VERSION 5.8 ;
BUSBITCHARS "[]" ;
DIVIDERCHAR "/" ;
UNITS
    DATABASE MICRONS 1000 ;
END UNITS

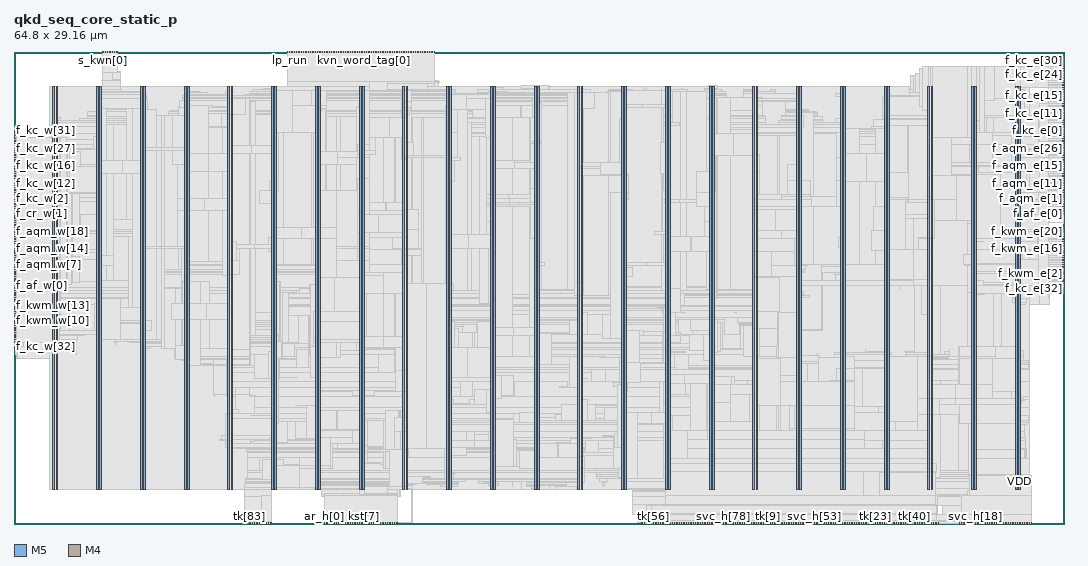
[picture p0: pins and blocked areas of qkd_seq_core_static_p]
MACRO qkd_seq_core_static_p
  FOREIGN qkd_seq_core_static_p 0 0 ;
  CLASS BLOCK ;
  SIZE 64.8 BY 29.16 ;
  PIN ar_h[0]
    DIRECTION INPUT ;
    USE SIGNAL ;
    PORT
      LAYER M5 ;
        RECT  19.152 0 19.176 0.084 ;
    END
  END ar_h[0]
  PIN ar_h[1]
    DIRECTION INPUT ;
    USE SIGNAL ;
    PORT
      LAYER M5 ;
        RECT  19.296 0 19.32 0.084 ;
    END
  END ar_h[1]
  PIN ar_h[2]
    DIRECTION INPUT ;
    USE SIGNAL ;
    PORT
      LAYER M5 ;
        RECT  19.44 0 19.464 0.084 ;
    END
  END ar_h[2]
  PIN ar_h[3]
    DIRECTION INPUT ;
    USE SIGNAL ;
    PORT
      LAYER M5 ;
        RECT  19.584 0 19.608 0.084 ;
    END
  END ar_h[3]
  PIN ar_h[4]
    DIRECTION INPUT ;
    USE SIGNAL ;
    PORT
      LAYER M5 ;
        RECT  19.728 0 19.752 0.084 ;
    END
  END ar_h[4]
  PIN ar_h[5]
    DIRECTION INPUT ;
    USE SIGNAL ;
    PORT
      LAYER M5 ;
        RECT  19.872 0 19.896 0.084 ;
    END
  END ar_h[5]
  PIN ar_h[6]
    DIRECTION INPUT ;
    USE SIGNAL ;
    PORT
      LAYER M5 ;
        RECT  20.016 0 20.04 0.084 ;
    END
  END ar_h[6]
  PIN ar_h[7]
    DIRECTION INPUT ;
    USE SIGNAL ;
    PORT
      LAYER M5 ;
        RECT  20.16 0 20.184 0.084 ;
    END
  END ar_h[7]
  PIN ck
    DIRECTION INPUT ;
    USE SIGNAL ;
    PORT
      LAYER M5 ;
        RECT  21.456 29.076 21.48 29.16 ;
    END
  END ck
  PIN f_af_e[0]
    DIRECTION INPUT ;
    USE SIGNAL ;
    PORT
      LAYER M4 ;
        RECT  64.716 19.152 64.8 19.176 ;
    END
  END f_af_e[0]
  PIN f_af_e[1]
    DIRECTION INPUT ;
    USE SIGNAL ;
    PORT
      LAYER M4 ;
        RECT  64.716 19.296 64.8 19.32 ;
    END
  END f_af_e[1]
  PIN f_af_w[0]
    DIRECTION INPUT ;
    USE SIGNAL ;
    PORT
      LAYER M4 ;
        RECT  0 14.688 0.084 14.712 ;
    END
  END f_af_w[0]
  PIN f_af_w[1]
    DIRECTION INPUT ;
    USE SIGNAL ;
    PORT
      LAYER M4 ;
        RECT  0 14.832 0.084 14.856 ;
    END
  END f_af_w[1]
  PIN f_aqm_e[0]
    DIRECTION OUTPUT ;
    USE SIGNAL ;
    PORT
      LAYER M4 ;
        RECT  64.716 19.44 64.8 19.464 ;
    END
  END f_aqm_e[0]
  PIN f_aqm_e[10]
    DIRECTION OUTPUT ;
    USE SIGNAL ;
    PORT
      LAYER M4 ;
        RECT  64.716 20.88 64.8 20.904 ;
    END
  END f_aqm_e[10]
  PIN f_aqm_e[11]
    DIRECTION OUTPUT ;
    USE SIGNAL ;
    PORT
      LAYER M4 ;
        RECT  64.716 21.024 64.8 21.048 ;
    END
  END f_aqm_e[11]
  PIN f_aqm_e[12]
    DIRECTION OUTPUT ;
    USE SIGNAL ;
    PORT
      LAYER M4 ;
        RECT  64.716 21.168 64.8 21.192 ;
    END
  END f_aqm_e[12]
  PIN f_aqm_e[13]
    DIRECTION OUTPUT ;
    USE SIGNAL ;
    PORT
      LAYER M4 ;
        RECT  64.716 21.312 64.8 21.336 ;
    END
  END f_aqm_e[13]
  PIN f_aqm_e[14]
    DIRECTION OUTPUT ;
    USE SIGNAL ;
    PORT
      LAYER M4 ;
        RECT  64.716 21.456 64.8 21.48 ;
    END
  END f_aqm_e[14]
  PIN f_aqm_e[15]
    DIRECTION OUTPUT ;
    USE SIGNAL ;
    PORT
      LAYER M4 ;
        RECT  64.716 21.6 64.8 21.624 ;
    END
  END f_aqm_e[15]
  PIN f_aqm_e[16]
    DIRECTION OUTPUT ;
    USE SIGNAL ;
    PORT
      LAYER M4 ;
        RECT  64.716 21.744 64.8 21.768 ;
    END
  END f_aqm_e[16]
  PIN f_aqm_e[17]
    DIRECTION OUTPUT ;
    USE SIGNAL ;
    PORT
      LAYER M4 ;
        RECT  64.716 21.888 64.8 21.912 ;
    END
  END f_aqm_e[17]
  PIN f_aqm_e[18]
    DIRECTION OUTPUT ;
    USE SIGNAL ;
    PORT
      LAYER M4 ;
        RECT  64.716 22.032 64.8 22.056 ;
    END
  END f_aqm_e[18]
  PIN f_aqm_e[19]
    DIRECTION OUTPUT ;
    USE SIGNAL ;
    PORT
      LAYER M4 ;
        RECT  64.716 22.176 64.8 22.2 ;
    END
  END f_aqm_e[19]
  PIN f_aqm_e[1]
    DIRECTION OUTPUT ;
    USE SIGNAL ;
    PORT
      LAYER M4 ;
        RECT  64.716 19.584 64.8 19.608 ;
    END
  END f_aqm_e[1]
  PIN f_aqm_e[20]
    DIRECTION OUTPUT ;
    USE SIGNAL ;
    PORT
      LAYER M4 ;
        RECT  64.716 22.32 64.8 22.344 ;
    END
  END f_aqm_e[20]
  PIN f_aqm_e[21]
    DIRECTION OUTPUT ;
    USE SIGNAL ;
    PORT
      LAYER M4 ;
        RECT  64.716 22.464 64.8 22.488 ;
    END
  END f_aqm_e[21]
  PIN f_aqm_e[22]
    DIRECTION OUTPUT ;
    USE SIGNAL ;
    PORT
      LAYER M4 ;
        RECT  64.716 22.608 64.8 22.632 ;
    END
  END f_aqm_e[22]
  PIN f_aqm_e[23]
    DIRECTION OUTPUT ;
    USE SIGNAL ;
    PORT
      LAYER M4 ;
        RECT  64.716 22.752 64.8 22.776 ;
    END
  END f_aqm_e[23]
  PIN f_aqm_e[24]
    DIRECTION OUTPUT ;
    USE SIGNAL ;
    PORT
      LAYER M4 ;
        RECT  64.716 22.896 64.8 22.92 ;
    END
  END f_aqm_e[24]
  PIN f_aqm_e[25]
    DIRECTION OUTPUT ;
    USE SIGNAL ;
    PORT
      LAYER M4 ;
        RECT  64.716 23.04 64.8 23.064 ;
    END
  END f_aqm_e[25]
  PIN f_aqm_e[26]
    DIRECTION OUTPUT ;
    USE SIGNAL ;
    PORT
      LAYER M4 ;
        RECT  64.716 23.184 64.8 23.208 ;
    END
  END f_aqm_e[26]
  PIN f_aqm_e[27]
    DIRECTION OUTPUT ;
    USE SIGNAL ;
    PORT
      LAYER M4 ;
        RECT  64.716 23.328 64.8 23.352 ;
    END
  END f_aqm_e[27]
  PIN f_aqm_e[2]
    DIRECTION OUTPUT ;
    USE SIGNAL ;
    PORT
      LAYER M4 ;
        RECT  64.716 19.728 64.8 19.752 ;
    END
  END f_aqm_e[2]
  PIN f_aqm_e[3]
    DIRECTION OUTPUT ;
    USE SIGNAL ;
    PORT
      LAYER M4 ;
        RECT  64.716 19.872 64.8 19.896 ;
    END
  END f_aqm_e[3]
  PIN f_aqm_e[4]
    DIRECTION OUTPUT ;
    USE SIGNAL ;
    PORT
      LAYER M4 ;
        RECT  64.716 20.016 64.8 20.04 ;
    END
  END f_aqm_e[4]
  PIN f_aqm_e[5]
    DIRECTION OUTPUT ;
    USE SIGNAL ;
    PORT
      LAYER M4 ;
        RECT  64.716 20.16 64.8 20.184 ;
    END
  END f_aqm_e[5]
  PIN f_aqm_e[6]
    DIRECTION OUTPUT ;
    USE SIGNAL ;
    PORT
      LAYER M4 ;
        RECT  64.716 20.304 64.8 20.328 ;
    END
  END f_aqm_e[6]
  PIN f_aqm_e[7]
    DIRECTION OUTPUT ;
    USE SIGNAL ;
    PORT
      LAYER M4 ;
        RECT  64.716 20.448 64.8 20.472 ;
    END
  END f_aqm_e[7]
  PIN f_aqm_e[8]
    DIRECTION OUTPUT ;
    USE SIGNAL ;
    PORT
      LAYER M4 ;
        RECT  64.716 20.592 64.8 20.616 ;
    END
  END f_aqm_e[8]
  PIN f_aqm_e[9]
    DIRECTION OUTPUT ;
    USE SIGNAL ;
    PORT
      LAYER M4 ;
        RECT  64.716 20.736 64.8 20.76 ;
    END
  END f_aqm_e[9]
  PIN f_aqm_w[0]
    DIRECTION OUTPUT ;
    USE SIGNAL ;
    PORT
      LAYER M4 ;
        RECT  0 14.976 0.084 15 ;
    END
  END f_aqm_w[0]
  PIN f_aqm_w[10]
    DIRECTION OUTPUT ;
    USE SIGNAL ;
    PORT
      LAYER M4 ;
        RECT  0 16.416 0.084 16.44 ;
    END
  END f_aqm_w[10]
  PIN f_aqm_w[11]
    DIRECTION OUTPUT ;
    USE SIGNAL ;
    PORT
      LAYER M4 ;
        RECT  0 16.56 0.084 16.584 ;
    END
  END f_aqm_w[11]
  PIN f_aqm_w[12]
    DIRECTION OUTPUT ;
    USE SIGNAL ;
    PORT
      LAYER M4 ;
        RECT  0 16.704 0.084 16.728 ;
    END
  END f_aqm_w[12]
  PIN f_aqm_w[13]
    DIRECTION OUTPUT ;
    USE SIGNAL ;
    PORT
      LAYER M4 ;
        RECT  0 16.848 0.084 16.872 ;
    END
  END f_aqm_w[13]
  PIN f_aqm_w[14]
    DIRECTION OUTPUT ;
    USE SIGNAL ;
    PORT
      LAYER M4 ;
        RECT  0 16.992 0.084 17.016 ;
    END
  END f_aqm_w[14]
  PIN f_aqm_w[15]
    DIRECTION OUTPUT ;
    USE SIGNAL ;
    PORT
      LAYER M4 ;
        RECT  0 17.136 0.084 17.16 ;
    END
  END f_aqm_w[15]
  PIN f_aqm_w[16]
    DIRECTION OUTPUT ;
    USE SIGNAL ;
    PORT
      LAYER M4 ;
        RECT  0 17.28 0.084 17.304 ;
    END
  END f_aqm_w[16]
  PIN f_aqm_w[17]
    DIRECTION OUTPUT ;
    USE SIGNAL ;
    PORT
      LAYER M4 ;
        RECT  0 17.424 0.084 17.448 ;
    END
  END f_aqm_w[17]
  PIN f_aqm_w[18]
    DIRECTION OUTPUT ;
    USE SIGNAL ;
    PORT
      LAYER M4 ;
        RECT  0 17.568 0.084 17.592 ;
    END
  END f_aqm_w[18]
  PIN f_aqm_w[19]
    DIRECTION OUTPUT ;
    USE SIGNAL ;
    PORT
      LAYER M4 ;
        RECT  0 17.712 0.084 17.736 ;
    END
  END f_aqm_w[19]
  PIN f_aqm_w[1]
    DIRECTION OUTPUT ;
    USE SIGNAL ;
    PORT
      LAYER M4 ;
        RECT  0 15.12 0.084 15.144 ;
    END
  END f_aqm_w[1]
  PIN f_aqm_w[20]
    DIRECTION OUTPUT ;
    USE SIGNAL ;
    PORT
      LAYER M4 ;
        RECT  0 17.856 0.084 17.88 ;
    END
  END f_aqm_w[20]
  PIN f_aqm_w[21]
    DIRECTION OUTPUT ;
    USE SIGNAL ;
    PORT
      LAYER M4 ;
        RECT  0 18 0.084 18.024 ;
    END
  END f_aqm_w[21]
  PIN f_aqm_w[22]
    DIRECTION OUTPUT ;
    USE SIGNAL ;
    PORT
      LAYER M4 ;
        RECT  0 18.144 0.084 18.168 ;
    END
  END f_aqm_w[22]
  PIN f_aqm_w[23]
    DIRECTION OUTPUT ;
    USE SIGNAL ;
    PORT
      LAYER M4 ;
        RECT  0 18.288 0.084 18.312 ;
    END
  END f_aqm_w[23]
  PIN f_aqm_w[24]
    DIRECTION OUTPUT ;
    USE SIGNAL ;
    PORT
      LAYER M4 ;
        RECT  0 18.432 0.084 18.456 ;
    END
  END f_aqm_w[24]
  PIN f_aqm_w[25]
    DIRECTION OUTPUT ;
    USE SIGNAL ;
    PORT
      LAYER M4 ;
        RECT  0 18.576 0.084 18.6 ;
    END
  END f_aqm_w[25]
  PIN f_aqm_w[26]
    DIRECTION OUTPUT ;
    USE SIGNAL ;
    PORT
      LAYER M4 ;
        RECT  0 18.72 0.084 18.744 ;
    END
  END f_aqm_w[26]
  PIN f_aqm_w[27]
    DIRECTION OUTPUT ;
    USE SIGNAL ;
    PORT
      LAYER M4 ;
        RECT  0 18.864 0.084 18.888 ;
    END
  END f_aqm_w[27]
  PIN f_aqm_w[2]
    DIRECTION OUTPUT ;
    USE SIGNAL ;
    PORT
      LAYER M4 ;
        RECT  0 15.264 0.084 15.288 ;
    END
  END f_aqm_w[2]
  PIN f_aqm_w[3]
    DIRECTION OUTPUT ;
    USE SIGNAL ;
    PORT
      LAYER M4 ;
        RECT  0 15.408 0.084 15.432 ;
    END
  END f_aqm_w[3]
  PIN f_aqm_w[4]
    DIRECTION OUTPUT ;
    USE SIGNAL ;
    PORT
      LAYER M4 ;
        RECT  0 15.552 0.084 15.576 ;
    END
  END f_aqm_w[4]
  PIN f_aqm_w[5]
    DIRECTION OUTPUT ;
    USE SIGNAL ;
    PORT
      LAYER M4 ;
        RECT  0 15.696 0.084 15.72 ;
    END
  END f_aqm_w[5]
  PIN f_aqm_w[6]
    DIRECTION OUTPUT ;
    USE SIGNAL ;
    PORT
      LAYER M4 ;
        RECT  0 15.84 0.084 15.864 ;
    END
  END f_aqm_w[6]
  PIN f_aqm_w[7]
    DIRECTION OUTPUT ;
    USE SIGNAL ;
    PORT
      LAYER M4 ;
        RECT  0 15.984 0.084 16.008 ;
    END
  END f_aqm_w[7]
  PIN f_aqm_w[8]
    DIRECTION OUTPUT ;
    USE SIGNAL ;
    PORT
      LAYER M4 ;
        RECT  0 16.128 0.084 16.152 ;
    END
  END f_aqm_w[8]
  PIN f_aqm_w[9]
    DIRECTION OUTPUT ;
    USE SIGNAL ;
    PORT
      LAYER M4 ;
        RECT  0 16.272 0.084 16.296 ;
    END
  END f_aqm_w[9]
  PIN f_cr_e[0]
    DIRECTION INPUT ;
    USE SIGNAL ;
    PORT
      LAYER M4 ;
        RECT  64.716 23.472 64.8 23.496 ;
    END
  END f_cr_e[0]
  PIN f_cr_e[1]
    DIRECTION INPUT ;
    USE SIGNAL ;
    PORT
      LAYER M4 ;
        RECT  64.716 23.616 64.8 23.64 ;
    END
  END f_cr_e[1]
  PIN f_cr_w[0]
    DIRECTION INPUT ;
    USE SIGNAL ;
    PORT
      LAYER M4 ;
        RECT  0 19.008 0.084 19.032 ;
    END
  END f_cr_w[0]
  PIN f_cr_w[1]
    DIRECTION INPUT ;
    USE SIGNAL ;
    PORT
      LAYER M4 ;
        RECT  0 19.152 0.084 19.176 ;
    END
  END f_cr_w[1]
  PIN f_kc_e[0]
    DIRECTION OUTPUT ;
    USE SIGNAL ;
    PORT
      LAYER M4 ;
        RECT  64.716 23.76 64.8 23.784 ;
    END
  END f_kc_e[0]
  PIN f_kc_e[10]
    DIRECTION OUTPUT ;
    USE SIGNAL ;
    PORT
      LAYER M4 ;
        RECT  64.716 25.2 64.8 25.224 ;
    END
  END f_kc_e[10]
  PIN f_kc_e[11]
    DIRECTION OUTPUT ;
    USE SIGNAL ;
    PORT
      LAYER M4 ;
        RECT  64.716 25.344 64.8 25.368 ;
    END
  END f_kc_e[11]
  PIN f_kc_e[12]
    DIRECTION OUTPUT ;
    USE SIGNAL ;
    PORT
      LAYER M4 ;
        RECT  64.716 25.488 64.8 25.512 ;
    END
  END f_kc_e[12]
  PIN f_kc_e[13]
    DIRECTION OUTPUT ;
    USE SIGNAL ;
    PORT
      LAYER M4 ;
        RECT  64.716 25.632 64.8 25.656 ;
    END
  END f_kc_e[13]
  PIN f_kc_e[14]
    DIRECTION OUTPUT ;
    USE SIGNAL ;
    PORT
      LAYER M4 ;
        RECT  64.716 25.776 64.8 25.8 ;
    END
  END f_kc_e[14]
  PIN f_kc_e[15]
    DIRECTION OUTPUT ;
    USE SIGNAL ;
    PORT
      LAYER M4 ;
        RECT  64.716 25.92 64.8 25.944 ;
    END
  END f_kc_e[15]
  PIN f_kc_e[16]
    DIRECTION OUTPUT ;
    USE SIGNAL ;
    PORT
      LAYER M4 ;
        RECT  64.716 26.064 64.8 26.088 ;
    END
  END f_kc_e[16]
  PIN f_kc_e[17]
    DIRECTION OUTPUT ;
    USE SIGNAL ;
    PORT
      LAYER M4 ;
        RECT  64.716 26.208 64.8 26.232 ;
    END
  END f_kc_e[17]
  PIN f_kc_e[18]
    DIRECTION OUTPUT ;
    USE SIGNAL ;
    PORT
      LAYER M4 ;
        RECT  64.716 26.352 64.8 26.376 ;
    END
  END f_kc_e[18]
  PIN f_kc_e[19]
    DIRECTION OUTPUT ;
    USE SIGNAL ;
    PORT
      LAYER M4 ;
        RECT  64.716 26.496 64.8 26.52 ;
    END
  END f_kc_e[19]
  PIN f_kc_e[1]
    DIRECTION OUTPUT ;
    USE SIGNAL ;
    PORT
      LAYER M4 ;
        RECT  64.716 23.904 64.8 23.928 ;
    END
  END f_kc_e[1]
  PIN f_kc_e[20]
    DIRECTION OUTPUT ;
    USE SIGNAL ;
    PORT
      LAYER M4 ;
        RECT  64.716 26.64 64.8 26.664 ;
    END
  END f_kc_e[20]
  PIN f_kc_e[21]
    DIRECTION OUTPUT ;
    USE SIGNAL ;
    PORT
      LAYER M4 ;
        RECT  64.716 26.784 64.8 26.808 ;
    END
  END f_kc_e[21]
  PIN f_kc_e[22]
    DIRECTION OUTPUT ;
    USE SIGNAL ;
    PORT
      LAYER M4 ;
        RECT  64.716 26.928 64.8 26.952 ;
    END
  END f_kc_e[22]
  PIN f_kc_e[23]
    DIRECTION OUTPUT ;
    USE SIGNAL ;
    PORT
      LAYER M4 ;
        RECT  64.716 27.072 64.8 27.096 ;
    END
  END f_kc_e[23]
  PIN f_kc_e[24]
    DIRECTION OUTPUT ;
    USE SIGNAL ;
    PORT
      LAYER M4 ;
        RECT  64.716 27.216 64.8 27.24 ;
    END
  END f_kc_e[24]
  PIN f_kc_e[25]
    DIRECTION OUTPUT ;
    USE SIGNAL ;
    PORT
      LAYER M4 ;
        RECT  64.716 27.36 64.8 27.384 ;
    END
  END f_kc_e[25]
  PIN f_kc_e[26]
    DIRECTION OUTPUT ;
    USE SIGNAL ;
    PORT
      LAYER M4 ;
        RECT  64.716 27.504 64.8 27.528 ;
    END
  END f_kc_e[26]
  PIN f_kc_e[27]
    DIRECTION OUTPUT ;
    USE SIGNAL ;
    PORT
      LAYER M4 ;
        RECT  64.716 27.648 64.8 27.672 ;
    END
  END f_kc_e[27]
  PIN f_kc_e[28]
    DIRECTION OUTPUT ;
    USE SIGNAL ;
    PORT
      LAYER M4 ;
        RECT  64.716 27.792 64.8 27.816 ;
    END
  END f_kc_e[28]
  PIN f_kc_e[29]
    DIRECTION OUTPUT ;
    USE SIGNAL ;
    PORT
      LAYER M4 ;
        RECT  64.716 27.936 64.8 27.96 ;
    END
  END f_kc_e[29]
  PIN f_kc_e[2]
    DIRECTION OUTPUT ;
    USE SIGNAL ;
    PORT
      LAYER M4 ;
        RECT  64.716 24.048 64.8 24.072 ;
    END
  END f_kc_e[2]
  PIN f_kc_e[30]
    DIRECTION OUTPUT ;
    USE SIGNAL ;
    PORT
      LAYER M4 ;
        RECT  64.716 28.08 64.8 28.104 ;
    END
  END f_kc_e[30]
  PIN f_kc_e[31]
    DIRECTION OUTPUT ;
    USE SIGNAL ;
    PORT
      LAYER M4 ;
        RECT  64.716 28.224 64.8 28.248 ;
    END
  END f_kc_e[31]
  PIN f_kc_e[32]
    DIRECTION OUTPUT ;
    USE SIGNAL ;
    PORT
      LAYER M4 ;
        RECT  64.716 14.544 64.8 14.568 ;
    END
  END f_kc_e[32]
  PIN f_kc_e[3]
    DIRECTION OUTPUT ;
    USE SIGNAL ;
    PORT
      LAYER M4 ;
        RECT  64.716 24.192 64.8 24.216 ;
    END
  END f_kc_e[3]
  PIN f_kc_e[4]
    DIRECTION OUTPUT ;
    USE SIGNAL ;
    PORT
      LAYER M4 ;
        RECT  64.716 24.336 64.8 24.36 ;
    END
  END f_kc_e[4]
  PIN f_kc_e[5]
    DIRECTION OUTPUT ;
    USE SIGNAL ;
    PORT
      LAYER M4 ;
        RECT  64.716 24.48 64.8 24.504 ;
    END
  END f_kc_e[5]
  PIN f_kc_e[6]
    DIRECTION OUTPUT ;
    USE SIGNAL ;
    PORT
      LAYER M4 ;
        RECT  64.716 24.624 64.8 24.648 ;
    END
  END f_kc_e[6]
  PIN f_kc_e[7]
    DIRECTION OUTPUT ;
    USE SIGNAL ;
    PORT
      LAYER M4 ;
        RECT  64.716 24.768 64.8 24.792 ;
    END
  END f_kc_e[7]
  PIN f_kc_e[8]
    DIRECTION OUTPUT ;
    USE SIGNAL ;
    PORT
      LAYER M4 ;
        RECT  64.716 24.912 64.8 24.936 ;
    END
  END f_kc_e[8]
  PIN f_kc_e[9]
    DIRECTION OUTPUT ;
    USE SIGNAL ;
    PORT
      LAYER M4 ;
        RECT  64.716 25.056 64.8 25.08 ;
    END
  END f_kc_e[9]
  PIN f_kc_w[0]
    DIRECTION OUTPUT ;
    USE SIGNAL ;
    PORT
      LAYER M4 ;
        RECT  0 19.296 0.084 19.32 ;
    END
  END f_kc_w[0]
  PIN f_kc_w[10]
    DIRECTION OUTPUT ;
    USE SIGNAL ;
    PORT
      LAYER M4 ;
        RECT  0 20.736 0.084 20.76 ;
    END
  END f_kc_w[10]
  PIN f_kc_w[11]
    DIRECTION OUTPUT ;
    USE SIGNAL ;
    PORT
      LAYER M4 ;
        RECT  0 20.88 0.084 20.904 ;
    END
  END f_kc_w[11]
  PIN f_kc_w[12]
    DIRECTION OUTPUT ;
    USE SIGNAL ;
    PORT
      LAYER M4 ;
        RECT  0 21.024 0.084 21.048 ;
    END
  END f_kc_w[12]
  PIN f_kc_w[13]
    DIRECTION OUTPUT ;
    USE SIGNAL ;
    PORT
      LAYER M4 ;
        RECT  0 21.168 0.084 21.192 ;
    END
  END f_kc_w[13]
  PIN f_kc_w[14]
    DIRECTION OUTPUT ;
    USE SIGNAL ;
    PORT
      LAYER M4 ;
        RECT  0 21.312 0.084 21.336 ;
    END
  END f_kc_w[14]
  PIN f_kc_w[15]
    DIRECTION OUTPUT ;
    USE SIGNAL ;
    PORT
      LAYER M4 ;
        RECT  0 21.456 0.084 21.48 ;
    END
  END f_kc_w[15]
  PIN f_kc_w[16]
    DIRECTION OUTPUT ;
    USE SIGNAL ;
    PORT
      LAYER M4 ;
        RECT  0 21.6 0.084 21.624 ;
    END
  END f_kc_w[16]
  PIN f_kc_w[17]
    DIRECTION OUTPUT ;
    USE SIGNAL ;
    PORT
      LAYER M4 ;
        RECT  0 21.744 0.084 21.768 ;
    END
  END f_kc_w[17]
  PIN f_kc_w[18]
    DIRECTION OUTPUT ;
    USE SIGNAL ;
    PORT
      LAYER M4 ;
        RECT  0 21.888 0.084 21.912 ;
    END
  END f_kc_w[18]
  PIN f_kc_w[19]
    DIRECTION OUTPUT ;
    USE SIGNAL ;
    PORT
      LAYER M4 ;
        RECT  0 22.032 0.084 22.056 ;
    END
  END f_kc_w[19]
  PIN f_kc_w[1]
    DIRECTION OUTPUT ;
    USE SIGNAL ;
    PORT
      LAYER M4 ;
        RECT  0 19.44 0.084 19.464 ;
    END
  END f_kc_w[1]
  PIN f_kc_w[20]
    DIRECTION OUTPUT ;
    USE SIGNAL ;
    PORT
      LAYER M4 ;
        RECT  0 22.176 0.084 22.2 ;
    END
  END f_kc_w[20]
  PIN f_kc_w[21]
    DIRECTION OUTPUT ;
    USE SIGNAL ;
    PORT
      LAYER M4 ;
        RECT  0 22.32 0.084 22.344 ;
    END
  END f_kc_w[21]
  PIN f_kc_w[22]
    DIRECTION OUTPUT ;
    USE SIGNAL ;
    PORT
      LAYER M4 ;
        RECT  0 22.464 0.084 22.488 ;
    END
  END f_kc_w[22]
  PIN f_kc_w[23]
    DIRECTION OUTPUT ;
    USE SIGNAL ;
    PORT
      LAYER M4 ;
        RECT  0 22.608 0.084 22.632 ;
    END
  END f_kc_w[23]
  PIN f_kc_w[24]
    DIRECTION OUTPUT ;
    USE SIGNAL ;
    PORT
      LAYER M4 ;
        RECT  0 22.752 0.084 22.776 ;
    END
  END f_kc_w[24]
  PIN f_kc_w[25]
    DIRECTION OUTPUT ;
    USE SIGNAL ;
    PORT
      LAYER M4 ;
        RECT  0 22.896 0.084 22.92 ;
    END
  END f_kc_w[25]
  PIN f_kc_w[26]
    DIRECTION OUTPUT ;
    USE SIGNAL ;
    PORT
      LAYER M4 ;
        RECT  0 23.04 0.084 23.064 ;
    END
  END f_kc_w[26]
  PIN f_kc_w[27]
    DIRECTION OUTPUT ;
    USE SIGNAL ;
    PORT
      LAYER M4 ;
        RECT  0 23.184 0.084 23.208 ;
    END
  END f_kc_w[27]
  PIN f_kc_w[28]
    DIRECTION OUTPUT ;
    USE SIGNAL ;
    PORT
      LAYER M4 ;
        RECT  0 23.328 0.084 23.352 ;
    END
  END f_kc_w[28]
  PIN f_kc_w[29]
    DIRECTION OUTPUT ;
    USE SIGNAL ;
    PORT
      LAYER M4 ;
        RECT  0 23.472 0.084 23.496 ;
    END
  END f_kc_w[29]
  PIN f_kc_w[2]
    DIRECTION OUTPUT ;
    USE SIGNAL ;
    PORT
      LAYER M4 ;
        RECT  0 19.584 0.084 19.608 ;
    END
  END f_kc_w[2]
  PIN f_kc_w[30]
    DIRECTION OUTPUT ;
    USE SIGNAL ;
    PORT
      LAYER M4 ;
        RECT  0 23.616 0.084 23.64 ;
    END
  END f_kc_w[30]
  PIN f_kc_w[31]
    DIRECTION OUTPUT ;
    USE SIGNAL ;
    PORT
      LAYER M4 ;
        RECT  0 23.76 0.084 23.784 ;
    END
  END f_kc_w[31]
  PIN f_kc_w[32]
    DIRECTION OUTPUT ;
    USE SIGNAL ;
    PORT
      LAYER M4 ;
        RECT  0 10.944 0.084 10.968 ;
    END
  END f_kc_w[32]
  PIN f_kc_w[3]
    DIRECTION OUTPUT ;
    USE SIGNAL ;
    PORT
      LAYER M4 ;
        RECT  0 19.728 0.084 19.752 ;
    END
  END f_kc_w[3]
  PIN f_kc_w[4]
    DIRECTION OUTPUT ;
    USE SIGNAL ;
    PORT
      LAYER M4 ;
        RECT  0 19.872 0.084 19.896 ;
    END
  END f_kc_w[4]
  PIN f_kc_w[5]
    DIRECTION OUTPUT ;
    USE SIGNAL ;
    PORT
      LAYER M4 ;
        RECT  0 20.016 0.084 20.04 ;
    END
  END f_kc_w[5]
  PIN f_kc_w[6]
    DIRECTION OUTPUT ;
    USE SIGNAL ;
    PORT
      LAYER M4 ;
        RECT  0 20.16 0.084 20.184 ;
    END
  END f_kc_w[6]
  PIN f_kc_w[7]
    DIRECTION OUTPUT ;
    USE SIGNAL ;
    PORT
      LAYER M4 ;
        RECT  0 20.304 0.084 20.328 ;
    END
  END f_kc_w[7]
  PIN f_kc_w[8]
    DIRECTION OUTPUT ;
    USE SIGNAL ;
    PORT
      LAYER M4 ;
        RECT  0 20.448 0.084 20.472 ;
    END
  END f_kc_w[8]
  PIN f_kc_w[9]
    DIRECTION OUTPUT ;
    USE SIGNAL ;
    PORT
      LAYER M4 ;
        RECT  0 20.592 0.084 20.616 ;
    END
  END f_kc_w[9]
  PIN f_kwm_e[0]
    DIRECTION OUTPUT ;
    USE SIGNAL ;
    PORT
      LAYER M4 ;
        RECT  64.716 14.688 64.8 14.712 ;
    END
  END f_kwm_e[0]
  PIN f_kwm_e[10]
    DIRECTION OUTPUT ;
    USE SIGNAL ;
    PORT
      LAYER M4 ;
        RECT  64.716 16.128 64.8 16.152 ;
    END
  END f_kwm_e[10]
  PIN f_kwm_e[11]
    DIRECTION OUTPUT ;
    USE SIGNAL ;
    PORT
      LAYER M4 ;
        RECT  64.716 16.272 64.8 16.296 ;
    END
  END f_kwm_e[11]
  PIN f_kwm_e[12]
    DIRECTION OUTPUT ;
    USE SIGNAL ;
    PORT
      LAYER M4 ;
        RECT  64.716 16.416 64.8 16.44 ;
    END
  END f_kwm_e[12]
  PIN f_kwm_e[13]
    DIRECTION OUTPUT ;
    USE SIGNAL ;
    PORT
      LAYER M4 ;
        RECT  64.716 16.56 64.8 16.584 ;
    END
  END f_kwm_e[13]
  PIN f_kwm_e[14]
    DIRECTION OUTPUT ;
    USE SIGNAL ;
    PORT
      LAYER M4 ;
        RECT  64.716 16.704 64.8 16.728 ;
    END
  END f_kwm_e[14]
  PIN f_kwm_e[15]
    DIRECTION OUTPUT ;
    USE SIGNAL ;
    PORT
      LAYER M4 ;
        RECT  64.716 16.848 64.8 16.872 ;
    END
  END f_kwm_e[15]
  PIN f_kwm_e[16]
    DIRECTION OUTPUT ;
    USE SIGNAL ;
    PORT
      LAYER M4 ;
        RECT  64.716 16.992 64.8 17.016 ;
    END
  END f_kwm_e[16]
  PIN f_kwm_e[17]
    DIRECTION OUTPUT ;
    USE SIGNAL ;
    PORT
      LAYER M4 ;
        RECT  64.716 17.136 64.8 17.16 ;
    END
  END f_kwm_e[17]
  PIN f_kwm_e[18]
    DIRECTION OUTPUT ;
    USE SIGNAL ;
    PORT
      LAYER M4 ;
        RECT  64.716 17.28 64.8 17.304 ;
    END
  END f_kwm_e[18]
  PIN f_kwm_e[19]
    DIRECTION OUTPUT ;
    USE SIGNAL ;
    PORT
      LAYER M4 ;
        RECT  64.716 17.424 64.8 17.448 ;
    END
  END f_kwm_e[19]
  PIN f_kwm_e[1]
    DIRECTION OUTPUT ;
    USE SIGNAL ;
    PORT
      LAYER M4 ;
        RECT  64.716 14.832 64.8 14.856 ;
    END
  END f_kwm_e[1]
  PIN f_kwm_e[20]
    DIRECTION OUTPUT ;
    USE SIGNAL ;
    PORT
      LAYER M4 ;
        RECT  64.716 17.568 64.8 17.592 ;
    END
  END f_kwm_e[20]
  PIN f_kwm_e[21]
    DIRECTION OUTPUT ;
    USE SIGNAL ;
    PORT
      LAYER M4 ;
        RECT  64.716 17.712 64.8 17.736 ;
    END
  END f_kwm_e[21]
  PIN f_kwm_e[22]
    DIRECTION OUTPUT ;
    USE SIGNAL ;
    PORT
      LAYER M4 ;
        RECT  64.716 17.856 64.8 17.88 ;
    END
  END f_kwm_e[22]
  PIN f_kwm_e[2]
    DIRECTION OUTPUT ;
    USE SIGNAL ;
    PORT
      LAYER M4 ;
        RECT  64.716 14.976 64.8 15 ;
    END
  END f_kwm_e[2]
  PIN f_kwm_e[3]
    DIRECTION OUTPUT ;
    USE SIGNAL ;
    PORT
      LAYER M4 ;
        RECT  64.716 15.12 64.8 15.144 ;
    END
  END f_kwm_e[3]
  PIN f_kwm_e[4]
    DIRECTION OUTPUT ;
    USE SIGNAL ;
    PORT
      LAYER M4 ;
        RECT  64.716 15.264 64.8 15.288 ;
    END
  END f_kwm_e[4]
  PIN f_kwm_e[5]
    DIRECTION OUTPUT ;
    USE SIGNAL ;
    PORT
      LAYER M4 ;
        RECT  64.716 15.408 64.8 15.432 ;
    END
  END f_kwm_e[5]
  PIN f_kwm_e[6]
    DIRECTION OUTPUT ;
    USE SIGNAL ;
    PORT
      LAYER M4 ;
        RECT  64.716 15.552 64.8 15.576 ;
    END
  END f_kwm_e[6]
  PIN f_kwm_e[7]
    DIRECTION OUTPUT ;
    USE SIGNAL ;
    PORT
      LAYER M4 ;
        RECT  64.716 15.696 64.8 15.72 ;
    END
  END f_kwm_e[7]
  PIN f_kwm_e[8]
    DIRECTION OUTPUT ;
    USE SIGNAL ;
    PORT
      LAYER M4 ;
        RECT  64.716 15.84 64.8 15.864 ;
    END
  END f_kwm_e[8]
  PIN f_kwm_e[9]
    DIRECTION OUTPUT ;
    USE SIGNAL ;
    PORT
      LAYER M4 ;
        RECT  64.716 15.984 64.8 16.008 ;
    END
  END f_kwm_e[9]
  PIN f_kwm_w[0]
    DIRECTION OUTPUT ;
    USE SIGNAL ;
    PORT
      LAYER M4 ;
        RECT  0 11.088 0.084 11.112 ;
    END
  END f_kwm_w[0]
  PIN f_kwm_w[10]
    DIRECTION OUTPUT ;
    USE SIGNAL ;
    PORT
      LAYER M4 ;
        RECT  0 12.528 0.084 12.552 ;
    END
  END f_kwm_w[10]
  PIN f_kwm_w[11]
    DIRECTION OUTPUT ;
    USE SIGNAL ;
    PORT
      LAYER M4 ;
        RECT  0 12.672 0.084 12.696 ;
    END
  END f_kwm_w[11]
  PIN f_kwm_w[12]
    DIRECTION OUTPUT ;
    USE SIGNAL ;
    PORT
      LAYER M4 ;
        RECT  0 12.816 0.084 12.84 ;
    END
  END f_kwm_w[12]
  PIN f_kwm_w[13]
    DIRECTION OUTPUT ;
    USE SIGNAL ;
    PORT
      LAYER M4 ;
        RECT  0 12.96 0.084 12.984 ;
    END
  END f_kwm_w[13]
  PIN f_kwm_w[14]
    DIRECTION OUTPUT ;
    USE SIGNAL ;
    PORT
      LAYER M4 ;
        RECT  0 13.104 0.084 13.128 ;
    END
  END f_kwm_w[14]
  PIN f_kwm_w[15]
    DIRECTION OUTPUT ;
    USE SIGNAL ;
    PORT
      LAYER M4 ;
        RECT  0 13.248 0.084 13.272 ;
    END
  END f_kwm_w[15]
  PIN f_kwm_w[16]
    DIRECTION OUTPUT ;
    USE SIGNAL ;
    PORT
      LAYER M4 ;
        RECT  0 13.392 0.084 13.416 ;
    END
  END f_kwm_w[16]
  PIN f_kwm_w[17]
    DIRECTION OUTPUT ;
    USE SIGNAL ;
    PORT
      LAYER M4 ;
        RECT  0 13.536 0.084 13.56 ;
    END
  END f_kwm_w[17]
  PIN f_kwm_w[18]
    DIRECTION OUTPUT ;
    USE SIGNAL ;
    PORT
      LAYER M4 ;
        RECT  0 13.68 0.084 13.704 ;
    END
  END f_kwm_w[18]
  PIN f_kwm_w[19]
    DIRECTION OUTPUT ;
    USE SIGNAL ;
    PORT
      LAYER M4 ;
        RECT  0 13.824 0.084 13.848 ;
    END
  END f_kwm_w[19]
  PIN f_kwm_w[1]
    DIRECTION OUTPUT ;
    USE SIGNAL ;
    PORT
      LAYER M4 ;
        RECT  0 11.232 0.084 11.256 ;
    END
  END f_kwm_w[1]
  PIN f_kwm_w[20]
    DIRECTION OUTPUT ;
    USE SIGNAL ;
    PORT
      LAYER M4 ;
        RECT  0 13.968 0.084 13.992 ;
    END
  END f_kwm_w[20]
  PIN f_kwm_w[21]
    DIRECTION OUTPUT ;
    USE SIGNAL ;
    PORT
      LAYER M4 ;
        RECT  0 14.112 0.084 14.136 ;
    END
  END f_kwm_w[21]
  PIN f_kwm_w[22]
    DIRECTION OUTPUT ;
    USE SIGNAL ;
    PORT
      LAYER M4 ;
        RECT  0 14.256 0.084 14.28 ;
    END
  END f_kwm_w[22]
  PIN f_kwm_w[2]
    DIRECTION OUTPUT ;
    USE SIGNAL ;
    PORT
      LAYER M4 ;
        RECT  0 11.376 0.084 11.4 ;
    END
  END f_kwm_w[2]
  PIN f_kwm_w[3]
    DIRECTION OUTPUT ;
    USE SIGNAL ;
    PORT
      LAYER M4 ;
        RECT  0 11.52 0.084 11.544 ;
    END
  END f_kwm_w[3]
  PIN f_kwm_w[4]
    DIRECTION OUTPUT ;
    USE SIGNAL ;
    PORT
      LAYER M4 ;
        RECT  0 11.664 0.084 11.688 ;
    END
  END f_kwm_w[4]
  PIN f_kwm_w[5]
    DIRECTION OUTPUT ;
    USE SIGNAL ;
    PORT
      LAYER M4 ;
        RECT  0 11.808 0.084 11.832 ;
    END
  END f_kwm_w[5]
  PIN f_kwm_w[6]
    DIRECTION OUTPUT ;
    USE SIGNAL ;
    PORT
      LAYER M4 ;
        RECT  0 11.952 0.084 11.976 ;
    END
  END f_kwm_w[6]
  PIN f_kwm_w[7]
    DIRECTION OUTPUT ;
    USE SIGNAL ;
    PORT
      LAYER M4 ;
        RECT  0 12.096 0.084 12.12 ;
    END
  END f_kwm_w[7]
  PIN f_kwm_w[8]
    DIRECTION OUTPUT ;
    USE SIGNAL ;
    PORT
      LAYER M4 ;
        RECT  0 12.24 0.084 12.264 ;
    END
  END f_kwm_w[8]
  PIN f_kwm_w[9]
    DIRECTION OUTPUT ;
    USE SIGNAL ;
    PORT
      LAYER M4 ;
        RECT  0 12.384 0.084 12.408 ;
    END
  END f_kwm_w[9]
  PIN f_mf_e[0]
    DIRECTION INPUT ;
    USE SIGNAL ;
    PORT
      LAYER M4 ;
        RECT  64.716 18 64.8 18.024 ;
    END
  END f_mf_e[0]
  PIN f_mf_e[1]
    DIRECTION INPUT ;
    USE SIGNAL ;
    PORT
      LAYER M4 ;
        RECT  64.716 18.144 64.8 18.168 ;
    END
  END f_mf_e[1]
  PIN f_mf_w[0]
    DIRECTION INPUT ;
    USE SIGNAL ;
    PORT
      LAYER M4 ;
        RECT  0 14.4 0.084 14.424 ;
    END
  END f_mf_w[0]
  PIN f_mf_w[1]
    DIRECTION INPUT ;
    USE SIGNAL ;
    PORT
      LAYER M4 ;
        RECT  0 14.544 0.084 14.568 ;
    END
  END f_mf_w[1]
  PIN hf
    DIRECTION INPUT ;
    USE SIGNAL ;
    PORT
      LAYER M5 ;
        RECT  20.304 0 20.328 0.084 ;
    END
  END hf
  PIN hs
    DIRECTION OUTPUT ;
    USE SIGNAL ;
    PORT
      LAYER M5 ;
        RECT  20.448 0 20.472 0.084 ;
    END
  END hs
  PIN kst[0]
    DIRECTION OUTPUT ;
    USE SIGNAL ;
    PORT
      LAYER M5 ;
        RECT  20.592 0 20.616 0.084 ;
    END
  END kst[0]
  PIN kst[1]
    DIRECTION OUTPUT ;
    USE SIGNAL ;
    PORT
      LAYER M5 ;
        RECT  20.736 0 20.76 0.084 ;
    END
  END kst[1]
  PIN kst[2]
    DIRECTION OUTPUT ;
    USE SIGNAL ;
    PORT
      LAYER M5 ;
        RECT  20.88 0 20.904 0.084 ;
    END
  END kst[2]
  PIN kst[3]
    DIRECTION OUTPUT ;
    USE SIGNAL ;
    PORT
      LAYER M5 ;
        RECT  21.024 0 21.048 0.084 ;
    END
  END kst[3]
  PIN kst[4]
    DIRECTION OUTPUT ;
    USE SIGNAL ;
    PORT
      LAYER M5 ;
        RECT  21.168 0 21.192 0.084 ;
    END
  END kst[4]
  PIN kst[5]
    DIRECTION OUTPUT ;
    USE SIGNAL ;
    PORT
      LAYER M5 ;
        RECT  21.312 0 21.336 0.084 ;
    END
  END kst[5]
  PIN kst[6]
    DIRECTION OUTPUT ;
    USE SIGNAL ;
    PORT
      LAYER M5 ;
        RECT  21.456 0 21.48 0.084 ;
    END
  END kst[6]
  PIN kst[7]
    DIRECTION OUTPUT ;
    USE SIGNAL ;
    PORT
      LAYER M5 ;
        RECT  21.6 0 21.624 0.084 ;
    END
  END kst[7]
  PIN kst[8]
    DIRECTION OUTPUT ;
    USE SIGNAL ;
    PORT
      LAYER M5 ;
        RECT  21.744 0 21.768 0.084 ;
    END
  END kst[8]
  PIN kst[9]
    DIRECTION OUTPUT ;
    USE SIGNAL ;
    PORT
      LAYER M5 ;
        RECT  21.888 0 21.912 0.084 ;
    END
  END kst[9]
  PIN kvn_word_tag[0]
    DIRECTION INPUT ;
    USE SIGNAL ;
    PORT
      LAYER M5 ;
        RECT  21.6 29.076 21.624 29.16 ;
    END
  END kvn_word_tag[0]
  PIN kvn_word_tag[10]
    DIRECTION INPUT ;
    USE SIGNAL ;
    PORT
      LAYER M5 ;
        RECT  23.04 29.076 23.064 29.16 ;
    END
  END kvn_word_tag[10]
  PIN kvn_word_tag[1]
    DIRECTION INPUT ;
    USE SIGNAL ;
    PORT
      LAYER M5 ;
        RECT  21.744 29.076 21.768 29.16 ;
    END
  END kvn_word_tag[1]
  PIN kvn_word_tag[2]
    DIRECTION INPUT ;
    USE SIGNAL ;
    PORT
      LAYER M5 ;
        RECT  21.888 29.076 21.912 29.16 ;
    END
  END kvn_word_tag[2]
  PIN kvn_word_tag[3]
    DIRECTION INPUT ;
    USE SIGNAL ;
    PORT
      LAYER M5 ;
        RECT  22.032 29.076 22.056 29.16 ;
    END
  END kvn_word_tag[3]
  PIN kvn_word_tag[4]
    DIRECTION INPUT ;
    USE SIGNAL ;
    PORT
      LAYER M5 ;
        RECT  22.176 29.076 22.2 29.16 ;
    END
  END kvn_word_tag[4]
  PIN kvn_word_tag[5]
    DIRECTION INPUT ;
    USE SIGNAL ;
    PORT
      LAYER M5 ;
        RECT  22.32 29.076 22.344 29.16 ;
    END
  END kvn_word_tag[5]
  PIN kvn_word_tag[6]
    DIRECTION INPUT ;
    USE SIGNAL ;
    PORT
      LAYER M5 ;
        RECT  22.464 29.076 22.488 29.16 ;
    END
  END kvn_word_tag[6]
  PIN kvn_word_tag[7]
    DIRECTION INPUT ;
    USE SIGNAL ;
    PORT
      LAYER M5 ;
        RECT  22.608 29.076 22.632 29.16 ;
    END
  END kvn_word_tag[7]
  PIN kvn_word_tag[8]
    DIRECTION INPUT ;
    USE SIGNAL ;
    PORT
      LAYER M5 ;
        RECT  22.752 29.076 22.776 29.16 ;
    END
  END kvn_word_tag[8]
  PIN kvn_word_tag[9]
    DIRECTION INPUT ;
    USE SIGNAL ;
    PORT
      LAYER M5 ;
        RECT  22.896 29.076 22.92 29.16 ;
    END
  END kvn_word_tag[9]
  PIN kvn_word_valid
    DIRECTION INPUT ;
    USE SIGNAL ;
    PORT
      LAYER M5 ;
        RECT  23.184 29.076 23.208 29.16 ;
    END
  END kvn_word_valid
  PIN lp_ctx_t[0]
    DIRECTION INPUT ;
    USE SIGNAL ;
    PORT
      LAYER M5 ;
        RECT  23.328 29.076 23.352 29.16 ;
    END
  END lp_ctx_t[0]
  PIN lp_ctx_t[10]
    DIRECTION INPUT ;
    USE SIGNAL ;
    PORT
      LAYER M5 ;
        RECT  24.768 29.076 24.792 29.16 ;
    END
  END lp_ctx_t[10]
  PIN lp_ctx_t[11]
    DIRECTION INPUT ;
    USE SIGNAL ;
    PORT
      LAYER M5 ;
        RECT  24.912 29.076 24.936 29.16 ;
    END
  END lp_ctx_t[11]
  PIN lp_ctx_t[12]
    DIRECTION INPUT ;
    USE SIGNAL ;
    PORT
      LAYER M5 ;
        RECT  25.056 29.076 25.08 29.16 ;
    END
  END lp_ctx_t[12]
  PIN lp_ctx_t[13]
    DIRECTION INPUT ;
    USE SIGNAL ;
    PORT
      LAYER M5 ;
        RECT  25.2 29.076 25.224 29.16 ;
    END
  END lp_ctx_t[13]
  PIN lp_ctx_t[1]
    DIRECTION INPUT ;
    USE SIGNAL ;
    PORT
      LAYER M5 ;
        RECT  23.472 29.076 23.496 29.16 ;
    END
  END lp_ctx_t[1]
  PIN lp_ctx_t[2]
    DIRECTION INPUT ;
    USE SIGNAL ;
    PORT
      LAYER M5 ;
        RECT  23.616 29.076 23.64 29.16 ;
    END
  END lp_ctx_t[2]
  PIN lp_ctx_t[3]
    DIRECTION INPUT ;
    USE SIGNAL ;
    PORT
      LAYER M5 ;
        RECT  23.76 29.076 23.784 29.16 ;
    END
  END lp_ctx_t[3]
  PIN lp_ctx_t[4]
    DIRECTION INPUT ;
    USE SIGNAL ;
    PORT
      LAYER M5 ;
        RECT  23.904 29.076 23.928 29.16 ;
    END
  END lp_ctx_t[4]
  PIN lp_ctx_t[5]
    DIRECTION INPUT ;
    USE SIGNAL ;
    PORT
      LAYER M5 ;
        RECT  24.048 29.076 24.072 29.16 ;
    END
  END lp_ctx_t[5]
  PIN lp_ctx_t[6]
    DIRECTION INPUT ;
    USE SIGNAL ;
    PORT
      LAYER M5 ;
        RECT  24.192 29.076 24.216 29.16 ;
    END
  END lp_ctx_t[6]
  PIN lp_ctx_t[7]
    DIRECTION INPUT ;
    USE SIGNAL ;
    PORT
      LAYER M5 ;
        RECT  24.336 29.076 24.36 29.16 ;
    END
  END lp_ctx_t[7]
  PIN lp_ctx_t[8]
    DIRECTION INPUT ;
    USE SIGNAL ;
    PORT
      LAYER M5 ;
        RECT  24.48 29.076 24.504 29.16 ;
    END
  END lp_ctx_t[8]
  PIN lp_ctx_t[9]
    DIRECTION INPUT ;
    USE SIGNAL ;
    PORT
      LAYER M5 ;
        RECT  24.624 29.076 24.648 29.16 ;
    END
  END lp_ctx_t[9]
  PIN lp_layer[0]
    DIRECTION INPUT ;
    USE SIGNAL ;
    PORT
      LAYER M5 ;
        RECT  25.344 29.076 25.368 29.16 ;
    END
  END lp_layer[0]
  PIN lp_layer[1]
    DIRECTION INPUT ;
    USE SIGNAL ;
    PORT
      LAYER M5 ;
        RECT  25.488 29.076 25.512 29.16 ;
    END
  END lp_layer[1]
  PIN lp_layer[2]
    DIRECTION INPUT ;
    USE SIGNAL ;
    PORT
      LAYER M5 ;
        RECT  25.632 29.076 25.656 29.16 ;
    END
  END lp_layer[2]
  PIN lp_layer[3]
    DIRECTION INPUT ;
    USE SIGNAL ;
    PORT
      LAYER M5 ;
        RECT  25.776 29.076 25.8 29.16 ;
    END
  END lp_layer[3]
  PIN lp_layer[4]
    DIRECTION INPUT ;
    USE SIGNAL ;
    PORT
      LAYER M5 ;
        RECT  25.92 29.076 25.944 29.16 ;
    END
  END lp_layer[4]
  PIN lp_layer[5]
    DIRECTION INPUT ;
    USE SIGNAL ;
    PORT
      LAYER M5 ;
        RECT  16.848 29.076 16.872 29.16 ;
    END
  END lp_layer[5]
  PIN lp_run
    DIRECTION INPUT ;
    USE SIGNAL ;
    PORT
      LAYER M5 ;
        RECT  16.992 29.076 17.016 29.16 ;
    END
  END lp_run
  PIN prg_q_beat[0]
    DIRECTION INPUT ;
    USE SIGNAL ;
    PORT
      LAYER M5 ;
        RECT  17.136 29.076 17.16 29.16 ;
    END
  END prg_q_beat[0]
  PIN prg_q_beat[1]
    DIRECTION INPUT ;
    USE SIGNAL ;
    PORT
      LAYER M5 ;
        RECT  17.28 29.076 17.304 29.16 ;
    END
  END prg_q_beat[1]
  PIN prg_q_beat[2]
    DIRECTION INPUT ;
    USE SIGNAL ;
    PORT
      LAYER M5 ;
        RECT  17.424 29.076 17.448 29.16 ;
    END
  END prg_q_beat[2]
  PIN prg_q_beat[3]
    DIRECTION INPUT ;
    USE SIGNAL ;
    PORT
      LAYER M5 ;
        RECT  17.568 29.076 17.592 29.16 ;
    END
  END prg_q_beat[3]
  PIN prg_q_beat[4]
    DIRECTION INPUT ;
    USE SIGNAL ;
    PORT
      LAYER M5 ;
        RECT  17.712 29.076 17.736 29.16 ;
    END
  END prg_q_beat[4]
  PIN prg_q_v
    DIRECTION INPUT ;
    USE SIGNAL ;
    PORT
      LAYER M5 ;
        RECT  17.856 29.076 17.88 29.16 ;
    END
  END prg_q_v
  PIN prg_req_pos[0]
    DIRECTION INPUT ;
    USE SIGNAL ;
    PORT
      LAYER M5 ;
        RECT  18 29.076 18.024 29.16 ;
    END
  END prg_req_pos[0]
  PIN prg_req_pos[10]
    DIRECTION INPUT ;
    USE SIGNAL ;
    PORT
      LAYER M5 ;
        RECT  19.44 29.076 19.464 29.16 ;
    END
  END prg_req_pos[10]
  PIN prg_req_pos[11]
    DIRECTION INPUT ;
    USE SIGNAL ;
    PORT
      LAYER M5 ;
        RECT  19.584 29.076 19.608 29.16 ;
    END
  END prg_req_pos[11]
  PIN prg_req_pos[12]
    DIRECTION INPUT ;
    USE SIGNAL ;
    PORT
      LAYER M5 ;
        RECT  19.728 29.076 19.752 29.16 ;
    END
  END prg_req_pos[12]
  PIN prg_req_pos[13]
    DIRECTION INPUT ;
    USE SIGNAL ;
    PORT
      LAYER M5 ;
        RECT  19.872 29.076 19.896 29.16 ;
    END
  END prg_req_pos[13]
  PIN prg_req_pos[14]
    DIRECTION INPUT ;
    USE SIGNAL ;
    PORT
      LAYER M5 ;
        RECT  20.016 29.076 20.04 29.16 ;
    END
  END prg_req_pos[14]
  PIN prg_req_pos[15]
    DIRECTION INPUT ;
    USE SIGNAL ;
    PORT
      LAYER M5 ;
        RECT  20.16 29.076 20.184 29.16 ;
    END
  END prg_req_pos[15]
  PIN prg_req_pos[16]
    DIRECTION INPUT ;
    USE SIGNAL ;
    PORT
      LAYER M5 ;
        RECT  20.304 29.076 20.328 29.16 ;
    END
  END prg_req_pos[16]
  PIN prg_req_pos[17]
    DIRECTION INPUT ;
    USE SIGNAL ;
    PORT
      LAYER M5 ;
        RECT  20.448 29.076 20.472 29.16 ;
    END
  END prg_req_pos[17]
  PIN prg_req_pos[1]
    DIRECTION INPUT ;
    USE SIGNAL ;
    PORT
      LAYER M5 ;
        RECT  18.144 29.076 18.168 29.16 ;
    END
  END prg_req_pos[1]
  PIN prg_req_pos[2]
    DIRECTION INPUT ;
    USE SIGNAL ;
    PORT
      LAYER M5 ;
        RECT  18.288 29.076 18.312 29.16 ;
    END
  END prg_req_pos[2]
  PIN prg_req_pos[3]
    DIRECTION INPUT ;
    USE SIGNAL ;
    PORT
      LAYER M5 ;
        RECT  18.432 29.076 18.456 29.16 ;
    END
  END prg_req_pos[3]
  PIN prg_req_pos[4]
    DIRECTION INPUT ;
    USE SIGNAL ;
    PORT
      LAYER M5 ;
        RECT  18.576 29.076 18.6 29.16 ;
    END
  END prg_req_pos[4]
  PIN prg_req_pos[5]
    DIRECTION INPUT ;
    USE SIGNAL ;
    PORT
      LAYER M5 ;
        RECT  18.72 29.076 18.744 29.16 ;
    END
  END prg_req_pos[5]
  PIN prg_req_pos[6]
    DIRECTION INPUT ;
    USE SIGNAL ;
    PORT
      LAYER M5 ;
        RECT  18.864 29.076 18.888 29.16 ;
    END
  END prg_req_pos[6]
  PIN prg_req_pos[7]
    DIRECTION INPUT ;
    USE SIGNAL ;
    PORT
      LAYER M5 ;
        RECT  19.008 29.076 19.032 29.16 ;
    END
  END prg_req_pos[7]
  PIN prg_req_pos[8]
    DIRECTION INPUT ;
    USE SIGNAL ;
    PORT
      LAYER M5 ;
        RECT  19.152 29.076 19.176 29.16 ;
    END
  END prg_req_pos[8]
  PIN prg_req_pos[9]
    DIRECTION INPUT ;
    USE SIGNAL ;
    PORT
      LAYER M5 ;
        RECT  19.296 29.076 19.32 29.16 ;
    END
  END prg_req_pos[9]
  PIN prg_req_v
    DIRECTION INPUT ;
    USE SIGNAL ;
    PORT
      LAYER M5 ;
        RECT  20.592 29.076 20.616 29.16 ;
    END
  END prg_req_v
  PIN rst_n
    DIRECTION INPUT ;
    USE SIGNAL ;
    PORT
      LAYER M5 ;
        RECT  22.032 0 22.056 0.084 ;
    END
  END rst_n
  PIN s_kidx[0]
    DIRECTION OUTPUT ;
    USE SIGNAL ;
    PORT
      LAYER M5 ;
        RECT  20.736 29.076 20.76 29.16 ;
    END
  END s_kidx[0]
  PIN s_kidx[1]
    DIRECTION OUTPUT ;
    USE SIGNAL ;
    PORT
      LAYER M5 ;
        RECT  20.88 29.076 20.904 29.16 ;
    END
  END s_kidx[1]
  PIN s_kidx[2]
    DIRECTION OUTPUT ;
    USE SIGNAL ;
    PORT
      LAYER M5 ;
        RECT  21.024 29.076 21.048 29.16 ;
    END
  END s_kidx[2]
  PIN s_kpop
    DIRECTION OUTPUT ;
    USE SIGNAL ;
    PORT
      LAYER M5 ;
        RECT  21.168 29.076 21.192 29.16 ;
    END
  END s_kpop
  PIN s_kwgo
    DIRECTION OUTPUT ;
    USE SIGNAL ;
    PORT
      LAYER M5 ;
        RECT  21.312 29.076 21.336 29.16 ;
    END
  END s_kwgo
  PIN s_kwn[0]
    DIRECTION OUTPUT ;
    USE SIGNAL ;
    PORT
      LAYER M5 ;
        RECT  5.472 29.076 5.496 29.16 ;
    END
  END s_kwn[0]
  PIN s_kwn[1]
    DIRECTION OUTPUT ;
    USE SIGNAL ;
    PORT
      LAYER M5 ;
        RECT  5.616 29.076 5.64 29.16 ;
    END
  END s_kwn[1]
  PIN s_qpop
    DIRECTION OUTPUT ;
    USE SIGNAL ;
    PORT
      LAYER M5 ;
        RECT  5.76 29.076 5.784 29.16 ;
    END
  END s_qpop
  PIN svc_h[0]
    DIRECTION INPUT ;
    USE SIGNAL ;
    PORT
      LAYER M5 ;
        RECT  22.176 0 22.2 0.084 ;
    END
  END svc_h[0]
  PIN svc_h[10]
    DIRECTION INPUT ;
    USE SIGNAL ;
    PORT
      LAYER M5 ;
        RECT  23.616 0 23.64 0.084 ;
    END
  END svc_h[10]
  PIN svc_h[11]
    DIRECTION INPUT ;
    USE SIGNAL ;
    PORT
      LAYER M5 ;
        RECT  58.32 0 58.344 0.084 ;
    END
  END svc_h[11]
  PIN svc_h[12]
    DIRECTION INPUT ;
    USE SIGNAL ;
    PORT
      LAYER M5 ;
        RECT  58.464 0 58.488 0.084 ;
    END
  END svc_h[12]
  PIN svc_h[13]
    DIRECTION INPUT ;
    USE SIGNAL ;
    PORT
      LAYER M5 ;
        RECT  58.608 0 58.632 0.084 ;
    END
  END svc_h[13]
  PIN svc_h[14]
    DIRECTION INPUT ;
    USE SIGNAL ;
    PORT
      LAYER M5 ;
        RECT  58.752 0 58.776 0.084 ;
    END
  END svc_h[14]
  PIN svc_h[15]
    DIRECTION INPUT ;
    USE SIGNAL ;
    PORT
      LAYER M5 ;
        RECT  58.896 0 58.92 0.084 ;
    END
  END svc_h[15]
  PIN svc_h[16]
    DIRECTION INPUT ;
    USE SIGNAL ;
    PORT
      LAYER M5 ;
        RECT  59.04 0 59.064 0.084 ;
    END
  END svc_h[16]
  PIN svc_h[17]
    DIRECTION INPUT ;
    USE SIGNAL ;
    PORT
      LAYER M5 ;
        RECT  59.184 0 59.208 0.084 ;
    END
  END svc_h[17]
  PIN svc_h[18]
    DIRECTION INPUT ;
    USE SIGNAL ;
    PORT
      LAYER M5 ;
        RECT  59.328 0 59.352 0.084 ;
    END
  END svc_h[18]
  PIN svc_h[19]
    DIRECTION INPUT ;
    USE SIGNAL ;
    PORT
      LAYER M5 ;
        RECT  59.472 0 59.496 0.084 ;
    END
  END svc_h[19]
  PIN svc_h[1]
    DIRECTION INPUT ;
    USE SIGNAL ;
    PORT
      LAYER M5 ;
        RECT  22.32 0 22.344 0.084 ;
    END
  END svc_h[1]
  PIN svc_h[20]
    DIRECTION INPUT ;
    USE SIGNAL ;
    PORT
      LAYER M5 ;
        RECT  59.616 0 59.64 0.084 ;
    END
  END svc_h[20]
  PIN svc_h[21]
    DIRECTION INPUT ;
    USE SIGNAL ;
    PORT
      LAYER M5 ;
        RECT  59.76 0 59.784 0.084 ;
    END
  END svc_h[21]
  PIN svc_h[22]
    DIRECTION INPUT ;
    USE SIGNAL ;
    PORT
      LAYER M5 ;
        RECT  59.904 0 59.928 0.084 ;
    END
  END svc_h[22]
  PIN svc_h[23]
    DIRECTION INPUT ;
    USE SIGNAL ;
    PORT
      LAYER M5 ;
        RECT  60.048 0 60.072 0.084 ;
    END
  END svc_h[23]
  PIN svc_h[24]
    DIRECTION INPUT ;
    USE SIGNAL ;
    PORT
      LAYER M5 ;
        RECT  60.192 0 60.216 0.084 ;
    END
  END svc_h[24]
  PIN svc_h[25]
    DIRECTION INPUT ;
    USE SIGNAL ;
    PORT
      LAYER M5 ;
        RECT  60.336 0 60.36 0.084 ;
    END
  END svc_h[25]
  PIN svc_h[26]
    DIRECTION INPUT ;
    USE SIGNAL ;
    PORT
      LAYER M5 ;
        RECT  60.48 0 60.504 0.084 ;
    END
  END svc_h[26]
  PIN svc_h[27]
    DIRECTION INPUT ;
    USE SIGNAL ;
    PORT
      LAYER M5 ;
        RECT  60.624 0 60.648 0.084 ;
    END
  END svc_h[27]
  PIN svc_h[28]
    DIRECTION INPUT ;
    USE SIGNAL ;
    PORT
      LAYER M5 ;
        RECT  60.768 0 60.792 0.084 ;
    END
  END svc_h[28]
  PIN svc_h[29]
    DIRECTION INPUT ;
    USE SIGNAL ;
    PORT
      LAYER M5 ;
        RECT  60.912 0 60.936 0.084 ;
    END
  END svc_h[29]
  PIN svc_h[2]
    DIRECTION INPUT ;
    USE SIGNAL ;
    PORT
      LAYER M5 ;
        RECT  22.464 0 22.488 0.084 ;
    END
  END svc_h[2]
  PIN svc_h[30]
    DIRECTION INPUT ;
    USE SIGNAL ;
    PORT
      LAYER M5 ;
        RECT  61.056 0 61.08 0.084 ;
    END
  END svc_h[30]
  PIN svc_h[31]
    DIRECTION INPUT ;
    USE SIGNAL ;
    PORT
      LAYER M5 ;
        RECT  61.2 0 61.224 0.084 ;
    END
  END svc_h[31]
  PIN svc_h[32]
    DIRECTION INPUT ;
    USE SIGNAL ;
    PORT
      LAYER M5 ;
        RECT  61.344 0 61.368 0.084 ;
    END
  END svc_h[32]
  PIN svc_h[33]
    DIRECTION INPUT ;
    USE SIGNAL ;
    PORT
      LAYER M5 ;
        RECT  61.488 0 61.512 0.084 ;
    END
  END svc_h[33]
  PIN svc_h[34]
    DIRECTION INPUT ;
    USE SIGNAL ;
    PORT
      LAYER M5 ;
        RECT  61.632 0 61.656 0.084 ;
    END
  END svc_h[34]
  PIN svc_h[35]
    DIRECTION INPUT ;
    USE SIGNAL ;
    PORT
      LAYER M5 ;
        RECT  61.776 0 61.8 0.084 ;
    END
  END svc_h[35]
  PIN svc_h[36]
    DIRECTION INPUT ;
    USE SIGNAL ;
    PORT
      LAYER M5 ;
        RECT  61.92 0 61.944 0.084 ;
    END
  END svc_h[36]
  PIN svc_h[37]
    DIRECTION INPUT ;
    USE SIGNAL ;
    PORT
      LAYER M5 ;
        RECT  62.064 0 62.088 0.084 ;
    END
  END svc_h[37]
  PIN svc_h[38]
    DIRECTION INPUT ;
    USE SIGNAL ;
    PORT
      LAYER M5 ;
        RECT  62.208 0 62.232 0.084 ;
    END
  END svc_h[38]
  PIN svc_h[39]
    DIRECTION INPUT ;
    USE SIGNAL ;
    PORT
      LAYER M5 ;
        RECT  62.352 0 62.376 0.084 ;
    END
  END svc_h[39]
  PIN svc_h[3]
    DIRECTION INPUT ;
    USE SIGNAL ;
    PORT
      LAYER M5 ;
        RECT  22.608 0 22.632 0.084 ;
    END
  END svc_h[3]
  PIN svc_h[40]
    DIRECTION INPUT ;
    USE SIGNAL ;
    PORT
      LAYER M5 ;
        RECT  62.496 0 62.52 0.084 ;
    END
  END svc_h[40]
  PIN svc_h[41]
    DIRECTION INPUT ;
    USE SIGNAL ;
    PORT
      LAYER M5 ;
        RECT  62.64 0 62.664 0.084 ;
    END
  END svc_h[41]
  PIN svc_h[42]
    DIRECTION INPUT ;
    USE SIGNAL ;
    PORT
      LAYER M5 ;
        RECT  62.784 0 62.808 0.084 ;
    END
  END svc_h[42]
  PIN svc_h[43]
    DIRECTION INPUT ;
    USE SIGNAL ;
    PORT
      LAYER M5 ;
        RECT  47.952 0 47.976 0.084 ;
    END
  END svc_h[43]
  PIN svc_h[44]
    DIRECTION INPUT ;
    USE SIGNAL ;
    PORT
      LAYER M5 ;
        RECT  48.096 0 48.12 0.084 ;
    END
  END svc_h[44]
  PIN svc_h[45]
    DIRECTION INPUT ;
    USE SIGNAL ;
    PORT
      LAYER M5 ;
        RECT  48.24 0 48.264 0.084 ;
    END
  END svc_h[45]
  PIN svc_h[46]
    DIRECTION INPUT ;
    USE SIGNAL ;
    PORT
      LAYER M5 ;
        RECT  48.384 0 48.408 0.084 ;
    END
  END svc_h[46]
  PIN svc_h[47]
    DIRECTION INPUT ;
    USE SIGNAL ;
    PORT
      LAYER M5 ;
        RECT  48.528 0 48.552 0.084 ;
    END
  END svc_h[47]
  PIN svc_h[48]
    DIRECTION INPUT ;
    USE SIGNAL ;
    PORT
      LAYER M5 ;
        RECT  48.672 0 48.696 0.084 ;
    END
  END svc_h[48]
  PIN svc_h[49]
    DIRECTION INPUT ;
    USE SIGNAL ;
    PORT
      LAYER M5 ;
        RECT  48.816 0 48.84 0.084 ;
    END
  END svc_h[49]
  PIN svc_h[4]
    DIRECTION INPUT ;
    USE SIGNAL ;
    PORT
      LAYER M5 ;
        RECT  22.752 0 22.776 0.084 ;
    END
  END svc_h[4]
  PIN svc_h[50]
    DIRECTION INPUT ;
    USE SIGNAL ;
    PORT
      LAYER M5 ;
        RECT  48.96 0 48.984 0.084 ;
    END
  END svc_h[50]
  PIN svc_h[51]
    DIRECTION INPUT ;
    USE SIGNAL ;
    PORT
      LAYER M5 ;
        RECT  49.104 0 49.128 0.084 ;
    END
  END svc_h[51]
  PIN svc_h[52]
    DIRECTION INPUT ;
    USE SIGNAL ;
    PORT
      LAYER M5 ;
        RECT  49.248 0 49.272 0.084 ;
    END
  END svc_h[52]
  PIN svc_h[53]
    DIRECTION INPUT ;
    USE SIGNAL ;
    PORT
      LAYER M5 ;
        RECT  49.392 0 49.416 0.084 ;
    END
  END svc_h[53]
  PIN svc_h[54]
    DIRECTION INPUT ;
    USE SIGNAL ;
    PORT
      LAYER M5 ;
        RECT  49.536 0 49.56 0.084 ;
    END
  END svc_h[54]
  PIN svc_h[55]
    DIRECTION INPUT ;
    USE SIGNAL ;
    PORT
      LAYER M5 ;
        RECT  49.68 0 49.704 0.084 ;
    END
  END svc_h[55]
  PIN svc_h[56]
    DIRECTION INPUT ;
    USE SIGNAL ;
    PORT
      LAYER M5 ;
        RECT  49.824 0 49.848 0.084 ;
    END
  END svc_h[56]
  PIN svc_h[57]
    DIRECTION INPUT ;
    USE SIGNAL ;
    PORT
      LAYER M5 ;
        RECT  49.968 0 49.992 0.084 ;
    END
  END svc_h[57]
  PIN svc_h[58]
    DIRECTION INPUT ;
    USE SIGNAL ;
    PORT
      LAYER M5 ;
        RECT  50.112 0 50.136 0.084 ;
    END
  END svc_h[58]
  PIN svc_h[59]
    DIRECTION INPUT ;
    USE SIGNAL ;
    PORT
      LAYER M5 ;
        RECT  50.256 0 50.28 0.084 ;
    END
  END svc_h[59]
  PIN svc_h[5]
    DIRECTION INPUT ;
    USE SIGNAL ;
    PORT
      LAYER M5 ;
        RECT  22.896 0 22.92 0.084 ;
    END
  END svc_h[5]
  PIN svc_h[60]
    DIRECTION INPUT ;
    USE SIGNAL ;
    PORT
      LAYER M5 ;
        RECT  50.4 0 50.424 0.084 ;
    END
  END svc_h[60]
  PIN svc_h[61]
    DIRECTION INPUT ;
    USE SIGNAL ;
    PORT
      LAYER M5 ;
        RECT  50.544 0 50.568 0.084 ;
    END
  END svc_h[61]
  PIN svc_h[62]
    DIRECTION INPUT ;
    USE SIGNAL ;
    PORT
      LAYER M5 ;
        RECT  50.688 0 50.712 0.084 ;
    END
  END svc_h[62]
  PIN svc_h[63]
    DIRECTION INPUT ;
    USE SIGNAL ;
    PORT
      LAYER M5 ;
        RECT  50.832 0 50.856 0.084 ;
    END
  END svc_h[63]
  PIN svc_h[64]
    DIRECTION INPUT ;
    USE SIGNAL ;
    PORT
      LAYER M5 ;
        RECT  50.976 0 51 0.084 ;
    END
  END svc_h[64]
  PIN svc_h[65]
    DIRECTION INPUT ;
    USE SIGNAL ;
    PORT
      LAYER M5 ;
        RECT  51.12 0 51.144 0.084 ;
    END
  END svc_h[65]
  PIN svc_h[66]
    DIRECTION INPUT ;
    USE SIGNAL ;
    PORT
      LAYER M5 ;
        RECT  51.264 0 51.288 0.084 ;
    END
  END svc_h[66]
  PIN svc_h[67]
    DIRECTION INPUT ;
    USE SIGNAL ;
    PORT
      LAYER M5 ;
        RECT  51.408 0 51.432 0.084 ;
    END
  END svc_h[67]
  PIN svc_h[68]
    DIRECTION INPUT ;
    USE SIGNAL ;
    PORT
      LAYER M5 ;
        RECT  51.552 0 51.576 0.084 ;
    END
  END svc_h[68]
  PIN svc_h[69]
    DIRECTION INPUT ;
    USE SIGNAL ;
    PORT
      LAYER M5 ;
        RECT  51.696 0 51.72 0.084 ;
    END
  END svc_h[69]
  PIN svc_h[6]
    DIRECTION INPUT ;
    USE SIGNAL ;
    PORT
      LAYER M5 ;
        RECT  23.04 0 23.064 0.084 ;
    END
  END svc_h[6]
  PIN svc_h[70]
    DIRECTION INPUT ;
    USE SIGNAL ;
    PORT
      LAYER M5 ;
        RECT  51.84 0 51.864 0.084 ;
    END
  END svc_h[70]
  PIN svc_h[71]
    DIRECTION INPUT ;
    USE SIGNAL ;
    PORT
      LAYER M5 ;
        RECT  51.984 0 52.008 0.084 ;
    END
  END svc_h[71]
  PIN svc_h[72]
    DIRECTION INPUT ;
    USE SIGNAL ;
    PORT
      LAYER M5 ;
        RECT  52.128 0 52.152 0.084 ;
    END
  END svc_h[72]
  PIN svc_h[73]
    DIRECTION INPUT ;
    USE SIGNAL ;
    PORT
      LAYER M5 ;
        RECT  52.272 0 52.296 0.084 ;
    END
  END svc_h[73]
  PIN svc_h[74]
    DIRECTION INPUT ;
    USE SIGNAL ;
    PORT
      LAYER M5 ;
        RECT  52.416 0 52.44 0.084 ;
    END
  END svc_h[74]
  PIN svc_h[75]
    DIRECTION INPUT ;
    USE SIGNAL ;
    PORT
      LAYER M5 ;
        RECT  43.344 0 43.368 0.084 ;
    END
  END svc_h[75]
  PIN svc_h[76]
    DIRECTION INPUT ;
    USE SIGNAL ;
    PORT
      LAYER M5 ;
        RECT  43.488 0 43.512 0.084 ;
    END
  END svc_h[76]
  PIN svc_h[77]
    DIRECTION INPUT ;
    USE SIGNAL ;
    PORT
      LAYER M5 ;
        RECT  43.632 0 43.656 0.084 ;
    END
  END svc_h[77]
  PIN svc_h[78]
    DIRECTION INPUT ;
    USE SIGNAL ;
    PORT
      LAYER M5 ;
        RECT  43.776 0 43.8 0.084 ;
    END
  END svc_h[78]
  PIN svc_h[79]
    DIRECTION INPUT ;
    USE SIGNAL ;
    PORT
      LAYER M5 ;
        RECT  43.92 0 43.944 0.084 ;
    END
  END svc_h[79]
  PIN svc_h[7]
    DIRECTION INPUT ;
    USE SIGNAL ;
    PORT
      LAYER M5 ;
        RECT  23.184 0 23.208 0.084 ;
    END
  END svc_h[7]
  PIN svc_h[80]
    DIRECTION INPUT ;
    USE SIGNAL ;
    PORT
      LAYER M5 ;
        RECT  44.064 0 44.088 0.084 ;
    END
  END svc_h[80]
  PIN svc_h[81]
    DIRECTION INPUT ;
    USE SIGNAL ;
    PORT
      LAYER M5 ;
        RECT  44.208 0 44.232 0.084 ;
    END
  END svc_h[81]
  PIN svc_h[82]
    DIRECTION INPUT ;
    USE SIGNAL ;
    PORT
      LAYER M5 ;
        RECT  44.352 0 44.376 0.084 ;
    END
  END svc_h[82]
  PIN svc_h[83]
    DIRECTION INPUT ;
    USE SIGNAL ;
    PORT
      LAYER M5 ;
        RECT  44.496 0 44.52 0.084 ;
    END
  END svc_h[83]
  PIN svc_h[84]
    DIRECTION INPUT ;
    USE SIGNAL ;
    PORT
      LAYER M5 ;
        RECT  44.64 0 44.664 0.084 ;
    END
  END svc_h[84]
  PIN svc_h[85]
    DIRECTION INPUT ;
    USE SIGNAL ;
    PORT
      LAYER M5 ;
        RECT  44.784 0 44.808 0.084 ;
    END
  END svc_h[85]
  PIN svc_h[86]
    DIRECTION INPUT ;
    USE SIGNAL ;
    PORT
      LAYER M5 ;
        RECT  44.928 0 44.952 0.084 ;
    END
  END svc_h[86]
  PIN svc_h[87]
    DIRECTION INPUT ;
    USE SIGNAL ;
    PORT
      LAYER M5 ;
        RECT  45.072 0 45.096 0.084 ;
    END
  END svc_h[87]
  PIN svc_h[8]
    DIRECTION INPUT ;
    USE SIGNAL ;
    PORT
      LAYER M5 ;
        RECT  23.328 0 23.352 0.084 ;
    END
  END svc_h[8]
  PIN svc_h[9]
    DIRECTION INPUT ;
    USE SIGNAL ;
    PORT
      LAYER M5 ;
        RECT  23.472 0 23.496 0.084 ;
    END
  END svc_h[9]
  PIN tk[0]
    DIRECTION OUTPUT ;
    USE SIGNAL ;
    PORT
      LAYER M5 ;
        RECT  45.216 0 45.24 0.084 ;
    END
  END tk[0]
  PIN tk[10]
    DIRECTION OUTPUT ;
    USE SIGNAL ;
    PORT
      LAYER M5 ;
        RECT  46.656 0 46.68 0.084 ;
    END
  END tk[10]
  PIN tk[11]
    DIRECTION OUTPUT ;
    USE SIGNAL ;
    PORT
      LAYER M5 ;
        RECT  46.8 0 46.824 0.084 ;
    END
  END tk[11]
  PIN tk[12]
    DIRECTION OUTPUT ;
    USE SIGNAL ;
    PORT
      LAYER M5 ;
        RECT  46.944 0 46.968 0.084 ;
    END
  END tk[12]
  PIN tk[13]
    DIRECTION OUTPUT ;
    USE SIGNAL ;
    PORT
      LAYER M5 ;
        RECT  47.088 0 47.112 0.084 ;
    END
  END tk[13]
  PIN tk[14]
    DIRECTION OUTPUT ;
    USE SIGNAL ;
    PORT
      LAYER M5 ;
        RECT  47.232 0 47.256 0.084 ;
    END
  END tk[14]
  PIN tk[15]
    DIRECTION OUTPUT ;
    USE SIGNAL ;
    PORT
      LAYER M5 ;
        RECT  47.376 0 47.4 0.084 ;
    END
  END tk[15]
  PIN tk[16]
    DIRECTION OUTPUT ;
    USE SIGNAL ;
    PORT
      LAYER M5 ;
        RECT  47.52 0 47.544 0.084 ;
    END
  END tk[16]
  PIN tk[17]
    DIRECTION OUTPUT ;
    USE SIGNAL ;
    PORT
      LAYER M5 ;
        RECT  47.664 0 47.688 0.084 ;
    END
  END tk[17]
  PIN tk[18]
    DIRECTION OUTPUT ;
    USE SIGNAL ;
    PORT
      LAYER M5 ;
        RECT  47.808 0 47.832 0.084 ;
    END
  END tk[18]
  PIN tk[19]
    DIRECTION OUTPUT ;
    USE SIGNAL ;
    PORT
      LAYER M5 ;
        RECT  52.56 0 52.584 0.084 ;
    END
  END tk[19]
  PIN tk[1]
    DIRECTION OUTPUT ;
    USE SIGNAL ;
    PORT
      LAYER M5 ;
        RECT  45.36 0 45.384 0.084 ;
    END
  END tk[1]
  PIN tk[20]
    DIRECTION OUTPUT ;
    USE SIGNAL ;
    PORT
      LAYER M5 ;
        RECT  52.704 0 52.728 0.084 ;
    END
  END tk[20]
  PIN tk[21]
    DIRECTION OUTPUT ;
    USE SIGNAL ;
    PORT
      LAYER M5 ;
        RECT  52.848 0 52.872 0.084 ;
    END
  END tk[21]
  PIN tk[22]
    DIRECTION OUTPUT ;
    USE SIGNAL ;
    PORT
      LAYER M5 ;
        RECT  52.992 0 53.016 0.084 ;
    END
  END tk[22]
  PIN tk[23]
    DIRECTION OUTPUT ;
    USE SIGNAL ;
    PORT
      LAYER M5 ;
        RECT  53.136 0 53.16 0.084 ;
    END
  END tk[23]
  PIN tk[24]
    DIRECTION OUTPUT ;
    USE SIGNAL ;
    PORT
      LAYER M5 ;
        RECT  53.28 0 53.304 0.084 ;
    END
  END tk[24]
  PIN tk[25]
    DIRECTION OUTPUT ;
    USE SIGNAL ;
    PORT
      LAYER M5 ;
        RECT  53.424 0 53.448 0.084 ;
    END
  END tk[25]
  PIN tk[26]
    DIRECTION OUTPUT ;
    USE SIGNAL ;
    PORT
      LAYER M5 ;
        RECT  53.568 0 53.592 0.084 ;
    END
  END tk[26]
  PIN tk[27]
    DIRECTION OUTPUT ;
    USE SIGNAL ;
    PORT
      LAYER M5 ;
        RECT  53.712 0 53.736 0.084 ;
    END
  END tk[27]
  PIN tk[28]
    DIRECTION OUTPUT ;
    USE SIGNAL ;
    PORT
      LAYER M5 ;
        RECT  53.856 0 53.88 0.084 ;
    END
  END tk[28]
  PIN tk[29]
    DIRECTION OUTPUT ;
    USE SIGNAL ;
    PORT
      LAYER M5 ;
        RECT  54 0 54.024 0.084 ;
    END
  END tk[29]
  PIN tk[2]
    DIRECTION OUTPUT ;
    USE SIGNAL ;
    PORT
      LAYER M5 ;
        RECT  45.504 0 45.528 0.084 ;
    END
  END tk[2]
  PIN tk[30]
    DIRECTION OUTPUT ;
    USE SIGNAL ;
    PORT
      LAYER M5 ;
        RECT  54.144 0 54.168 0.084 ;
    END
  END tk[30]
  PIN tk[31]
    DIRECTION OUTPUT ;
    USE SIGNAL ;
    PORT
      LAYER M5 ;
        RECT  54.288 0 54.312 0.084 ;
    END
  END tk[31]
  PIN tk[32]
    DIRECTION OUTPUT ;
    USE SIGNAL ;
    PORT
      LAYER M5 ;
        RECT  54.432 0 54.456 0.084 ;
    END
  END tk[32]
  PIN tk[33]
    DIRECTION OUTPUT ;
    USE SIGNAL ;
    PORT
      LAYER M5 ;
        RECT  54.576 0 54.6 0.084 ;
    END
  END tk[33]
  PIN tk[34]
    DIRECTION OUTPUT ;
    USE SIGNAL ;
    PORT
      LAYER M5 ;
        RECT  54.72 0 54.744 0.084 ;
    END
  END tk[34]
  PIN tk[35]
    DIRECTION OUTPUT ;
    USE SIGNAL ;
    PORT
      LAYER M5 ;
        RECT  54.864 0 54.888 0.084 ;
    END
  END tk[35]
  PIN tk[36]
    DIRECTION OUTPUT ;
    USE SIGNAL ;
    PORT
      LAYER M5 ;
        RECT  55.008 0 55.032 0.084 ;
    END
  END tk[36]
  PIN tk[37]
    DIRECTION OUTPUT ;
    USE SIGNAL ;
    PORT
      LAYER M5 ;
        RECT  55.152 0 55.176 0.084 ;
    END
  END tk[37]
  PIN tk[38]
    DIRECTION OUTPUT ;
    USE SIGNAL ;
    PORT
      LAYER M5 ;
        RECT  55.296 0 55.32 0.084 ;
    END
  END tk[38]
  PIN tk[39]
    DIRECTION OUTPUT ;
    USE SIGNAL ;
    PORT
      LAYER M5 ;
        RECT  55.44 0 55.464 0.084 ;
    END
  END tk[39]
  PIN tk[3]
    DIRECTION OUTPUT ;
    USE SIGNAL ;
    PORT
      LAYER M5 ;
        RECT  45.648 0 45.672 0.084 ;
    END
  END tk[3]
  PIN tk[40]
    DIRECTION OUTPUT ;
    USE SIGNAL ;
    PORT
      LAYER M5 ;
        RECT  55.584 0 55.608 0.084 ;
    END
  END tk[40]
  PIN tk[41]
    DIRECTION OUTPUT ;
    USE SIGNAL ;
    PORT
      LAYER M5 ;
        RECT  55.728 0 55.752 0.084 ;
    END
  END tk[41]
  PIN tk[42]
    DIRECTION OUTPUT ;
    USE SIGNAL ;
    PORT
      LAYER M5 ;
        RECT  55.872 0 55.896 0.084 ;
    END
  END tk[42]
  PIN tk[43]
    DIRECTION OUTPUT ;
    USE SIGNAL ;
    PORT
      LAYER M5 ;
        RECT  56.016 0 56.04 0.084 ;
    END
  END tk[43]
  PIN tk[44]
    DIRECTION OUTPUT ;
    USE SIGNAL ;
    PORT
      LAYER M5 ;
        RECT  56.16 0 56.184 0.084 ;
    END
  END tk[44]
  PIN tk[45]
    DIRECTION OUTPUT ;
    USE SIGNAL ;
    PORT
      LAYER M5 ;
        RECT  56.304 0 56.328 0.084 ;
    END
  END tk[45]
  PIN tk[46]
    DIRECTION OUTPUT ;
    USE SIGNAL ;
    PORT
      LAYER M5 ;
        RECT  56.448 0 56.472 0.084 ;
    END
  END tk[46]
  PIN tk[47]
    DIRECTION OUTPUT ;
    USE SIGNAL ;
    PORT
      LAYER M5 ;
        RECT  56.592 0 56.616 0.084 ;
    END
  END tk[47]
  PIN tk[48]
    DIRECTION OUTPUT ;
    USE SIGNAL ;
    PORT
      LAYER M5 ;
        RECT  56.736 0 56.76 0.084 ;
    END
  END tk[48]
  PIN tk[49]
    DIRECTION OUTPUT ;
    USE SIGNAL ;
    PORT
      LAYER M5 ;
        RECT  56.88 0 56.904 0.084 ;
    END
  END tk[49]
  PIN tk[4]
    DIRECTION OUTPUT ;
    USE SIGNAL ;
    PORT
      LAYER M5 ;
        RECT  45.792 0 45.816 0.084 ;
    END
  END tk[4]
  PIN tk[50]
    DIRECTION OUTPUT ;
    USE SIGNAL ;
    PORT
      LAYER M5 ;
        RECT  57.024 0 57.048 0.084 ;
    END
  END tk[50]
  PIN tk[51]
    DIRECTION OUTPUT ;
    USE SIGNAL ;
    PORT
      LAYER M5 ;
        RECT  38.736 0 38.76 0.084 ;
    END
  END tk[51]
  PIN tk[52]
    DIRECTION OUTPUT ;
    USE SIGNAL ;
    PORT
      LAYER M5 ;
        RECT  38.88 0 38.904 0.084 ;
    END
  END tk[52]
  PIN tk[53]
    DIRECTION OUTPUT ;
    USE SIGNAL ;
    PORT
      LAYER M5 ;
        RECT  39.024 0 39.048 0.084 ;
    END
  END tk[53]
  PIN tk[54]
    DIRECTION OUTPUT ;
    USE SIGNAL ;
    PORT
      LAYER M5 ;
        RECT  39.168 0 39.192 0.084 ;
    END
  END tk[54]
  PIN tk[55]
    DIRECTION OUTPUT ;
    USE SIGNAL ;
    PORT
      LAYER M5 ;
        RECT  39.312 0 39.336 0.084 ;
    END
  END tk[55]
  PIN tk[56]
    DIRECTION OUTPUT ;
    USE SIGNAL ;
    PORT
      LAYER M5 ;
        RECT  39.456 0 39.48 0.084 ;
    END
  END tk[56]
  PIN tk[57]
    DIRECTION OUTPUT ;
    USE SIGNAL ;
    PORT
      LAYER M5 ;
        RECT  39.6 0 39.624 0.084 ;
    END
  END tk[57]
  PIN tk[58]
    DIRECTION OUTPUT ;
    USE SIGNAL ;
    PORT
      LAYER M5 ;
        RECT  39.744 0 39.768 0.084 ;
    END
  END tk[58]
  PIN tk[59]
    DIRECTION OUTPUT ;
    USE SIGNAL ;
    PORT
      LAYER M5 ;
        RECT  39.888 0 39.912 0.084 ;
    END
  END tk[59]
  PIN tk[5]
    DIRECTION OUTPUT ;
    USE SIGNAL ;
    PORT
      LAYER M5 ;
        RECT  45.936 0 45.96 0.084 ;
    END
  END tk[5]
  PIN tk[60]
    DIRECTION OUTPUT ;
    USE SIGNAL ;
    PORT
      LAYER M5 ;
        RECT  40.032 0 40.056 0.084 ;
    END
  END tk[60]
  PIN tk[61]
    DIRECTION OUTPUT ;
    USE SIGNAL ;
    PORT
      LAYER M5 ;
        RECT  40.176 0 40.2 0.084 ;
    END
  END tk[61]
  PIN tk[62]
    DIRECTION OUTPUT ;
    USE SIGNAL ;
    PORT
      LAYER M5 ;
        RECT  40.32 0 40.344 0.084 ;
    END
  END tk[62]
  PIN tk[63]
    DIRECTION OUTPUT ;
    USE SIGNAL ;
    PORT
      LAYER M5 ;
        RECT  40.464 0 40.488 0.084 ;
    END
  END tk[63]
  PIN tk[64]
    DIRECTION OUTPUT ;
    USE SIGNAL ;
    PORT
      LAYER M5 ;
        RECT  40.608 0 40.632 0.084 ;
    END
  END tk[64]
  PIN tk[65]
    DIRECTION OUTPUT ;
    USE SIGNAL ;
    PORT
      LAYER M5 ;
        RECT  40.752 0 40.776 0.084 ;
    END
  END tk[65]
  PIN tk[66]
    DIRECTION OUTPUT ;
    USE SIGNAL ;
    PORT
      LAYER M5 ;
        RECT  40.896 0 40.92 0.084 ;
    END
  END tk[66]
  PIN tk[67]
    DIRECTION OUTPUT ;
    USE SIGNAL ;
    PORT
      LAYER M5 ;
        RECT  41.04 0 41.064 0.084 ;
    END
  END tk[67]
  PIN tk[68]
    DIRECTION OUTPUT ;
    USE SIGNAL ;
    PORT
      LAYER M5 ;
        RECT  41.184 0 41.208 0.084 ;
    END
  END tk[68]
  PIN tk[69]
    DIRECTION OUTPUT ;
    USE SIGNAL ;
    PORT
      LAYER M5 ;
        RECT  41.328 0 41.352 0.084 ;
    END
  END tk[69]
  PIN tk[6]
    DIRECTION OUTPUT ;
    USE SIGNAL ;
    PORT
      LAYER M5 ;
        RECT  46.08 0 46.104 0.084 ;
    END
  END tk[6]
  PIN tk[70]
    DIRECTION OUTPUT ;
    USE SIGNAL ;
    PORT
      LAYER M5 ;
        RECT  41.472 0 41.496 0.084 ;
    END
  END tk[70]
  PIN tk[71]
    DIRECTION OUTPUT ;
    USE SIGNAL ;
    PORT
      LAYER M5 ;
        RECT  41.616 0 41.64 0.084 ;
    END
  END tk[71]
  PIN tk[72]
    DIRECTION OUTPUT ;
    USE SIGNAL ;
    PORT
      LAYER M5 ;
        RECT  41.76 0 41.784 0.084 ;
    END
  END tk[72]
  PIN tk[73]
    DIRECTION OUTPUT ;
    USE SIGNAL ;
    PORT
      LAYER M5 ;
        RECT  41.904 0 41.928 0.084 ;
    END
  END tk[73]
  PIN tk[74]
    DIRECTION OUTPUT ;
    USE SIGNAL ;
    PORT
      LAYER M5 ;
        RECT  42.048 0 42.072 0.084 ;
    END
  END tk[74]
  PIN tk[75]
    DIRECTION OUTPUT ;
    USE SIGNAL ;
    PORT
      LAYER M5 ;
        RECT  42.192 0 42.216 0.084 ;
    END
  END tk[75]
  PIN tk[76]
    DIRECTION OUTPUT ;
    USE SIGNAL ;
    PORT
      LAYER M5 ;
        RECT  42.336 0 42.36 0.084 ;
    END
  END tk[76]
  PIN tk[77]
    DIRECTION OUTPUT ;
    USE SIGNAL ;
    PORT
      LAYER M5 ;
        RECT  42.48 0 42.504 0.084 ;
    END
  END tk[77]
  PIN tk[78]
    DIRECTION OUTPUT ;
    USE SIGNAL ;
    PORT
      LAYER M5 ;
        RECT  42.624 0 42.648 0.084 ;
    END
  END tk[78]
  PIN tk[79]
    DIRECTION OUTPUT ;
    USE SIGNAL ;
    PORT
      LAYER M5 ;
        RECT  42.768 0 42.792 0.084 ;
    END
  END tk[79]
  PIN tk[7]
    DIRECTION OUTPUT ;
    USE SIGNAL ;
    PORT
      LAYER M5 ;
        RECT  46.224 0 46.248 0.084 ;
    END
  END tk[7]
  PIN tk[80]
    DIRECTION OUTPUT ;
    USE SIGNAL ;
    PORT
      LAYER M5 ;
        RECT  42.912 0 42.936 0.084 ;
    END
  END tk[80]
  PIN tk[81]
    DIRECTION OUTPUT ;
    USE SIGNAL ;
    PORT
      LAYER M5 ;
        RECT  43.056 0 43.08 0.084 ;
    END
  END tk[81]
  PIN tk[82]
    DIRECTION OUTPUT ;
    USE SIGNAL ;
    PORT
      LAYER M5 ;
        RECT  43.2 0 43.224 0.084 ;
    END
  END tk[82]
  PIN tk[83]
    DIRECTION OUTPUT ;
    USE SIGNAL ;
    PORT
      LAYER M5 ;
        RECT  14.544 0 14.568 0.084 ;
    END
  END tk[83]
  PIN tk[84]
    DIRECTION OUTPUT ;
    USE SIGNAL ;
    PORT
      LAYER M5 ;
        RECT  14.688 0 14.712 0.084 ;
    END
  END tk[84]
  PIN tk[85]
    DIRECTION OUTPUT ;
    USE SIGNAL ;
    PORT
      LAYER M5 ;
        RECT  14.832 0 14.856 0.084 ;
    END
  END tk[85]
  PIN tk[86]
    DIRECTION OUTPUT ;
    USE SIGNAL ;
    PORT
      LAYER M5 ;
        RECT  14.976 0 15 0.084 ;
    END
  END tk[86]
  PIN tk[87]
    DIRECTION OUTPUT ;
    USE SIGNAL ;
    PORT
      LAYER M5 ;
        RECT  15.12 0 15.144 0.084 ;
    END
  END tk[87]
  PIN tk[88]
    DIRECTION OUTPUT ;
    USE SIGNAL ;
    PORT
      LAYER M5 ;
        RECT  15.264 0 15.288 0.084 ;
    END
  END tk[88]
  PIN tk[89]
    DIRECTION OUTPUT ;
    USE SIGNAL ;
    PORT
      LAYER M5 ;
        RECT  15.408 0 15.432 0.084 ;
    END
  END tk[89]
  PIN tk[8]
    DIRECTION OUTPUT ;
    USE SIGNAL ;
    PORT
      LAYER M5 ;
        RECT  46.368 0 46.392 0.084 ;
    END
  END tk[8]
  PIN tk[90]
    DIRECTION OUTPUT ;
    USE SIGNAL ;
    PORT
      LAYER M5 ;
        RECT  15.552 0 15.576 0.084 ;
    END
  END tk[90]
  PIN tk[91]
    DIRECTION OUTPUT ;
    USE SIGNAL ;
    PORT
      LAYER M5 ;
        RECT  15.696 0 15.72 0.084 ;
    END
  END tk[91]
  PIN tk[92]
    DIRECTION OUTPUT ;
    USE SIGNAL ;
    PORT
      LAYER M5 ;
        RECT  15.84 0 15.864 0.084 ;
    END
  END tk[92]
  PIN tk[9]
    DIRECTION OUTPUT ;
    USE SIGNAL ;
    PORT
      LAYER M5 ;
        RECT  46.512 0 46.536 0.084 ;
    END
  END tk[9]
  PIN x_cls[0]
    DIRECTION OUTPUT ;
    USE SIGNAL ;
    PORT
      LAYER M5 ;
        RECT  5.904 29.076 5.928 29.16 ;
    END
  END x_cls[0]
  PIN x_cls[1]
    DIRECTION OUTPUT ;
    USE SIGNAL ;
    PORT
      LAYER M5 ;
        RECT  6.048 29.076 6.072 29.16 ;
    END
  END x_cls[1]
  PIN x_cls[2]
    DIRECTION OUTPUT ;
    USE SIGNAL ;
    PORT
      LAYER M5 ;
        RECT  6.192 29.076 6.216 29.16 ;
    END
  END x_cls[2]
  PIN x_v
    DIRECTION OUTPUT ;
    USE SIGNAL ;
    PORT
      LAYER M5 ;
        RECT  6.336 29.076 6.36 29.16 ;
    END
  END x_v
  PIN VDD
    DIRECTION INOUT ;
    USE POWER ;
    PORT
      LAYER M5 ;
        RECT  61.992 2.151 62.112 27.009 ;
        RECT  59.292 2.151 59.412 27.009 ;
        RECT  56.592 2.151 56.712 27.009 ;
        RECT  53.892 2.151 54.012 27.009 ;
        RECT  51.192 2.151 51.312 27.009 ;
        RECT  48.492 2.151 48.612 27.009 ;
        RECT  45.792 2.151 45.912 27.009 ;
        RECT  43.092 2.151 43.212 27.009 ;
        RECT  40.392 2.151 40.512 27.009 ;
        RECT  37.692 2.151 37.812 27.009 ;
        RECT  34.992 2.151 35.112 27.009 ;
        RECT  32.292 2.151 32.412 27.009 ;
        RECT  29.592 2.151 29.712 27.009 ;
        RECT  26.892 2.151 27.012 27.009 ;
        RECT  24.192 2.151 24.312 27.009 ;
        RECT  21.492 2.151 21.612 27.009 ;
        RECT  18.792 2.151 18.912 27.009 ;
        RECT  16.092 2.151 16.212 27.009 ;
        RECT  13.392 2.151 13.512 27.009 ;
        RECT  10.692 2.151 10.812 27.009 ;
        RECT  7.992 2.151 8.112 27.009 ;
        RECT  5.292 2.151 5.412 27.009 ;
        RECT  2.592 2.151 2.712 27.009 ;
    END
  END VDD
  PIN VSS
    DIRECTION INOUT ;
    USE GROUND ;
    PORT
      LAYER M5 ;
        RECT  61.8 2.137 61.92 27.023 ;
        RECT  59.1 2.137 59.22 27.023 ;
        RECT  56.4 2.137 56.52 27.023 ;
        RECT  53.7 2.137 53.82 27.023 ;
        RECT  51 2.137 51.12 27.023 ;
        RECT  48.3 2.137 48.42 27.023 ;
        RECT  45.6 2.137 45.72 27.023 ;
        RECT  42.9 2.137 43.02 27.023 ;
        RECT  40.2 2.137 40.32 27.023 ;
        RECT  37.5 2.137 37.62 27.023 ;
        RECT  34.8 2.137 34.92 27.023 ;
        RECT  32.1 2.137 32.22 27.023 ;
        RECT  29.4 2.137 29.52 27.023 ;
        RECT  26.7 2.137 26.82 27.023 ;
        RECT  24 2.137 24.12 27.023 ;
        RECT  21.3 2.137 21.42 27.023 ;
        RECT  18.6 2.137 18.72 27.023 ;
        RECT  15.9 2.137 16.02 27.023 ;
        RECT  13.2 2.137 13.32 27.023 ;
        RECT  10.5 2.137 10.62 27.023 ;
        RECT  7.8 2.137 7.92 27.023 ;
        RECT  5.1 2.137 5.22 27.023 ;
        RECT  2.4 2.137 2.52 27.023 ;
    END
  END VSS
  # OT_OBS_CLOSED layer=M5 d_um=1.536 added=160
  OBS
    LAYER RVTN ;
     RECT  2.16 2.16 62.64 2.295 ;
     RECT  2.16 2.565 62.64 2.835 ;
     RECT  2.16 3.105 62.64 3.375 ;
     RECT  2.16 3.645 62.64 3.915 ;
     RECT  2.16 4.185 62.64 4.455 ;
     RECT  2.16 4.725 62.64 4.995 ;
     RECT  2.16 5.265 62.64 5.535 ;
     RECT  2.16 5.805 62.64 6.075 ;
     RECT  2.16 6.345 62.64 6.615 ;
     RECT  2.16 6.885 62.64 7.155 ;
     RECT  2.16 7.425 62.64 7.695 ;
     RECT  2.16 7.965 62.64 8.235 ;
     RECT  2.16 8.505 62.64 8.775 ;
     RECT  2.16 9.045 62.64 9.315 ;
     RECT  2.16 9.585 62.64 9.855 ;
     RECT  2.16 10.125 62.64 10.395 ;
     RECT  2.16 10.665 62.64 10.935 ;
     RECT  2.16 11.205 62.64 11.475 ;
     RECT  2.16 11.745 62.64 12.015 ;
     RECT  2.16 12.285 62.64 12.555 ;
     RECT  2.16 12.825 62.64 13.095 ;
     RECT  2.16 13.365 62.64 13.635 ;
     RECT  2.16 13.905 62.64 14.175 ;
     RECT  2.16 14.445 62.64 14.715 ;
     RECT  2.16 14.985 62.64 15.255 ;
     RECT  2.16 15.525 62.64 15.795 ;
     RECT  2.16 16.065 62.64 16.335 ;
     RECT  2.16 16.605 62.64 16.875 ;
     RECT  2.16 17.145 62.64 17.415 ;
     RECT  2.16 17.685 62.64 17.955 ;
     RECT  2.16 18.225 62.64 18.495 ;
     RECT  2.16 18.765 62.64 19.035 ;
     RECT  2.16 19.305 62.64 19.575 ;
     RECT  2.16 19.845 62.64 20.115 ;
     RECT  2.16 20.385 62.64 20.655 ;
     RECT  2.16 20.925 62.64 21.195 ;
     RECT  2.16 21.465 62.64 21.735 ;
     RECT  2.16 22.005 62.64 22.275 ;
     RECT  2.16 22.545 62.64 22.815 ;
     RECT  2.16 23.085 62.64 23.355 ;
     RECT  2.16 23.625 62.64 23.895 ;
     RECT  2.16 24.165 62.64 24.435 ;
     RECT  2.16 24.705 62.64 24.975 ;
     RECT  2.16 25.245 62.64 25.515 ;
     RECT  2.16 25.785 62.64 26.055 ;
     RECT  2.16 26.325 62.64 26.595 ;
     RECT  2.16 26.865 62.64 27 ;
    LAYER RVTP ;
     RECT  2.16 2.295 62.64 2.565 ;
     RECT  2.16 2.835 62.64 3.105 ;
     RECT  2.16 3.375 62.64 3.645 ;
     RECT  2.16 3.915 62.64 4.185 ;
     RECT  2.16 4.455 62.64 4.725 ;
     RECT  2.16 4.995 62.64 5.265 ;
     RECT  2.16 5.535 62.64 5.805 ;
     RECT  2.16 6.075 62.64 6.345 ;
     RECT  2.16 6.615 62.64 6.885 ;
     RECT  2.16 7.155 62.64 7.425 ;
     RECT  2.16 7.695 62.64 7.965 ;
     RECT  2.16 8.235 62.64 8.505 ;
     RECT  2.16 8.775 62.64 9.045 ;
     RECT  2.16 9.315 62.64 9.585 ;
     RECT  2.16 9.855 62.64 10.125 ;
     RECT  2.16 10.395 62.64 10.665 ;
     RECT  2.16 10.935 62.64 11.205 ;
     RECT  2.16 11.475 62.64 11.745 ;
     RECT  2.16 12.015 62.64 12.285 ;
     RECT  2.16 12.555 62.64 12.825 ;
     RECT  2.16 13.095 62.64 13.365 ;
     RECT  2.16 13.635 62.64 13.905 ;
     RECT  2.16 14.175 62.64 14.445 ;
     RECT  2.16 14.715 62.64 14.985 ;
     RECT  2.16 15.255 62.64 15.525 ;
     RECT  2.16 15.795 62.64 16.065 ;
     RECT  2.16 16.335 62.64 16.605 ;
     RECT  2.16 16.875 62.64 17.145 ;
     RECT  2.16 17.415 62.64 17.685 ;
     RECT  2.16 17.955 62.64 18.225 ;
     RECT  2.16 18.495 62.64 18.765 ;
     RECT  2.16 19.035 62.64 19.305 ;
     RECT  2.16 19.575 62.64 19.845 ;
     RECT  2.16 20.115 62.64 20.385 ;
     RECT  2.16 20.655 62.64 20.925 ;
     RECT  2.16 21.195 62.64 21.465 ;
     RECT  2.16 21.735 62.64 22.005 ;
     RECT  2.16 22.275 62.64 22.545 ;
     RECT  2.16 22.815 62.64 23.085 ;
     RECT  2.16 23.355 62.64 23.625 ;
     RECT  2.16 23.895 62.64 24.165 ;
     RECT  2.16 24.435 62.64 24.705 ;
     RECT  2.16 24.975 62.64 25.245 ;
     RECT  2.16 25.515 62.64 25.785 ;
     RECT  2.16 26.055 62.64 26.325 ;
     RECT  2.16 26.595 62.64 26.865 ;
    LAYER M1 ;
     RECT  2.16 2.151 62.64 27.009 ;
    LAYER M2 ;
     RECT  0.103 10.476 0.139 10.494 ;
     RECT  0.103 11.376 0.139 11.394 ;
     RECT  0.103 12.366 0.139 12.384 ;
     RECT  0.103 15.876 0.139 15.894 ;
     RECT  0.139 10.476 0.175 12.384 ;
     RECT  0.103 20.196 0.283 20.214 ;
     RECT  0.283 20.196 0.419 20.34 ;
     RECT  0.139 15.606 0.499 15.894 ;
     RECT  0.103 14.112 0.535 14.13 ;
     RECT  0.499 14.994 0.535 16.164 ;
     RECT  0.175 10.206 2.16 12.384 ;
     RECT  0.535 13.644 2.16 14.13 ;
     RECT  0.535 14.994 2.16 16.434 ;
     RECT  0.419 20.196 2.16 20.214 ;
     RECT  2.16 2.151 31.315 27.009 ;
     RECT  31.315 2.151 33.035 27.054 ;
     RECT  33.035 2.151 37.651 27.009 ;
     RECT  37.651 2.106 38.839 27.009 ;
     RECT  38.839 2.034 39.019 27.009 ;
     RECT  39.523 1.152 39.659 1.17 ;
     RECT  39.019 1.998 39.947 27.009 ;
     RECT  39.947 2.034 40.199 27.009 ;
     RECT  41.071 1.152 41.171 1.17 ;
     RECT  40.199 2.151 42.871 27.009 ;
     RECT  42.871 2.151 43.403 27.054 ;
     RECT  47.047 1.152 48.119 1.17 ;
     RECT  43.403 2.151 55.579 27.009 ;
     RECT  55.579 2.151 56.623 27.054 ;
     RECT  56.623 2.106 57.191 27.054 ;
     RECT  57.811 1.152 58.091 1.17 ;
     RECT  57.191 2.151 58.955 27.054 ;
     RECT  58.955 2.151 60.475 27.009 ;
     RECT  60.475 2.151 60.935 27.054 ;
     RECT  60.935 2.151 62.64 27.009 ;
     RECT  62.64 3.042 62.699 3.06 ;
     RECT  62.64 6.696 62.699 6.714 ;
     RECT  62.64 9.558 62.699 9.576 ;
     RECT  62.64 13.536 63.311 14.742 ;
     RECT  62.64 15.57 63.311 26.514 ;
     RECT  63.311 16.506 63.851 26.514 ;
     RECT  63.311 15.57 63.887 15.588 ;
     RECT  63.851 16.776 63.887 17.442 ;
     RECT  63.851 18.576 63.887 26.424 ;
     RECT  63.311 13.536 63.923 14.544 ;
     RECT  63.887 18.576 63.923 24.93 ;
     RECT  63.923 14.22 63.959 14.544 ;
     RECT  63.923 20.124 63.959 22.104 ;
     RECT  63.959 14.22 63.995 14.238 ;
     RECT  63.959 20.628 63.995 22.104 ;
     RECT  63.923 23.166 63.995 24.93 ;
     RECT  63.995 23.904 64.031 24.93 ;
     RECT  64.031 23.904 64.067 24.264 ;
     RECT  63.887 26.136 64.067 26.424 ;
     RECT  63.995 21.006 64.643 22.104 ;
     RECT  64.643 21.006 64.679 21.222 ;
     RECT  64.643 22.086 64.679 22.104 ;
     RECT  64.067 23.904 64.679 23.922 ;
     RECT  63.887 17.424 64.715 17.442 ;
     RECT  64.067 26.406 64.715 26.424 ;
     RECT  63.923 18.576 64.787 18.594 ;
     RECT  64.679 21.006 64.787 21.024 ;
    LAYER M3 ;
     RECT  14.508 0.091 15.786 0.139 ;
     RECT  20.772 0.091 21.006 0.139 ;
     RECT  21.744 0.091 21.762 0.139 ;
     RECT  45.252 0.091 45.594 0.139 ;
     RECT  53.172 0.091 53.19 0.139 ;
     RECT  57.888 0.091 57.906 0.139 ;
     RECT  38.52 0.091 38.538 0.187 ;
     RECT  57.816 0.139 57.906 0.187 ;
     RECT  47.052 0.091 47.574 0.235 ;
     RECT  53.172 0.139 53.262 0.475 ;
     RECT  38.52 0.187 38.826 0.523 ;
     RECT  39.636 0.091 41.274 0.523 ;
     RECT  47.052 0.235 48.114 0.523 ;
     RECT  52.776 0.475 53.262 0.523 ;
     RECT  54.072 0.091 55.926 0.523 ;
     RECT  57.276 0.187 57.906 0.523 ;
     RECT  58.644 0.091 58.662 0.523 ;
     RECT  20.772 0.139 21.762 0.571 ;
     RECT  38.52 0.523 41.274 0.571 ;
     RECT  43.632 0.091 43.65 0.571 ;
     RECT  54.072 0.523 56.034 0.571 ;
     RECT  19.296 0.091 19.314 1.099 ;
     RECT  54.072 0.571 56.322 1.147 ;
     RECT  57.276 0.523 58.662 1.147 ;
     RECT  46.836 0.523 48.114 1.175 ;
     RECT  38.196 0.571 41.274 1.195 ;
     RECT  42.048 0.091 42.066 1.195 ;
     RECT  14.22 0.139 15.786 1.723 ;
     RECT  19.296 1.099 19.386 1.723 ;
     RECT  20.772 0.571 22.086 1.723 ;
     RECT  23.364 0.571 23.382 1.723 ;
     RECT  38.196 1.195 42.066 1.723 ;
     RECT  43.236 0.571 43.65 1.723 ;
     RECT  44.496 0.091 44.514 1.723 ;
     RECT  45.252 0.139 45.774 1.723 ;
     RECT  46.836 1.175 47.97 1.723 ;
     RECT  52.596 0.523 53.262 1.723 ;
     RECT  54.072 1.147 58.662 1.723 ;
     RECT  61.452 0.523 61.47 1.723 ;
     RECT  50.148 1.723 58.95 1.771 ;
     RECT  59.76 1.723 60.066 1.771 ;
     RECT  61.38 1.723 61.542 1.771 ;
     RECT  38.196 1.723 47.97 2.011 ;
     RECT  61.272 1.771 61.542 2.011 ;
     RECT  62.28 0.523 62.298 2.011 ;
     RECT  38.196 2.011 48.258 2.059 ;
     RECT  49.392 1.723 49.41 2.059 ;
     RECT  38.196 2.059 49.41 2.101 ;
     RECT  14.22 1.723 15.894 2.143 ;
     RECT  18.972 1.723 23.814 2.143 ;
     RECT  24.552 0.091 24.57 2.143 ;
     RECT  37.656 2.101 49.41 2.143 ;
     RECT  18.615 2.143 24.57 2.191 ;
     RECT  32.115 2.143 32.205 2.191 ;
     RECT  34.815 2.143 34.905 2.191 ;
     RECT  37.515 2.143 49.41 2.191 ;
     RECT  50.148 1.771 60.066 2.191 ;
     RECT  61.272 2.011 62.298 2.191 ;
     RECT  14.22 2.143 16.005 2.227 ;
     RECT  17.568 2.191 17.586 2.251 ;
     RECT  14.22 2.227 16.038 2.263 ;
     RECT  33.48 2.191 33.498 2.293 ;
     RECT  34.74 2.191 34.905 2.293 ;
     RECT  26.715 2.143 26.805 2.299 ;
     RECT  26.715 2.299 27.342 2.335 ;
     RECT  31.932 2.191 32.205 2.335 ;
     RECT  33.48 2.293 34.905 2.335 ;
     RECT  18.468 2.191 24.57 2.371 ;
     RECT  29.415 2.143 29.505 2.371 ;
     RECT  31.608 2.335 32.205 2.371 ;
     RECT  33.408 2.335 34.905 2.371 ;
     RECT  36.324 2.335 36.342 2.371 ;
     RECT  2.415 2.143 2.505 2.413 ;
     RECT  5.115 2.143 5.205 2.413 ;
     RECT  7.815 2.143 7.905 2.413 ;
     RECT  10.515 2.143 10.605 2.413 ;
     RECT  13.215 2.143 13.305 2.413 ;
     RECT  31.608 2.371 34.905 2.413 ;
     RECT  17.352 2.251 17.586 2.461 ;
     RECT  18.36 2.371 24.57 2.461 ;
     RECT  25.488 2.371 25.506 2.461 ;
     RECT  26.316 2.335 27.342 2.461 ;
     RECT  14.22 2.263 16.614 2.489 ;
     RECT  17.352 2.461 24.75 2.491 ;
     RECT  25.488 2.461 27.342 2.491 ;
     RECT  17.352 2.491 27.342 2.497 ;
     RECT  29.268 2.371 29.898 2.497 ;
     RECT  31.608 2.413 35.097 2.539 ;
     RECT  14.256 2.489 16.614 2.569 ;
     RECT  17.352 2.497 27.414 2.569 ;
     RECT  36.324 2.371 36.45 2.569 ;
     RECT  28.656 2.497 29.898 2.605 ;
     RECT  30.744 2.299 30.762 2.605 ;
     RECT  36.324 2.569 36.486 2.605 ;
     RECT  14.256 2.569 27.414 2.641 ;
     RECT  28.656 2.605 30.762 2.641 ;
     RECT  31.608 2.539 35.19 2.641 ;
     RECT  36.324 2.605 36.522 2.641 ;
     RECT  37.515 2.191 62.298 2.641 ;
     RECT  14.256 2.641 27.882 2.731 ;
     RECT  28.656 2.641 35.19 2.731 ;
     RECT  14.256 2.731 35.19 2.795 ;
     RECT  36.108 2.641 36.63 2.803 ;
     RECT  37.515 2.641 62.514 2.803 ;
     RECT  35.928 2.803 62.514 2.923 ;
     RECT  35.928 2.923 62.694 3.065 ;
     RECT  14.4 2.795 35.19 3.181 ;
     RECT  35.928 3.065 62.514 3.181 ;
     RECT  14.4 3.181 62.514 3.299 ;
     RECT  14.4 3.299 14.418 4.117 ;
     RECT  15.156 3.299 35.19 4.117 ;
     RECT  35.928 3.299 62.514 4.117 ;
     RECT  14.4 4.117 62.514 4.415 ;
     RECT  14.4 4.415 35.298 4.495 ;
     RECT  14.364 4.495 35.298 4.621 ;
     RECT  13.215 2.413 13.497 4.657 ;
     RECT  14.328 4.621 35.298 4.657 ;
     RECT  36.072 4.415 62.514 4.685 ;
     RECT  13.215 4.657 35.298 4.729 ;
     RECT  13.032 4.729 35.298 4.973 ;
     RECT  27.972 4.973 35.298 5.161 ;
     RECT  36.072 4.685 62.406 5.161 ;
     RECT  13.032 4.973 27.126 5.179 ;
     RECT  12.672 5.179 27.126 5.189 ;
     RECT  12.672 5.189 25.686 5.225 ;
     RECT  27.972 5.161 62.406 5.369 ;
     RECT  12.816 5.225 25.686 5.459 ;
     RECT  26.424 5.189 27.126 5.707 ;
     RECT  27.972 5.369 62.37 5.707 ;
     RECT  26.424 5.707 62.37 6.151 ;
     RECT  26.424 6.151 62.514 6.241 ;
     RECT  26.424 6.241 62.586 6.377 ;
     RECT  13.215 5.459 25.686 6.511 ;
     RECT  26.424 6.377 36.45 6.511 ;
     RECT  37.296 6.377 62.586 6.691 ;
     RECT  13.215 6.511 36.45 6.809 ;
     RECT  13.215 6.809 14.058 6.845 ;
     RECT  13.215 6.845 13.842 7.051 ;
     RECT  13.176 7.051 13.842 7.079 ;
     RECT  14.832 6.809 36.45 7.195 ;
     RECT  37.296 6.691 62.694 7.195 ;
     RECT  14.832 7.195 62.694 7.889 ;
     RECT  13.176 7.079 13.698 7.897 ;
     RECT  14.832 7.889 27.558 7.897 ;
     RECT  13.14 7.897 13.698 7.963 ;
     RECT  12.348 7.897 12.366 7.997 ;
     RECT  13.104 7.963 13.698 8.437 ;
     RECT  14.508 7.897 27.558 8.437 ;
     RECT  28.296 7.889 62.694 8.771 ;
     RECT  13.104 8.437 27.558 8.815 ;
     RECT  28.296 8.771 35.622 8.815 ;
     RECT  13.104 8.815 35.622 9.347 ;
     RECT  36.504 8.771 62.694 9.509 ;
     RECT  23.508 9.347 35.622 9.517 ;
     RECT  36.504 9.509 40.878 9.517 ;
     RECT  41.616 9.509 62.694 9.581 ;
     RECT  41.616 9.581 62.586 9.617 ;
     RECT  13.104 9.347 22.518 9.689 ;
     RECT  23.508 9.517 40.878 9.689 ;
     RECT  41.616 9.617 53.997 9.689 ;
     RECT  10.515 2.413 10.797 9.751 ;
     RECT  41.616 9.689 49.77 9.779 ;
     RECT  54.72 9.617 62.586 9.851 ;
     RECT  10.515 9.751 11.502 9.931 ;
     RECT  12.312 8.041 12.33 9.931 ;
     RECT  60.156 9.851 62.586 9.959 ;
     RECT  47.16 9.779 49.77 10.049 ;
     RECT  50.616 9.689 53.997 10.085 ;
     RECT  60.228 9.959 62.586 10.121 ;
     RECT  10.515 9.931 12.33 10.129 ;
     RECT  10.116 10.129 12.33 10.165 ;
     RECT  13.104 9.689 17.442 10.165 ;
     RECT  10.116 10.165 17.442 10.201 ;
     RECT  54.72 9.851 59.397 10.253 ;
     RECT  9.9 10.201 17.442 10.319 ;
     RECT  54.72 10.253 57.87 10.319 ;
     RECT  58.644 10.253 59.397 10.319 ;
     RECT  54.972 10.319 57.726 10.349 ;
     RECT  60.228 10.121 62.298 10.355 ;
     RECT  47.16 10.049 49.698 10.391 ;
     RECT  0.18 10.201 0.198 10.399 ;
     RECT  47.16 10.391 49.59 10.427 ;
     RECT  2.415 2.413 2.697 10.435 ;
     RECT  23.508 9.689 40.734 10.435 ;
     RECT  41.616 9.779 46.314 10.435 ;
     RECT  50.652 10.085 53.997 10.435 ;
     RECT  49.536 10.427 49.59 10.463 ;
     RECT  55.008 10.349 57.726 10.463 ;
     RECT  0.18 10.399 0.234 10.471 ;
     RECT  18.18 9.689 22.518 10.471 ;
     RECT  23.508 10.435 46.314 10.471 ;
     RECT  49.572 10.463 49.59 10.499 ;
     RECT  2.376 10.435 2.697 10.561 ;
     RECT  47.16 10.427 48.597 10.589 ;
     RECT  50.652 10.435 54.126 10.589 ;
     RECT  55.008 10.463 56.697 10.589 ;
     RECT  47.16 10.589 47.286 10.625 ;
     RECT  52.524 10.589 53.997 10.625 ;
     RECT  55.008 10.589 55.494 10.625 ;
     RECT  57.42 10.463 57.726 10.625 ;
     RECT  2.304 10.561 2.697 10.669 ;
     RECT  55.008 10.625 55.026 10.697 ;
     RECT  58.716 10.319 59.397 10.697 ;
     RECT  60.876 10.355 62.298 10.697 ;
     RECT  2.304 10.669 3.042 10.705 ;
     RECT  3.816 10.435 3.834 10.705 ;
     RECT  17.316 10.319 17.442 10.741 ;
     RECT  18.18 10.471 46.314 10.741 ;
     RECT  52.524 10.625 52.542 10.769 ;
     RECT  57.708 10.625 57.726 10.769 ;
     RECT  47.16 10.625 47.178 10.829 ;
     RECT  7.815 2.413 8.097 10.831 ;
     RECT  2.304 10.705 3.834 10.859 ;
     RECT  60.876 10.697 62.097 10.859 ;
     RECT  17.316 10.741 46.314 10.891 ;
     RECT  0.108 10.471 0.234 10.939 ;
     RECT  9.144 10.831 9.162 10.939 ;
     RECT  7.815 10.831 8.37 10.975 ;
     RECT  9.108 10.939 9.162 10.975 ;
     RECT  9.9 10.319 16.506 10.975 ;
     RECT  60.876 10.859 60.894 11.003 ;
     RECT  2.34 10.859 3.834 11.129 ;
     RECT  17.316 10.891 46.53 11.129 ;
     RECT  7.815 10.975 16.506 11.137 ;
     RECT  17.316 11.129 41.13 11.137 ;
     RECT  7.815 11.137 41.13 11.201 ;
     RECT  6.3 11.011 6.318 11.209 ;
     RECT  7.815 11.201 27.666 11.209 ;
     RECT  6.228 11.209 6.318 11.281 ;
     RECT  7.128 11.209 27.666 11.281 ;
     RECT  2.415 11.129 3.834 11.371 ;
     RECT  6.228 11.281 27.666 11.371 ;
     RECT  48.024 10.589 48.597 11.399 ;
     RECT  5.115 2.413 5.397 11.515 ;
     RECT  6.156 11.371 27.666 11.515 ;
     RECT  41.868 11.129 46.062 11.543 ;
     RECT  2.415 11.371 3.906 11.641 ;
     RECT  0.108 10.939 0.558 11.693 ;
     RECT  2.415 11.641 4.374 11.713 ;
     RECT  5.115 11.515 27.666 11.713 ;
     RECT  28.512 11.201 41.13 11.849 ;
     RECT  41.868 11.543 43.866 11.947 ;
     RECT  44.748 11.543 46.062 12.043 ;
     RECT  44.748 12.043 46.098 12.091 ;
     RECT  46.872 12.019 46.89 12.091 ;
     RECT  0.108 11.693 0.198 12.125 ;
     RECT  2.415 11.713 27.666 12.217 ;
     RECT  2.415 12.217 27.738 12.289 ;
     RECT  2.304 12.289 27.738 12.325 ;
     RECT  28.512 11.849 40.986 12.325 ;
     RECT  44.748 12.091 46.89 12.325 ;
     RECT  44.712 12.325 46.89 12.361 ;
     RECT  2.304 12.325 40.986 12.413 ;
     RECT  44.712 12.361 46.962 12.451 ;
     RECT  2.34 12.413 40.986 12.551 ;
     RECT  0.108 12.125 0.162 12.557 ;
     RECT  21.315 12.551 40.986 12.595 ;
     RECT  41.76 11.947 43.866 12.595 ;
     RECT  21.315 12.595 43.866 12.721 ;
     RECT  44.64 12.451 47.322 12.721 ;
     RECT  56.415 10.589 56.697 12.901 ;
     RECT  21.315 12.721 47.322 13.171 ;
     RECT  48.315 11.399 48.597 13.171 ;
     RECT  0.144 12.557 0.162 13.373 ;
     RECT  2.34 12.551 20.574 13.441 ;
     RECT  21.315 13.171 48.597 13.441 ;
     RECT  2.34 13.441 48.597 13.469 ;
     RECT  2.34 13.469 40.662 13.531 ;
     RECT  61.815 10.859 62.097 13.531 ;
     RECT  61.815 13.531 62.442 13.639 ;
     RECT  0.54 13.639 0.558 13.709 ;
     RECT  2.304 13.531 40.662 13.945 ;
     RECT  61.596 13.639 62.514 13.945 ;
     RECT  2.268 13.945 40.662 13.981 ;
     RECT  41.4 13.469 48.597 13.981 ;
     RECT  63.9 13.531 63.918 13.981 ;
     RECT  41.4 13.981 49.122 14.099 ;
     RECT  59.115 10.697 59.397 14.143 ;
     RECT  41.4 14.099 48.726 14.171 ;
     RECT  1.98 13.981 40.662 14.203 ;
     RECT  41.4 14.171 47.286 14.203 ;
     RECT  59.115 14.143 59.886 14.215 ;
     RECT  61.596 13.945 62.694 14.215 ;
     RECT  63.864 13.981 63.918 14.215 ;
     RECT  59.115 14.215 60.606 14.251 ;
     RECT  61.452 14.215 62.694 14.251 ;
     RECT  48.276 14.171 48.726 14.369 ;
     RECT  0.108 14.107 0.126 14.429 ;
     RECT  1.98 14.203 47.286 14.441 ;
     RECT  1.98 14.441 47.034 14.621 ;
     RECT  58.896 14.251 62.694 14.719 ;
     RECT  63.864 14.215 63.99 14.719 ;
     RECT  58.896 14.719 63.99 14.791 ;
     RECT  58.104 14.791 63.99 14.917 ;
     RECT  51.015 10.589 51.297 15.025 ;
     RECT  55.98 12.901 56.697 15.025 ;
     RECT  54.72 14.485 54.738 15.061 ;
     RECT  55.548 15.025 56.697 15.061 ;
     RECT  55.548 15.061 56.79 15.101 ;
     RECT  0.504 14.989 0.522 15.259 ;
     RECT  55.692 15.101 56.79 15.359 ;
     RECT  1.98 14.621 46.998 15.403 ;
     RECT  50.724 15.025 51.297 15.421 ;
     RECT  57.78 14.917 63.99 15.437 ;
     RECT  48.276 14.369 48.597 15.493 ;
     RECT  1.98 15.403 47.358 15.529 ;
     RECT  49.86 11.947 49.878 15.529 ;
     RECT  50.652 15.421 51.297 15.529 ;
     RECT  1.98 15.529 47.466 15.565 ;
     RECT  48.276 15.493 48.798 15.565 ;
     RECT  57.78 15.437 63.882 15.581 ;
     RECT  0.504 15.259 0.558 15.601 ;
     RECT  55.98 15.359 56.79 15.601 ;
     RECT  57.78 15.581 62.262 15.601 ;
     RECT  1.98 15.565 48.798 15.691 ;
     RECT  54.72 15.061 54.81 15.719 ;
     RECT  49.86 15.529 51.297 15.863 ;
     RECT  63.288 15.581 63.882 15.869 ;
     RECT  0.144 15.601 0.558 15.871 ;
     RECT  1.98 15.691 48.87 15.961 ;
     RECT  1.98 15.961 48.942 15.997 ;
     RECT  53.715 10.625 53.997 16.267 ;
     RECT  54.72 15.719 54.738 16.267 ;
     RECT  53.715 16.267 54.738 16.301 ;
     RECT  53.715 16.301 54.198 16.397 ;
     RECT  63.288 15.869 63.846 16.411 ;
     RECT  0.108 15.871 0.558 16.445 ;
     RECT  53.715 16.397 54.09 16.541 ;
     RECT  49.86 15.863 49.914 16.645 ;
     RECT  50.688 15.863 51.297 16.645 ;
     RECT  1.98 15.997 49.122 16.733 ;
     RECT  63.252 16.411 63.846 16.771 ;
     RECT  0.144 16.445 0.558 16.877 ;
     RECT  49.86 16.645 51.297 16.879 ;
     RECT  49.86 16.879 51.462 16.891 ;
     RECT  2.304 16.733 49.122 16.915 ;
     RECT  49.86 16.891 52.038 16.915 ;
     RECT  55.98 15.601 62.262 16.951 ;
     RECT  63.252 16.771 63.882 16.951 ;
     RECT  0.144 16.877 0.522 17.021 ;
     RECT  0.504 17.021 0.522 17.309 ;
     RECT  64.692 16.699 64.71 17.447 ;
     RECT  55.98 16.951 63.882 17.597 ;
     RECT  55.98 17.597 63.846 17.659 ;
     RECT  53.715 16.541 53.997 17.851 ;
     RECT  2.304 16.915 52.038 17.947 ;
     RECT  53.46 17.851 53.997 17.959 ;
     RECT  2.304 17.947 52.182 18.031 ;
     RECT  53.028 17.959 53.997 18.031 ;
     RECT  55.476 17.659 63.846 18.157 ;
     RECT  2.304 18.031 54.198 18.187 ;
     RECT  55.188 18.157 63.846 18.187 ;
     RECT  2.304 18.187 63.846 19.111 ;
     RECT  2.304 19.111 63.918 19.913 ;
     RECT  63.864 19.913 63.918 20.119 ;
     RECT  0.144 20.011 0.162 20.191 ;
     RECT  0.108 20.191 0.162 20.299 ;
     RECT  63.864 20.119 63.954 20.299 ;
     RECT  64.764 18.571 64.782 20.299 ;
     RECT  0.108 20.299 0.486 20.477 ;
     RECT  2.304 19.913 62.73 20.477 ;
     RECT  63.864 20.299 64.782 20.875 ;
     RECT  0.108 20.477 0.198 20.909 ;
     RECT  63.828 20.875 64.782 21.029 ;
     RECT  0.144 20.909 0.198 21.053 ;
     RECT  63.828 21.029 64.71 21.053 ;
     RECT  63.828 21.053 64.674 21.191 ;
     RECT  63.864 21.191 64.674 21.227 ;
     RECT  0.144 21.053 0.162 21.629 ;
     RECT  63.864 21.227 64.638 21.629 ;
     RECT  63.936 21.629 64.638 22.081 ;
     RECT  2.304 20.477 62.514 22.205 ;
     RECT  63.936 22.081 64.674 22.349 ;
     RECT  63.936 22.349 64.638 22.621 ;
     RECT  63.9 22.621 64.638 22.747 ;
     RECT  0.324 22.603 0.342 22.781 ;
     RECT  63.828 22.747 64.638 22.855 ;
     RECT  2.34 22.205 62.514 23.089 ;
     RECT  63.288 22.855 64.638 23.089 ;
     RECT  2.34 23.089 64.638 23.161 ;
     RECT  2.304 23.161 64.638 23.423 ;
     RECT  2.304 23.423 15.066 23.729 ;
     RECT  0.108 23.755 0.126 23.885 ;
     RECT  15.804 23.423 64.638 23.899 ;
     RECT  2.304 23.729 14.994 24.089 ;
     RECT  15.804 23.899 64.674 24.089 ;
     RECT  15.804 24.089 51.354 24.161 ;
     RECT  52.128 24.089 64.674 24.221 ;
     RECT  52.128 24.221 62.406 24.359 ;
     RECT  52.128 24.359 52.146 24.431 ;
     RECT  15.804 24.161 51.297 24.475 ;
     RECT  2.304 24.089 14.958 24.503 ;
     RECT  52.92 24.359 62.406 24.503 ;
     RECT  15.768 24.475 51.297 24.629 ;
     RECT  47.16 24.629 51.297 24.773 ;
     RECT  15.768 24.629 46.386 24.781 ;
     RECT  2.304 24.503 12.006 24.809 ;
     RECT  2.415 24.809 12.006 24.899 ;
     RECT  47.16 24.773 49.914 24.899 ;
     RECT  47.34 24.899 49.914 24.935 ;
     RECT  53.028 24.503 62.406 24.971 ;
     RECT  4.032 24.899 12.006 25.043 ;
     RECT  15.732 24.781 46.386 25.043 ;
     RECT  50.688 24.773 51.297 25.043 ;
     RECT  53.604 24.971 62.406 25.051 ;
     RECT  2.415 24.899 2.862 25.079 ;
     RECT  15.732 25.043 31.266 25.079 ;
     RECT  4.536 25.043 12.006 25.169 ;
     RECT  32.004 25.043 46.386 25.169 ;
     RECT  47.34 24.935 49.878 25.169 ;
     RECT  32.004 25.169 46.314 25.205 ;
     RECT  53.604 25.051 62.514 25.229 ;
     RECT  47.34 25.169 49.59 25.241 ;
     RECT  9.54 25.169 12.006 25.321 ;
     RECT  12.78 24.503 14.958 25.321 ;
     RECT  15.732 25.079 28.278 25.321 ;
     RECT  47.592 25.241 49.59 25.373 ;
     RECT  4.536 25.169 8.766 25.439 ;
     RECT  47.592 25.373 49.554 25.439 ;
     RECT  9.54 25.321 28.278 25.475 ;
     RECT  9.684 25.475 28.278 25.547 ;
     RECT  47.592 25.439 49.05 25.547 ;
     RECT  5.115 25.439 8.766 25.565 ;
     RECT  47.592 25.547 49.014 25.583 ;
     RECT  29.415 25.079 31.266 25.825 ;
     RECT  32.004 25.205 46.206 25.825 ;
     RECT  63.288 24.221 64.674 25.949 ;
     RECT  29.415 25.825 46.206 26.059 ;
     RECT  29.415 26.059 46.71 26.095 ;
     RECT  47.592 25.583 48.597 26.095 ;
     RECT  10.188 25.547 28.278 26.123 ;
     RECT  10.404 26.123 28.278 26.131 ;
     RECT  29.088 26.095 48.597 26.131 ;
     RECT  10.404 26.131 48.597 26.249 ;
     RECT  5.115 25.565 8.262 26.285 ;
     RECT  44.928 26.249 48.597 26.285 ;
     RECT  10.404 26.249 44.118 26.333 ;
     RECT  63.828 25.949 64.674 26.347 ;
     RECT  53.604 25.229 62.334 26.357 ;
     RECT  51.015 25.043 51.297 26.401 ;
     RECT  10.404 26.333 43.974 26.429 ;
     RECT  53.715 26.357 62.334 26.429 ;
     RECT  63.828 26.347 64.71 26.429 ;
     RECT  5.115 26.285 8.19 26.519 ;
     RECT  10.515 26.429 13.497 26.519 ;
     RECT  14.22 26.429 43.974 26.519 ;
     RECT  53.715 26.429 54.09 26.519 ;
     RECT  63.828 26.429 64.674 26.519 ;
     RECT  63.864 26.519 64.674 26.525 ;
     RECT  42.3 26.519 43.974 26.555 ;
     RECT  14.508 26.519 35.73 26.591 ;
     RECT  45.036 26.285 48.597 26.591 ;
     RECT  50.724 26.401 51.297 26.591 ;
     RECT  5.115 26.519 8.118 26.627 ;
     RECT  10.515 26.519 11.934 26.627 ;
     RECT  28.62 26.591 35.73 26.627 ;
     RECT  39.312 26.519 41.562 26.627 ;
     RECT  55.26 26.429 62.334 26.627 ;
     RECT  10.515 26.627 11.466 26.663 ;
     RECT  14.508 26.591 27.27 26.663 ;
     RECT  36.576 26.519 38.502 26.663 ;
     RECT  39.384 26.627 39.402 26.663 ;
     RECT  42.3 26.555 43.902 26.663 ;
     RECT  45.036 26.591 46.998 26.663 ;
     RECT  63.936 26.525 64.674 26.669 ;
     RECT  5.115 26.627 8.097 26.671 ;
     RECT  5.112 26.671 8.097 26.699 ;
     RECT  13.068 26.519 13.497 26.699 ;
     RECT  40.176 26.627 41.562 26.699 ;
     RECT  2.415 25.079 2.697 26.747 ;
     RECT  7.815 26.699 8.097 26.747 ;
     RECT  10.515 26.663 10.797 26.747 ;
     RECT  13.215 26.699 13.497 26.747 ;
     RECT  45.036 26.663 45.897 26.747 ;
     RECT  48.315 26.591 48.597 26.747 ;
     RECT  51.015 26.591 51.297 26.747 ;
     RECT  53.715 26.519 53.997 26.747 ;
     RECT  36.684 26.663 38.502 26.765 ;
     RECT  5.112 26.699 6.606 26.789 ;
     RECT  14.724 26.663 27.27 26.789 ;
     RECT  28.62 26.627 35.586 26.789 ;
     RECT  36.684 26.765 38.178 26.789 ;
     RECT  40.212 26.699 41.562 26.789 ;
     RECT  42.624 26.663 43.65 26.789 ;
     RECT  45.036 26.747 45.705 26.789 ;
     RECT  46.692 26.663 46.998 26.789 ;
     RECT  55.26 26.627 57.186 26.789 ;
     RECT  57.96 26.627 62.334 26.789 ;
     RECT  63.972 26.669 64.674 26.813 ;
     RECT  5.112 26.789 6.57 26.825 ;
     RECT  14.724 26.789 26.805 26.825 ;
     RECT  31.32 26.789 33.606 26.825 ;
     RECT  40.215 26.789 41.238 26.825 ;
     RECT  15.372 26.825 26.805 26.861 ;
     RECT  34.815 26.789 35.154 26.861 ;
     RECT  37.515 26.789 37.638 26.861 ;
     RECT  41.22 26.825 41.238 26.861 ;
     RECT  42.624 26.789 43.398 26.861 ;
     RECT  55.26 26.789 56.505 26.861 ;
     RECT  58.104 26.789 59.274 26.861 ;
     RECT  60.48 26.789 62.01 26.861 ;
     RECT  31.32 26.825 32.205 26.897 ;
     RECT  60.48 26.861 61.002 26.897 ;
     RECT  58.248 26.861 59.274 26.933 ;
     RECT  15.915 26.861 26.805 26.957 ;
     RECT  61.815 26.861 62.01 26.957 ;
     RECT  29.415 26.789 30.222 26.969 ;
     RECT  2.415 26.747 2.505 27.017 ;
     RECT  5.115 26.825 6.57 27.017 ;
     RECT  7.815 26.747 7.905 27.017 ;
     RECT  10.515 26.747 10.605 27.017 ;
     RECT  13.215 26.747 13.305 27.017 ;
     RECT  15.915 26.957 16.005 27.017 ;
     RECT  16.992 26.957 26.805 27.017 ;
     RECT  29.415 26.969 29.505 27.017 ;
     RECT  32.115 26.897 32.205 27.017 ;
     RECT  34.815 26.861 34.905 27.017 ;
     RECT  37.515 26.861 37.605 27.017 ;
     RECT  40.215 26.825 40.305 27.017 ;
     RECT  45.615 26.789 45.705 27.017 ;
     RECT  48.315 26.747 48.405 27.017 ;
     RECT  51.015 26.747 51.105 27.017 ;
     RECT  53.715 26.747 53.805 27.017 ;
     RECT  55.368 26.861 56.505 27.017 ;
     RECT  58.248 26.933 59.205 27.017 ;
     RECT  61.815 26.957 61.905 27.017 ;
     RECT  31.32 26.897 31.338 27.059 ;
     RECT  33.012 26.825 33.03 27.059 ;
     RECT  42.876 26.861 43.398 27.059 ;
     RECT  58.248 27.017 58.95 27.059 ;
     RECT  60.48 26.897 60.93 27.059 ;
     RECT  55.368 27.017 56.358 27.101 ;
     RECT  58.248 27.059 58.266 27.245 ;
     RECT  16.992 27.017 26.226 27.293 ;
     RECT  16.992 27.293 18.486 27.341 ;
     RECT  19.26 27.293 23.706 27.341 ;
     RECT  24.444 27.293 26.226 27.341 ;
     RECT  5.436 27.017 6.57 27.389 ;
     RECT  63.972 26.813 63.99 27.389 ;
     RECT  5.508 27.389 6.57 27.437 ;
     RECT  55.368 27.101 56.106 27.677 ;
     RECT  55.62 27.677 56.106 27.821 ;
     RECT  5.904 27.437 6.57 27.917 ;
     RECT  19.26 27.341 19.278 27.965 ;
     RECT  18.468 27.341 18.486 28.013 ;
     RECT  55.908 27.821 56.106 28.109 ;
     RECT  56.088 28.109 56.106 28.253 ;
     RECT  22.608 27.341 22.626 28.493 ;
     RECT  5.904 27.917 6.138 28.541 ;
     RECT  20.556 27.341 21.726 28.541 ;
     RECT  20.664 28.541 21.726 28.589 ;
     RECT  21.096 28.589 21.726 28.925 ;
     RECT  21.096 28.925 21.222 29.021 ;
     RECT  21.096 29.021 21.114 29.069 ;
     RECT  24.444 27.341 24.462 29.069 ;
    LAYER M4 ;
     RECT  0.084 10.944 0.097 10.968 ;
     RECT  0.06 10.968 0.097 11.088 ;
     RECT  0.084 11.088 0.097 11.112 ;
     RECT  0.06 11.112 0.097 11.232 ;
     RECT  0.084 11.232 0.097 11.256 ;
     RECT  0.06 11.256 0.097 11.376 ;
     RECT  0.084 11.376 0.097 11.4 ;
     RECT  0.06 11.4 0.097 11.52 ;
     RECT  0.084 11.52 0.097 11.544 ;
     RECT  0.06 11.544 0.097 11.664 ;
     RECT  0.084 11.664 0.097 11.688 ;
     RECT  0.06 11.688 0.097 11.808 ;
     RECT  0.084 11.808 0.097 11.832 ;
     RECT  0.06 11.832 0.097 11.952 ;
     RECT  0.084 11.952 0.097 11.976 ;
     RECT  0.06 11.976 0.097 12.096 ;
     RECT  0.084 12.096 0.097 12.12 ;
     RECT  0.06 12.12 0.097 12.24 ;
     RECT  0.084 12.24 0.097 12.264 ;
     RECT  0.06 12.264 0.097 12.384 ;
     RECT  0.084 12.384 0.097 12.408 ;
     RECT  0.06 12.408 0.097 12.528 ;
     RECT  0.084 12.528 0.097 12.552 ;
     RECT  0.06 12.552 0.097 12.672 ;
     RECT  0.084 12.672 0.097 12.696 ;
     RECT  0.06 12.696 0.097 12.816 ;
     RECT  0.084 12.816 0.097 12.84 ;
     RECT  0.06 12.84 0.097 12.96 ;
     RECT  0.084 12.96 0.097 12.984 ;
     RECT  0.06 12.984 0.097 13.104 ;
     RECT  0.084 13.104 0.097 13.128 ;
     RECT  0.06 13.128 0.097 13.248 ;
     RECT  0.084 13.248 0.097 13.272 ;
     RECT  0.06 13.272 0.097 13.392 ;
     RECT  0.084 13.392 0.097 13.416 ;
     RECT  0.06 13.416 0.097 13.536 ;
     RECT  0.084 13.536 0.097 13.56 ;
     RECT  0.06 13.56 0.097 13.68 ;
     RECT  0.084 13.68 0.097 13.704 ;
     RECT  0.06 13.704 0.097 13.824 ;
     RECT  0.084 13.824 0.097 13.848 ;
     RECT  0.06 13.848 0.097 13.968 ;
     RECT  0.084 13.968 0.097 13.992 ;
     RECT  0.06 13.992 0.097 14.112 ;
     RECT  0.084 14.112 0.097 14.136 ;
     RECT  0.06 14.136 0.097 14.256 ;
     RECT  0.084 14.256 0.097 14.28 ;
     RECT  0.06 14.28 0.097 14.4 ;
     RECT  0.084 14.4 0.097 14.424 ;
     RECT  0.06 14.424 0.097 14.544 ;
     RECT  0.084 14.544 0.097 14.568 ;
     RECT  0.06 14.568 0.097 14.688 ;
     RECT  0.084 14.688 0.097 14.712 ;
     RECT  0.06 14.712 0.097 14.832 ;
     RECT  0.084 14.832 0.097 14.856 ;
     RECT  0.06 14.856 0.097 14.976 ;
     RECT  0.084 14.976 0.097 15 ;
     RECT  0.06 15 0.097 15.12 ;
     RECT  0.084 15.12 0.097 15.144 ;
     RECT  0.06 15.144 0.097 15.264 ;
     RECT  0.084 15.264 0.097 15.288 ;
     RECT  0.06 15.288 0.097 15.408 ;
     RECT  0.084 15.408 0.097 15.432 ;
     RECT  0.06 15.432 0.097 15.552 ;
     RECT  0.084 15.552 0.097 15.576 ;
     RECT  0.06 15.576 0.097 15.696 ;
     RECT  0.084 15.696 0.097 15.72 ;
     RECT  0.06 15.72 0.097 15.84 ;
     RECT  0.084 15.84 0.097 15.864 ;
     RECT  0.06 15.864 0.097 15.984 ;
     RECT  0.084 15.984 0.097 16.008 ;
     RECT  0.06 16.008 0.097 16.128 ;
     RECT  0.084 16.128 0.097 16.152 ;
     RECT  0.06 16.152 0.097 16.272 ;
     RECT  0.084 16.272 0.097 16.296 ;
     RECT  0.06 16.296 0.097 16.416 ;
     RECT  0.084 16.416 0.097 16.44 ;
     RECT  0.06 16.44 0.097 16.56 ;
     RECT  0.084 16.56 0.097 16.584 ;
     RECT  0.06 16.584 0.097 16.704 ;
     RECT  0.084 16.704 0.097 16.728 ;
     RECT  0.06 16.728 0.097 16.848 ;
     RECT  0.084 16.848 0.097 16.872 ;
     RECT  0.06 16.872 0.097 16.992 ;
     RECT  0.084 16.992 0.097 17.016 ;
     RECT  0.06 17.016 0.097 17.136 ;
     RECT  0.084 17.136 0.097 17.16 ;
     RECT  0.06 17.16 0.097 17.28 ;
     RECT  0.084 17.28 0.097 17.304 ;
     RECT  0.06 17.304 0.097 17.424 ;
     RECT  0.084 17.424 0.097 17.448 ;
     RECT  0.06 17.448 0.097 17.568 ;
     RECT  0.084 17.568 0.097 17.592 ;
     RECT  0.06 17.592 0.097 17.712 ;
     RECT  0.084 17.712 0.097 17.736 ;
     RECT  0.06 17.736 0.097 17.856 ;
     RECT  0.084 17.856 0.097 17.88 ;
     RECT  0.06 17.88 0.097 18 ;
     RECT  0.084 18 0.097 18.024 ;
     RECT  0.06 18.024 0.097 18.144 ;
     RECT  0.084 18.144 0.097 18.168 ;
     RECT  0.06 18.168 0.097 18.288 ;
     RECT  0.084 18.288 0.097 18.312 ;
     RECT  0.06 18.312 0.097 18.432 ;
     RECT  0.084 18.432 0.097 18.456 ;
     RECT  0.06 18.456 0.097 18.576 ;
     RECT  0.084 18.576 0.097 18.6 ;
     RECT  0.06 18.6 0.097 18.72 ;
     RECT  0.084 18.72 0.097 18.744 ;
     RECT  0.06 18.744 0.097 18.864 ;
     RECT  0.084 18.864 0.097 18.888 ;
     RECT  0.06 18.888 0.097 19.008 ;
     RECT  0.084 19.008 0.097 19.032 ;
     RECT  0.06 19.032 0.097 19.152 ;
     RECT  0.084 19.152 0.097 19.176 ;
     RECT  0.06 19.176 0.097 19.296 ;
     RECT  0.084 19.296 0.097 19.32 ;
     RECT  0.06 19.32 0.097 19.44 ;
     RECT  0.084 19.44 0.097 19.464 ;
     RECT  0.06 19.464 0.097 19.584 ;
     RECT  0.084 19.584 0.097 19.608 ;
     RECT  0.06 19.608 0.097 19.728 ;
     RECT  0.084 19.728 0.097 19.752 ;
     RECT  0.06 19.752 0.097 19.872 ;
     RECT  0.084 19.872 0.097 19.896 ;
     RECT  0.06 19.896 0.097 20.016 ;
     RECT  0.084 20.016 0.097 20.04 ;
     RECT  0.06 20.04 0.097 20.16 ;
     RECT  0.084 20.16 0.097 20.184 ;
     RECT  0.06 20.184 0.097 20.304 ;
     RECT  0.084 20.304 0.097 20.328 ;
     RECT  0.06 20.328 0.097 20.448 ;
     RECT  0.084 20.448 0.097 20.472 ;
     RECT  0.06 20.472 0.097 20.592 ;
     RECT  0.084 20.592 0.097 20.616 ;
     RECT  0.06 20.616 0.097 20.736 ;
     RECT  0.084 20.736 0.097 20.76 ;
     RECT  0.06 20.76 0.097 20.88 ;
     RECT  0.084 20.88 0.097 20.904 ;
     RECT  0.06 20.904 0.097 21.024 ;
     RECT  0.084 21.024 0.097 21.048 ;
     RECT  0.06 21.048 0.097 21.168 ;
     RECT  0.084 21.168 0.097 21.192 ;
     RECT  0.06 21.192 0.097 21.312 ;
     RECT  0.084 21.312 0.097 21.336 ;
     RECT  0.06 21.336 0.097 21.456 ;
     RECT  0.084 21.456 0.097 21.48 ;
     RECT  0.06 21.48 0.097 21.6 ;
     RECT  0.084 21.6 0.097 21.624 ;
     RECT  0.06 21.624 0.097 21.744 ;
     RECT  0.084 21.744 0.097 21.768 ;
     RECT  0.06 21.768 0.097 21.888 ;
     RECT  0.084 21.888 0.097 21.912 ;
     RECT  0.06 21.912 0.097 22.032 ;
     RECT  0.084 22.032 0.097 22.056 ;
     RECT  0.06 22.056 0.097 22.176 ;
     RECT  0.084 22.176 0.097 22.2 ;
     RECT  0.06 22.2 0.097 22.32 ;
     RECT  0.084 22.32 0.097 22.344 ;
     RECT  0.06 22.344 0.097 22.464 ;
     RECT  0.084 22.464 0.097 22.488 ;
     RECT  0.06 22.488 0.097 22.608 ;
     RECT  0.084 22.608 0.097 22.632 ;
     RECT  0.06 22.632 0.097 22.752 ;
     RECT  0.084 22.752 0.097 22.776 ;
     RECT  0.06 22.776 0.097 22.896 ;
     RECT  0.084 22.896 0.097 22.92 ;
     RECT  0.06 22.92 0.097 23.04 ;
     RECT  0.084 23.04 0.097 23.064 ;
     RECT  0.06 23.064 0.097 23.184 ;
     RECT  0.084 23.184 0.097 23.208 ;
     RECT  0.06 23.208 0.097 23.328 ;
     RECT  0.084 23.328 0.097 23.352 ;
     RECT  0.06 23.352 0.097 23.472 ;
     RECT  0.084 23.472 0.097 23.496 ;
     RECT  0.06 23.496 0.097 23.616 ;
     RECT  0.084 23.616 0.097 23.64 ;
     RECT  0.06 23.64 0.097 23.76 ;
     RECT  0.084 23.76 0.097 23.784 ;
     RECT  0.097 10.944 0.137 23.88 ;
     RECT  0.137 11.088 0.173 23.88 ;
     RECT  0.173 11.232 2.408 23.88 ;
     RECT  2.408 2.148 2.512 27.012 ;
     RECT  2.512 2.418 2.704 26.742 ;
     RECT  2.704 11.232 2.837 23.88 ;
     RECT  2.837 11.952 2.873 23.88 ;
     RECT  2.873 14.784 3.233 23.88 ;
     RECT  3.233 14.784 3.305 23.016 ;
     RECT  2.873 11.952 3.413 13.608 ;
     RECT  3.305 21.456 3.413 23.016 ;
     RECT  3.305 14.784 3.521 20.376 ;
     RECT  3.521 14.928 3.629 20.376 ;
     RECT  3.629 18 4.025 20.376 ;
     RECT  3.629 14.928 4.061 16.536 ;
     RECT  4.025 18 4.133 19.08 ;
     RECT  3.413 22.032 4.133 23.016 ;
     RECT  4.813 23.136 4.921 23.16 ;
     RECT  3.413 11.952 4.993 13.56 ;
     RECT  4.025 20.16 5.065 20.376 ;
     RECT  4.993 11.952 5.108 13.608 ;
     RECT  4.061 14.976 5.108 16.296 ;
     RECT  4.133 18.144 5.108 19.08 ;
     RECT  5.065 20.16 5.108 20.424 ;
     RECT  4.133 22.032 5.108 22.056 ;
     RECT  4.921 23.136 5.108 23.928 ;
     RECT  4.525 25.2 5.108 25.224 ;
     RECT  5.108 2.148 5.212 27.012 ;
     RECT  5.212 2.418 5.404 27.012 ;
     RECT  5.42 27.36 5.497 27.384 ;
     RECT  5.404 15.024 5.681 25.656 ;
     RECT  5.497 27.36 6.083 27.432 ;
     RECT  5.681 15.024 6.113 24.648 ;
     RECT  5.852 28.512 6.227 28.536 ;
     RECT  5.404 11.376 6.581 13.944 ;
     RECT  6.325 27.888 6.581 27.912 ;
     RECT  6.113 18.816 6.973 24.648 ;
     RECT  5.681 25.632 6.973 25.656 ;
     RECT  6.581 13.344 7.045 13.944 ;
     RECT  6.113 15.024 7.045 17.736 ;
     RECT  7.045 13.344 7.333 17.736 ;
     RECT  6.973 18.816 7.333 25.656 ;
     RECT  6.581 11.376 7.808 12.36 ;
     RECT  7.333 13.344 7.808 25.656 ;
     RECT  7.808 2.148 7.912 27.012 ;
     RECT  7.912 2.418 8.104 26.742 ;
     RECT  8.104 11.376 8.777 25.56 ;
     RECT  8.777 11.376 9.133 25.224 ;
     RECT  9.133 10.848 9.281 25.224 ;
     RECT  9.281 10.848 9.973 14.52 ;
     RECT  9.281 15.696 10.165 25.224 ;
     RECT  9.973 10.176 10.357 14.52 ;
     RECT  10.165 15.696 10.357 25.704 ;
     RECT  10.357 10.08 10.508 25.704 ;
     RECT  10.508 2.148 10.612 27.012 ;
     RECT  10.612 2.418 10.804 26.742 ;
     RECT  10.804 9.792 11.513 14.952 ;
     RECT  10.804 16.224 12.017 25.848 ;
     RECT  11.513 10.848 12.053 14.952 ;
     RECT  12.017 25.728 12.233 25.848 ;
     RECT  12.017 16.224 12.841 24.456 ;
     RECT  12.661 5.184 13.208 5.208 ;
     RECT  13.045 6.768 13.208 6.792 ;
     RECT  12.337 7.968 13.208 7.992 ;
     RECT  11.513 9.792 13.208 9.816 ;
     RECT  12.053 10.848 13.208 14.232 ;
     RECT  12.841 15.312 13.208 24.456 ;
     RECT  12.233 25.728 13.208 25.752 ;
     RECT  13.208 2.148 13.312 27.012 ;
     RECT  13.312 2.418 13.504 26.742 ;
     RECT  14.209 0.144 14.497 0.168 ;
     RECT  13.504 9.792 14.533 9.816 ;
     RECT  13.504 10.8 14.533 26.232 ;
     RECT  14.533 9.792 14.537 26.232 ;
     RECT  13.504 7.968 14.569 7.992 ;
     RECT  14.569 7.92 14.57 7.992 ;
     RECT  13.504 4.992 14.573 5.208 ;
     RECT  14.537 9.792 14.573 26.088 ;
     RECT  14.573 5.088 14.825 5.208 ;
     RECT  14.573 9.792 14.857 10.488 ;
     RECT  14.57 7.92 14.897 7.944 ;
     RECT  14.573 11.664 14.897 26.088 ;
     RECT  14.897 13.056 14.933 26.088 ;
     RECT  15.325 2.736 15.361 3.624 ;
     RECT  14.497 0.096 15.617 0.168 ;
     RECT  15.245 1.728 15.644 1.752 ;
     RECT  14.857 8.976 15.685 10.488 ;
     RECT  15.644 1.104 15.731 1.752 ;
     RECT  14.825 5.184 15.757 5.208 ;
     RECT  15.617 0.096 15.797 0.12 ;
     RECT  15.731 1.728 15.905 1.752 ;
     RECT  15.361 2.736 15.908 3.96 ;
     RECT  15.757 5.184 15.908 5.256 ;
     RECT  14.605 6.672 15.908 6.696 ;
     RECT  15.685 8.976 15.908 10.632 ;
     RECT  14.897 11.664 15.908 11.976 ;
     RECT  14.933 13.056 15.908 25.272 ;
     RECT  15.908 2.148 16.012 27.012 ;
     RECT  16.012 2.418 16.204 26.952 ;
     RECT  16.204 8.976 16.355 14.952 ;
     RECT  16.355 8.976 16.409 9.048 ;
     RECT  16.355 10.224 16.445 14.952 ;
     RECT  16.445 10.224 16.547 14.28 ;
     RECT  16.204 3.552 16.625 3.96 ;
     RECT  16.204 16.032 16.625 25.704 ;
     RECT  16.204 5.04 16.877 6.312 ;
     RECT  16.547 11.184 16.913 14.28 ;
     RECT  16.204 26.928 16.981 26.952 ;
     RECT  16.981 26.928 17.372 27.336 ;
     RECT  16.877 5.232 17.381 6.312 ;
     RECT  16.913 14.208 17.449 14.28 ;
     RECT  16.409 9.024 17.489 9.048 ;
     RECT  16.913 11.184 17.557 12.84 ;
     RECT  16.625 3.552 17.593 3.672 ;
     RECT  17.449 14.208 17.593 14.424 ;
     RECT  17.341 2.256 17.605 2.28 ;
     RECT  17.593 3.552 17.605 4.008 ;
     RECT  17.605 2.256 17.629 4.008 ;
     RECT  17.381 5.28 18.025 6.312 ;
     RECT  17.377 7.296 18.025 7.32 ;
     RECT  17.557 11.136 18.205 12.84 ;
     RECT  18.205 10.848 18.236 12.84 ;
     RECT  17.593 14.208 18.241 14.52 ;
     RECT  18.236 10.416 18.277 12.84 ;
     RECT  18.277 10.416 18.313 13.176 ;
     RECT  18.241 14.208 18.313 14.808 ;
     RECT  16.625 16.032 18.373 25.08 ;
     RECT  17.372 26.784 18.373 27.336 ;
     RECT  18.373 16.032 18.457 27.336 ;
     RECT  18.457 16.032 18.469 28.008 ;
     RECT  18.373 28.992 18.469 29.016 ;
     RECT  17.629 2.256 18.608 4.104 ;
     RECT  18.025 5.28 18.608 7.32 ;
     RECT  18.277 9.072 18.608 9.096 ;
     RECT  18.313 10.416 18.608 14.808 ;
     RECT  18.469 16.032 18.608 29.016 ;
     RECT  18.608 2.148 18.611 29.016 ;
     RECT  18.611 2.148 18.712 28.968 ;
     RECT  18.712 2.148 18.904 26.808 ;
     RECT  18.712 27.936 19.139 28.968 ;
     RECT  18.904 17.664 19.253 26.808 ;
     RECT  19.139 27.936 19.283 28.872 ;
     RECT  19.253 17.664 19.289 25.656 ;
     RECT  19.283 27.936 19.331 28.008 ;
     RECT  18.961 1.728 19.357 1.848 ;
     RECT  19.285 0.096 19.475 0.12 ;
     RECT  19.331 27.936 19.475 27.96 ;
     RECT  19.357 1.104 19.619 1.848 ;
     RECT  18.904 3.408 19.685 6.984 ;
     RECT  19.253 26.784 19.717 26.808 ;
     RECT  19.685 3.408 19.721 3.432 ;
     RECT  18.904 10.272 19.933 16.68 ;
     RECT  19.289 17.664 19.933 25.128 ;
     RECT  19.685 4.656 19.955 6.984 ;
     RECT  19.933 10.272 20.153 25.128 ;
     RECT  19.619 1.728 20.339 1.848 ;
     RECT  20.54 28.512 20.626 28.536 ;
     RECT  20.626 28.512 20.627 28.584 ;
     RECT  18.904 8.208 20.905 8.232 ;
     RECT  20.627 28.56 20.915 28.584 ;
     RECT  21.013 28.8 21.125 29.064 ;
     RECT  20.153 10.704 21.157 25.128 ;
     RECT  20.339 1.728 21.265 1.8 ;
     RECT  20.717 0.096 21.301 0.12 ;
     RECT  21.265 1.104 21.301 1.8 ;
     RECT  21.301 0.096 21.308 1.8 ;
     RECT  19.955 4.656 21.308 6.84 ;
     RECT  20.905 7.92 21.308 8.232 ;
     RECT  21.157 10.704 21.308 25.752 ;
     RECT  19.717 26.784 21.308 27.336 ;
     RECT  21.308 0.096 21.604 27.336 ;
     RECT  21.604 25.728 21.665 25.752 ;
     RECT  21.604 10.704 21.737 24.744 ;
     RECT  21.604 0.096 21.773 1.848 ;
     RECT  21.604 3.744 21.827 6.408 ;
     RECT  21.125 28.8 22.019 29.016 ;
     RECT  21.773 0.576 22.069 1.848 ;
     RECT  22.069 0.576 22.097 0.6 ;
     RECT  21.604 7.92 22.277 8.232 ;
     RECT  21.827 3.744 22.633 3.768 ;
     RECT  22.633 3.648 22.777 3.768 ;
     RECT  22.777 3.456 22.813 3.768 ;
     RECT  21.827 4.8 22.813 6.408 ;
     RECT  21.737 10.848 22.813 24.744 ;
     RECT  22.069 1.728 22.921 1.848 ;
     RECT  22.813 3.456 22.921 6.408 ;
     RECT  22.597 28.464 22.931 28.488 ;
     RECT  21.604 27.312 22.957 27.336 ;
     RECT  23.317 0.096 23.353 0.12 ;
     RECT  22.813 10.848 23.497 25.08 ;
     RECT  23.353 0.096 23.507 0.6 ;
     RECT  23.497 10.08 23.516 25.08 ;
     RECT  22.277 8.208 23.557 8.232 ;
     RECT  23.516 9.456 23.557 25.08 ;
     RECT  22.921 3.456 23.713 7.032 ;
     RECT  22.921 1.728 23.821 2.28 ;
     RECT  23.713 3.408 23.821 7.032 ;
     RECT  23.821 1.728 23.825 7.032 ;
     RECT  22.957 26.784 23.893 27.336 ;
     RECT  23.557 8.208 24.001 25.08 ;
     RECT  23.893 26.112 24.001 27.336 ;
     RECT  23.825 2.148 24.008 7.032 ;
     RECT  24.001 8.208 24.008 27.336 ;
     RECT  24.008 2.148 24.112 27.336 ;
     RECT  24.037 28.992 24.181 29.016 ;
     RECT  24.112 2.418 24.304 27.336 ;
     RECT  24.181 28.896 24.325 29.016 ;
     RECT  24.304 4.08 24.365 6.408 ;
     RECT  24.325 28.8 24.418 29.016 ;
     RECT  24.304 11.232 24.515 27.336 ;
     RECT  24.418 28.8 24.515 29.064 ;
     RECT  24.515 29.04 24.517 29.064 ;
     RECT  24.515 26.208 24.553 27.336 ;
     RECT  23.507 0.096 24.581 0.12 ;
     RECT  24.515 11.232 24.581 25.08 ;
     RECT  24.365 5.808 24.653 6.408 ;
     RECT  24.304 9.888 24.905 10.152 ;
     RECT  24.653 6.336 25.121 6.408 ;
     RECT  24.581 11.424 25.121 25.08 ;
     RECT  25.121 6.384 25.193 6.408 ;
     RECT  24.304 2.496 25.229 2.904 ;
     RECT  25.121 11.424 25.229 12.984 ;
     RECT  25.121 13.968 25.301 25.08 ;
     RECT  25.229 11.424 25.373 12.792 ;
     RECT  24.553 26.784 25.379 27.336 ;
     RECT  24.304 8.016 25.388 8.52 ;
     RECT  24.905 9.888 25.388 10.104 ;
     RECT  25.388 8.016 25.475 10.104 ;
     RECT  25.373 11.664 25.475 12.792 ;
     RECT  25.379 26.832 25.523 27.336 ;
     RECT  25.229 2.88 25.697 2.904 ;
     RECT  26.017 6.816 26.089 6.84 ;
     RECT  25.475 8.016 26.089 8.04 ;
     RECT  25.523 27.216 26.237 27.336 ;
     RECT  26.089 6.816 26.269 6.888 ;
     RECT  26.089 7.92 26.269 8.04 ;
     RECT  24.365 4.08 26.557 4.68 ;
     RECT  25.475 9.696 26.629 10.104 ;
     RECT  25.301 14.256 26.629 25.08 ;
     RECT  26.549 2.832 26.708 2.856 ;
     RECT  26.557 4.08 26.708 4.968 ;
     RECT  26.269 6.816 26.708 8.04 ;
     RECT  26.629 9.552 26.708 10.104 ;
     RECT  25.475 11.664 26.708 12.504 ;
     RECT  26.629 14.256 26.708 25.848 ;
     RECT  26.708 2.148 26.812 27.012 ;
     RECT  26.812 2.418 27.004 26.742 ;
     RECT  27.004 2.88 27.137 3.096 ;
     RECT  27.004 7.392 27.137 7.704 ;
     RECT  27.137 3.072 27.173 3.096 ;
     RECT  27.004 9.072 27.173 12.504 ;
     RECT  27.173 9.072 27.425 12.072 ;
     RECT  27.004 4.224 27.929 5.736 ;
     RECT  27.004 14.4 27.964 26.52 ;
     RECT  27.137 7.392 28.105 7.416 ;
     RECT  27.964 14.4 28.253 24.792 ;
     RECT  27.425 9.072 28.289 11.832 ;
     RECT  28.105 7.392 28.429 7.704 ;
     RECT  27.929 4.656 28.433 5.736 ;
     RECT  28.289 9.312 28.433 11.832 ;
     RECT  28.433 9.36 28.609 11.832 ;
     RECT  28.253 14.4 28.717 23.928 ;
     RECT  28.429 7.392 29.185 8.28 ;
     RECT  28.717 13.584 29.257 23.928 ;
     RECT  27.964 26.208 29.257 26.52 ;
     RECT  29.005 2.592 29.408 2.616 ;
     RECT  28.433 4.656 29.408 5.544 ;
     RECT  29.185 6.912 29.408 8.28 ;
     RECT  28.609 9.36 29.408 12.504 ;
     RECT  29.257 13.584 29.408 24.648 ;
     RECT  29.257 26.208 29.408 26.664 ;
     RECT  29.408 2.148 29.512 27.012 ;
     RECT  29.512 2.418 29.704 26.742 ;
     RECT  29.704 7.776 30.089 9.144 ;
     RECT  29.704 26.64 30.449 26.664 ;
     RECT  29.704 10.32 30.773 25.08 ;
     RECT  30.089 7.92 30.809 9.144 ;
     RECT  29.704 3.552 30.841 6.456 ;
     RECT  30.841 3.552 30.845 6.84 ;
     RECT  30.809 7.92 30.917 8.808 ;
     RECT  30.845 3.552 30.989 5.208 ;
     RECT  30.989 3.552 31.201 4.536 ;
     RECT  30.845 6.288 31.201 6.84 ;
     RECT  30.773 10.32 31.813 12.936 ;
     RECT  30.773 14.16 31.813 25.08 ;
     RECT  31.201 3.408 32.108 4.536 ;
     RECT  31.201 6.288 32.108 6.888 ;
     RECT  30.917 8.784 32.108 8.808 ;
     RECT  31.813 10.32 32.108 25.08 ;
     RECT  31.957 26.208 32.108 26.232 ;
     RECT  32.108 2.148 32.212 27.012 ;
     RECT  32.212 2.418 32.404 26.742 ;
     RECT  32.404 14.496 32.573 25.992 ;
     RECT  32.404 9.84 33.149 11.736 ;
     RECT  33.149 11.328 33.185 11.736 ;
     RECT  32.404 4.176 33.397 4.68 ;
     RECT  32.404 6.384 33.397 6.552 ;
     RECT  33.397 4.176 33.541 5.016 ;
     RECT  33.397 6.384 33.793 6.744 ;
     RECT  33.397 2.544 34.081 2.568 ;
     RECT  33.685 8.448 34.153 8.472 ;
     RECT  32.573 14.496 34.153 25.8 ;
     RECT  34.153 8.448 34.261 8.808 ;
     RECT  33.149 9.84 34.261 10.344 ;
     RECT  33.185 11.712 34.261 11.736 ;
     RECT  33.541 4.128 34.333 5.016 ;
     RECT  34.153 14.496 34.597 26.616 ;
     RECT  34.081 2.304 34.808 2.568 ;
     RECT  34.333 4.128 34.808 5.304 ;
     RECT  33.793 6.384 34.808 7.368 ;
     RECT  34.261 8.448 34.808 10.344 ;
     RECT  34.261 11.712 34.808 12.552 ;
     RECT  34.597 14.112 34.808 26.616 ;
     RECT  34.808 2.148 34.912 27.012 ;
     RECT  34.912 2.418 35.104 26.742 ;
     RECT  35.104 14.112 35.165 26.664 ;
     RECT  35.104 2.544 35.201 4.248 ;
     RECT  35.104 6.384 35.381 7.656 ;
     RECT  35.104 8.976 35.381 9 ;
     RECT  35.104 11.712 35.417 13.08 ;
     RECT  35.104 5.28 35.669 5.304 ;
     RECT  35.381 6.384 35.885 7.368 ;
     RECT  35.104 10.32 36.133 10.344 ;
     RECT  35.417 11.712 36.313 12.936 ;
     RECT  36.133 10.272 36.497 10.344 ;
     RECT  35.165 14.112 36.673 26.616 ;
     RECT  36.313 11.424 36.817 12.936 ;
     RECT  36.673 14.112 36.817 26.664 ;
     RECT  35.201 3.408 36.997 4.248 ;
     RECT  36.313 5.424 36.997 5.448 ;
     RECT  36.961 8.736 36.997 8.76 ;
     RECT  36.997 3.408 37.069 5.448 ;
     RECT  35.885 7.344 37.285 7.368 ;
     RECT  37.069 3.408 37.321 5.592 ;
     RECT  36.997 8.496 37.381 8.76 ;
     RECT  37.285 6.864 37.501 7.368 ;
     RECT  37.381 8.496 37.501 8.808 ;
     RECT  37.321 2.88 37.508 5.592 ;
     RECT  37.501 6.864 37.508 8.808 ;
     RECT  36.497 10.272 37.508 10.296 ;
     RECT  36.817 11.424 37.508 26.664 ;
     RECT  37.508 2.148 37.612 27.012 ;
     RECT  37.612 2.418 37.804 26.76 ;
     RECT  37.804 8.16 37.865 8.808 ;
     RECT  37.804 2.784 38.477 6.888 ;
     RECT  38.185 0.576 38.509 0.6 ;
     RECT  37.804 9.936 38.585 11.928 ;
     RECT  38.509 0.096 38.761 0.6 ;
     RECT  38.585 11.664 38.837 11.928 ;
     RECT  38.761 0.096 39.049 0.648 ;
     RECT  39.049 0.096 39.445 1.128 ;
     RECT  37.804 13.296 39.697 13.32 ;
     RECT  38.477 6.192 39.841 6.888 ;
     RECT  37.865 8.4 39.841 8.808 ;
     RECT  37.804 14.64 39.949 26.76 ;
     RECT  39.697 13.296 39.985 13.368 ;
     RECT  39.985 13.152 40.021 13.368 ;
     RECT  38.585 9.936 40.049 10.2 ;
     RECT  38.837 11.664 40.049 11.88 ;
     RECT  40.049 9.936 40.057 11.88 ;
     RECT  40.021 13.056 40.057 13.368 ;
     RECT  38.477 2.784 40.069 5.16 ;
     RECT  39.841 6.192 40.069 8.808 ;
     RECT  40.069 2.784 40.208 8.808 ;
     RECT  40.057 9.936 40.208 13.368 ;
     RECT  39.949 14.4 40.208 26.76 ;
     RECT  40.208 2.148 40.312 27.012 ;
     RECT  40.312 2.148 40.313 26.76 ;
     RECT  39.445 0.096 40.355 1.176 ;
     RECT  40.313 2.148 40.504 26.742 ;
     RECT  40.504 2.784 40.637 6.696 ;
     RECT  40.504 11.664 40.853 13.08 ;
     RECT  40.355 0.096 40.931 0.552 ;
     RECT  40.504 14.208 41.149 26.712 ;
     RECT  40.504 7.968 41.429 9.192 ;
     RECT  40.504 10.608 41.465 10.632 ;
     RECT  40.853 13.056 41.465 13.08 ;
     RECT  41.149 14.4 41.501 26.712 ;
     RECT  40.741 1.728 41.605 1.752 ;
     RECT  40.853 11.664 41.677 11.688 ;
     RECT  40.637 3.312 41.749 6.696 ;
     RECT  41.429 7.968 41.749 9.096 ;
     RECT  41.605 1.68 41.857 1.752 ;
     RECT  41.857 1.2 41.941 1.752 ;
     RECT  40.931 0.096 42.077 0.12 ;
     RECT  41.941 1.728 42.181 1.752 ;
     RECT  41.677 10.704 42.541 11.688 ;
     RECT  41.501 14.64 42.721 26.712 ;
     RECT  42.181 1.728 42.757 2.28 ;
     RECT  41.749 3.312 42.757 9.096 ;
     RECT  42.721 14.496 42.901 26.712 ;
     RECT  42.757 1.728 42.908 9.096 ;
     RECT  42.541 10.08 42.908 11.688 ;
     RECT  42.901 13.92 42.908 26.712 ;
     RECT  42.908 1.728 43.012 27.012 ;
     RECT  42.757 0.576 43.045 0.6 ;
     RECT  43.012 1.728 43.204 26.742 ;
     RECT  43.045 0.096 43.265 0.6 ;
     RECT  43.204 13.92 43.373 26.328 ;
     RECT  43.204 10.608 43.409 12.6 ;
     RECT  43.409 10.656 43.445 12.6 ;
     RECT  43.373 14.208 43.445 26.328 ;
     RECT  43.445 10.656 43.625 12.408 ;
     RECT  43.625 10.848 43.697 12.408 ;
     RECT  43.445 14.496 44.201 26.328 ;
     RECT  43.204 1.728 44.273 9.096 ;
     RECT  44.273 7.92 44.489 9.096 ;
     RECT  44.485 13.056 44.597 13.08 ;
     RECT  43.697 10.848 44.809 11.688 ;
     RECT  44.809 10.848 45.025 12.264 ;
     RECT  44.273 1.728 45.277 6.84 ;
     RECT  44.489 7.92 45.277 8.856 ;
     RECT  43.265 0.096 45.604 0.12 ;
     RECT  45.277 1.728 45.608 8.856 ;
     RECT  45.025 10.32 45.608 12.264 ;
     RECT  44.201 14.496 45.608 24.36 ;
     RECT  44.201 25.488 45.608 26.328 ;
     RECT  45.608 1.728 45.712 27.012 ;
     RECT  45.712 1.728 45.904 26.742 ;
     RECT  45.904 1.728 46.019 9.288 ;
     RECT  45.904 10.32 46.019 10.92 ;
     RECT  45.904 11.952 46.109 12.072 ;
     RECT  45.904 26.304 46.181 26.328 ;
     RECT  45.604 0.096 46.645 0.168 ;
     RECT  46.019 2.976 47.029 9.288 ;
     RECT  46.019 10.896 47.029 10.92 ;
     RECT  47.029 2.976 47.069 10.92 ;
     RECT  47.069 2.88 47.075 10.92 ;
     RECT  45.904 13.536 47.125 23.976 ;
     RECT  46.019 1.728 47.153 1.8 ;
     RECT  47.075 2.88 47.153 10.824 ;
     RECT  47.153 3.12 47.189 10.824 ;
     RECT  47.125 13.056 47.267 23.976 ;
     RECT  47.189 3.12 47.325 10.248 ;
     RECT  46.645 0.096 47.585 0.552 ;
     RECT  47.585 0.144 47.653 0.552 ;
     RECT  47.153 1.728 47.653 1.752 ;
     RECT  47.653 0.144 48.125 1.752 ;
     RECT  48.125 1.152 48.181 1.752 ;
     RECT  47.325 3.12 48.181 9.912 ;
     RECT  48.181 1.152 48.308 9.912 ;
     RECT  46.109 11.952 48.308 11.976 ;
     RECT  47.267 13.536 48.308 23.976 ;
     RECT  48.308 1.152 48.412 27.012 ;
     RECT  48.125 0.144 48.419 0.168 ;
     RECT  48.412 1.152 48.604 26.742 ;
     RECT  48.604 1.152 48.995 9.912 ;
     RECT  48.604 16.032 49.349 25.368 ;
     RECT  49.349 25.344 49.601 25.368 ;
     RECT  48.995 1.728 49.633 9.912 ;
     RECT  48.604 11.952 49.889 11.976 ;
     RECT  49.633 1.728 51.008 10.296 ;
     RECT  48.604 14.736 51.008 15 ;
     RECT  49.349 16.032 51.008 24.12 ;
     RECT  50.869 0.144 51.011 0.168 ;
     RECT  51.008 1.728 51.112 27.012 ;
     RECT  51.112 1.728 51.304 26.742 ;
     RECT  51.304 1.728 51.365 10.296 ;
     RECT  51.365 5.568 51.875 10.296 ;
     RECT  51.365 1.728 51.941 4.584 ;
     RECT  51.304 16.032 52.157 24.408 ;
     RECT  51.941 1.728 52.337 3.288 ;
     RECT  51.941 4.512 52.369 4.584 ;
     RECT  51.875 5.568 52.369 9.576 ;
     RECT  52.337 2.736 52.499 3.288 ;
     RECT  52.499 2.736 52.553 3.24 ;
     RECT  52.549 0.576 52.585 0.6 ;
     RECT  52.585 0.528 52.693 0.6 ;
     RECT  52.693 0.096 52.733 0.6 ;
     RECT  52.733 0.096 52.883 0.552 ;
     RECT  52.883 0.096 53.027 0.504 ;
     RECT  52.157 16.032 53.197 23.4 ;
     RECT  52.157 24.384 53.197 24.408 ;
     RECT  53.027 0.096 53.273 0.168 ;
     RECT  52.337 1.728 53.708 1.752 ;
     RECT  52.553 3.216 53.708 3.24 ;
     RECT  52.369 4.512 53.708 9.576 ;
     RECT  51.304 14.736 53.708 15 ;
     RECT  53.197 16.032 53.708 24.408 ;
     RECT  53.708 1.728 53.812 27.012 ;
     RECT  53.812 1.728 54.004 26.742 ;
     RECT  53.273 0.096 54.421 0.12 ;
     RECT  54.004 1.728 54.709 3.24 ;
     RECT  54.709 1.152 54.893 3.24 ;
     RECT  54.893 1.728 54.995 3.24 ;
     RECT  54.004 16.128 55.037 23.928 ;
     RECT  54.995 1.728 55.109 3 ;
     RECT  55.037 19.824 55.141 23.928 ;
     RECT  55.141 19.824 55.225 24.552 ;
     RECT  55.249 26.832 55.357 26.856 ;
     RECT  55.109 2.304 55.379 3 ;
     RECT  54.004 14.736 55.525 15 ;
     RECT  55.037 16.128 55.525 18.84 ;
     RECT  55.357 26.832 55.537 27.672 ;
     RECT  54.421 0.096 55.573 0.168 ;
     RECT  55.537 26.64 55.609 27.672 ;
     RECT  55.609 26.64 55.861 27.816 ;
     RECT  55.861 25.776 55.897 27.816 ;
     RECT  55.897 25.776 56.077 28.104 ;
     RECT  55.379 2.832 56.408 3 ;
     RECT  54.004 4.416 56.408 10.344 ;
     RECT  55.525 14.736 56.408 18.84 ;
     RECT  55.225 19.824 56.408 23.688 ;
     RECT  56.077 25.536 56.408 28.248 ;
     RECT  56.408 2.148 56.581 28.248 ;
     RECT  56.581 1.776 56.704 28.248 ;
     RECT  55.573 0.096 56.869 0.6 ;
     RECT  56.704 1.776 56.869 1.8 ;
     RECT  56.869 0.096 56.981 1.8 ;
     RECT  56.704 2.88 57.161 8.856 ;
     RECT  56.981 0.096 57.305 0.216 ;
     RECT  56.704 10.176 57.697 10.2 ;
     RECT  57.305 0.096 58.268 0.168 ;
     RECT  57.161 3.312 58.309 8.856 ;
     RECT  57.697 10.176 58.309 10.344 ;
     RECT  58.268 0.096 58.355 0.552 ;
     RECT  56.981 1.776 58.381 1.8 ;
     RECT  58.355 0.096 58.673 0.168 ;
     RECT  56.704 14.736 58.837 28.248 ;
     RECT  58.381 1.728 58.849 1.8 ;
     RECT  58.309 3.312 58.933 10.968 ;
     RECT  58.673 0.144 59.075 0.168 ;
     RECT  58.849 1.728 59.108 2.04 ;
     RECT  58.933 3.024 59.108 10.968 ;
     RECT  58.837 14.256 59.108 28.248 ;
     RECT  59.108 1.728 59.404 28.248 ;
     RECT  59.404 18.432 59.609 28.248 ;
     RECT  59.404 14.736 59.825 15 ;
     RECT  59.404 17.424 59.825 17.448 ;
     RECT  59.609 20.4 59.897 28.248 ;
     RECT  59.897 20.4 59.933 20.424 ;
     RECT  59.404 1.728 59.939 9 ;
     RECT  59.609 18.432 60.005 19.368 ;
     RECT  59.897 21.408 60.005 25.08 ;
     RECT  59.939 1.728 60.077 8.904 ;
     RECT  59.825 14.736 60.149 14.76 ;
     RECT  60.005 21.456 60.437 25.08 ;
     RECT  59.897 26.112 60.509 28.248 ;
     RECT  59.404 10.272 60.565 10.968 ;
     RECT  60.005 18.432 60.581 18.84 ;
     RECT  60.565 10.224 60.652 10.968 ;
     RECT  60.581 18.432 60.829 18.504 ;
     RECT  60.829 17.616 60.833 18.504 ;
     RECT  60.077 2.064 61.045 8.904 ;
     RECT  61.045 1.728 61.553 8.904 ;
     RECT  60.437 21.648 61.621 25.08 ;
     RECT  61.441 0.528 61.669 0.552 ;
     RECT  61.553 2.016 61.808 8.904 ;
     RECT  60.652 10.944 61.808 10.968 ;
     RECT  59.404 16.032 61.808 16.056 ;
     RECT  60.833 17.616 61.808 17.64 ;
     RECT  61.621 21.408 61.808 25.08 ;
     RECT  60.509 26.256 61.808 28.248 ;
     RECT  61.808 2.016 61.811 28.248 ;
     RECT  61.669 0.144 62.099 0.552 ;
     RECT  61.811 2.064 62.104 28.248 ;
     RECT  62.104 7.44 62.201 7.752 ;
     RECT  62.104 2.064 62.273 2.952 ;
     RECT  62.201 7.632 62.309 7.752 ;
     RECT  62.309 7.632 62.381 7.704 ;
     RECT  62.104 3.984 62.425 4.584 ;
     RECT  62.099 0.528 62.531 0.552 ;
     RECT  62.381 7.68 62.561 7.704 ;
     RECT  62.425 3.984 62.675 4.008 ;
     RECT  62.273 2.928 62.819 2.952 ;
     RECT  62.104 17.424 63.169 18.024 ;
     RECT  62.104 14.688 63.205 16.296 ;
     RECT  63.169 17.28 63.205 18.024 ;
     RECT  62.104 20.016 63.205 20.472 ;
     RECT  63.205 19.296 63.241 20.472 ;
     RECT  62.104 23.904 63.241 25.224 ;
     RECT  63.241 23.616 63.277 25.224 ;
     RECT  63.205 14.688 63.817 18.024 ;
     RECT  63.241 19.152 63.817 20.472 ;
     RECT  62.104 21.744 63.817 22.632 ;
     RECT  63.277 23.616 63.817 25.944 ;
     RECT  62.104 26.928 63.817 28.248 ;
     RECT  63.817 14.688 63.853 18.168 ;
     RECT  63.853 14.544 64.716 14.568 ;
     RECT  63.853 14.568 64.764 14.688 ;
     RECT  63.853 14.688 64.716 14.712 ;
     RECT  63.853 14.712 64.764 14.832 ;
     RECT  63.853 14.832 64.716 14.856 ;
     RECT  63.853 14.856 64.764 14.976 ;
     RECT  63.853 14.976 64.716 15 ;
     RECT  63.853 15 64.764 15.12 ;
     RECT  63.853 15.12 64.716 15.144 ;
     RECT  63.853 15.144 64.764 15.264 ;
     RECT  63.853 15.264 64.716 15.288 ;
     RECT  63.853 15.288 64.764 15.408 ;
     RECT  63.853 15.408 64.716 15.432 ;
     RECT  63.853 15.432 64.764 15.552 ;
     RECT  63.853 15.552 64.716 15.576 ;
     RECT  63.853 15.576 64.764 15.696 ;
     RECT  63.853 15.696 64.716 15.72 ;
     RECT  63.853 15.72 64.764 15.84 ;
     RECT  63.853 15.84 64.716 15.864 ;
     RECT  63.853 15.864 64.764 15.984 ;
     RECT  63.853 15.984 64.716 16.008 ;
     RECT  63.853 16.008 64.764 16.128 ;
     RECT  63.853 16.128 64.716 16.152 ;
     RECT  63.853 16.152 64.764 16.272 ;
     RECT  63.853 16.272 64.716 16.296 ;
     RECT  63.853 16.296 64.764 16.416 ;
     RECT  63.853 16.416 64.716 16.44 ;
     RECT  63.853 16.44 64.764 16.56 ;
     RECT  63.853 16.56 64.716 16.584 ;
     RECT  63.853 16.584 64.764 16.704 ;
     RECT  63.853 16.704 64.716 16.728 ;
     RECT  63.853 16.728 64.764 16.848 ;
     RECT  63.853 16.848 64.716 16.872 ;
     RECT  63.853 16.872 64.764 16.992 ;
     RECT  63.853 16.992 64.716 17.016 ;
     RECT  63.853 17.016 64.764 17.136 ;
     RECT  63.853 17.136 64.716 17.16 ;
     RECT  63.853 17.16 64.764 17.28 ;
     RECT  63.853 17.28 64.716 17.304 ;
     RECT  63.853 17.304 64.764 17.424 ;
     RECT  63.853 17.424 64.716 17.448 ;
     RECT  63.853 17.448 64.764 17.568 ;
     RECT  63.853 17.568 64.716 17.592 ;
     RECT  63.853 17.592 64.764 17.712 ;
     RECT  63.853 17.712 64.716 17.736 ;
     RECT  63.853 17.736 64.764 17.856 ;
     RECT  63.853 17.856 64.716 17.88 ;
     RECT  63.853 17.88 64.764 18 ;
     RECT  63.853 18 64.716 18.024 ;
     RECT  63.853 18.024 64.764 18.144 ;
     RECT  63.853 18.144 64.716 18.168 ;
     RECT  63.817 19.152 64.716 19.176 ;
     RECT  63.817 19.176 64.764 19.296 ;
     RECT  63.817 19.296 64.716 19.32 ;
     RECT  63.817 19.32 64.764 19.44 ;
     RECT  63.817 19.44 64.716 19.464 ;
     RECT  63.817 19.464 64.764 19.584 ;
     RECT  63.817 19.584 64.716 19.608 ;
     RECT  63.817 19.608 64.764 19.728 ;
     RECT  63.817 19.728 64.716 19.752 ;
     RECT  63.817 19.752 64.764 19.872 ;
     RECT  63.817 19.872 64.716 19.896 ;
     RECT  63.817 19.896 64.764 20.016 ;
     RECT  63.817 20.016 64.716 20.04 ;
     RECT  63.817 20.04 64.764 20.16 ;
     RECT  63.817 20.16 64.716 20.184 ;
     RECT  63.817 20.184 64.764 20.304 ;
     RECT  63.817 20.304 64.716 20.328 ;
     RECT  63.817 20.328 64.764 20.448 ;
     RECT  63.817 20.448 64.716 20.472 ;
     RECT  63.817 20.472 64.764 20.592 ;
     RECT  63.817 20.592 64.716 20.616 ;
     RECT  63.817 20.616 64.764 20.736 ;
     RECT  63.817 20.736 64.716 20.76 ;
     RECT  63.817 20.76 64.764 20.88 ;
     RECT  63.817 20.88 64.716 20.904 ;
     RECT  63.817 20.904 64.764 21.024 ;
     RECT  63.817 21.024 64.716 21.048 ;
     RECT  63.817 21.048 64.764 21.168 ;
     RECT  63.817 21.168 64.716 21.192 ;
     RECT  63.817 21.192 64.764 21.312 ;
     RECT  63.817 21.312 64.716 21.336 ;
     RECT  63.817 21.336 64.764 21.456 ;
     RECT  63.817 21.456 64.716 21.48 ;
     RECT  63.817 21.48 64.764 21.6 ;
     RECT  63.817 21.6 64.716 21.624 ;
     RECT  63.817 21.624 64.764 21.744 ;
     RECT  63.817 21.744 64.716 21.768 ;
     RECT  63.817 21.768 64.764 21.888 ;
     RECT  63.817 21.888 64.716 21.912 ;
     RECT  63.817 21.912 64.764 22.032 ;
     RECT  63.817 22.032 64.716 22.056 ;
     RECT  63.817 22.056 64.764 22.176 ;
     RECT  63.817 22.176 64.716 22.2 ;
     RECT  63.817 22.2 64.764 22.32 ;
     RECT  63.817 22.32 64.716 22.344 ;
     RECT  63.817 22.344 64.764 22.464 ;
     RECT  63.817 22.464 64.716 22.488 ;
     RECT  63.817 22.488 64.764 22.608 ;
     RECT  63.817 22.608 64.716 22.632 ;
     RECT  63.817 22.632 64.764 22.752 ;
     RECT  63.817 22.752 64.716 22.776 ;
     RECT  63.817 22.776 64.764 22.896 ;
     RECT  63.817 22.896 64.716 22.92 ;
     RECT  63.817 22.92 64.764 23.04 ;
     RECT  63.817 23.04 64.716 23.064 ;
     RECT  63.817 23.064 64.764 23.184 ;
     RECT  63.817 23.184 64.716 23.208 ;
     RECT  63.817 23.208 64.764 23.328 ;
     RECT  63.817 23.328 64.716 23.352 ;
     RECT  63.817 23.352 64.764 23.472 ;
     RECT  63.817 23.472 64.716 23.496 ;
     RECT  63.817 23.496 64.764 23.616 ;
     RECT  63.817 23.616 64.716 23.64 ;
     RECT  63.817 23.64 64.764 23.76 ;
     RECT  63.817 23.76 64.716 23.784 ;
     RECT  63.817 23.784 64.764 23.904 ;
     RECT  63.817 23.904 64.716 23.928 ;
     RECT  63.817 23.928 64.764 24.048 ;
     RECT  63.817 24.048 64.716 24.072 ;
     RECT  63.817 24.072 64.764 24.192 ;
     RECT  63.817 24.192 64.716 24.216 ;
     RECT  63.817 24.216 64.764 24.336 ;
     RECT  63.817 24.336 64.716 24.36 ;
     RECT  63.817 24.36 64.764 24.48 ;
     RECT  63.817 24.48 64.716 24.504 ;
     RECT  63.817 24.504 64.764 24.624 ;
     RECT  63.817 24.624 64.716 24.648 ;
     RECT  63.817 24.648 64.764 24.768 ;
     RECT  63.817 24.768 64.716 24.792 ;
     RECT  63.817 24.792 64.764 24.912 ;
     RECT  63.817 24.912 64.716 24.936 ;
     RECT  63.817 24.936 64.764 25.056 ;
     RECT  63.817 25.056 64.716 25.08 ;
     RECT  63.817 25.08 64.764 25.2 ;
     RECT  63.817 25.2 64.716 25.224 ;
     RECT  63.817 25.224 64.764 25.344 ;
     RECT  63.817 25.344 64.716 25.368 ;
     RECT  63.817 25.368 64.764 25.488 ;
     RECT  63.817 25.488 64.716 25.512 ;
     RECT  63.817 25.512 64.764 25.632 ;
     RECT  63.817 25.632 64.716 25.656 ;
     RECT  63.817 25.656 64.764 25.776 ;
     RECT  63.817 25.776 64.716 25.8 ;
     RECT  63.817 25.8 64.764 25.92 ;
     RECT  63.817 25.92 64.716 25.944 ;
     RECT  63.817 25.944 64.764 26.064 ;
     RECT  63.817 26.064 64.716 26.088 ;
     RECT  63.817 26.088 64.764 26.208 ;
     RECT  63.817 26.208 64.716 26.232 ;
     RECT  63.817 26.232 64.764 26.352 ;
     RECT  63.817 26.352 64.716 26.376 ;
     RECT  63.817 26.376 64.764 26.496 ;
     RECT  63.817 26.496 64.716 26.52 ;
     RECT  63.817 26.52 64.764 26.64 ;
     RECT  63.817 26.64 64.716 26.664 ;
     RECT  63.817 26.664 64.764 26.784 ;
     RECT  63.817 26.784 64.716 26.808 ;
     RECT  63.817 26.808 64.764 26.928 ;
     RECT  63.817 26.928 64.716 26.952 ;
     RECT  63.817 26.952 64.764 27.072 ;
     RECT  63.817 27.072 64.716 27.096 ;
     RECT  63.817 27.096 64.764 27.216 ;
     RECT  63.817 27.216 64.716 27.24 ;
     RECT  63.817 27.24 64.764 27.36 ;
     RECT  63.817 27.36 64.716 27.384 ;
     RECT  63.817 27.384 64.764 27.504 ;
     RECT  63.817 27.504 64.716 27.528 ;
     RECT  63.817 27.528 64.764 27.648 ;
     RECT  63.817 27.648 64.716 27.672 ;
     RECT  63.817 27.672 64.764 27.792 ;
     RECT  63.817 27.792 64.716 27.816 ;
     RECT  63.817 27.816 64.764 27.936 ;
     RECT  63.817 27.936 64.716 27.96 ;
     RECT  63.817 27.96 64.764 28.08 ;
     RECT  63.817 28.08 64.716 28.104 ;
     RECT  63.817 28.104 64.764 28.224 ;
     RECT  63.817 28.224 64.716 28.248 ;
    LAYER M5 ;
     RECT  14.568 0.016 14.688 0.084 ;
     RECT  14.712 0.016 14.832 0.084 ;
     RECT  14.856 0.016 14.976 0.084 ;
     RECT  15 0.016 15.12 0.084 ;
     RECT  15.144 0.016 15.264 0.084 ;
     RECT  15.288 0.016 15.408 0.084 ;
     RECT  15.432 0.016 15.552 0.084 ;
     RECT  15.576 0.016 15.696 0.084 ;
     RECT  15.72 0.016 15.84 0.084 ;
     RECT  14.544 0.084 15.864 0.131 ;
     RECT  14.688 0.131 15.864 0.179 ;
     RECT  38.76 0.016 38.88 0.084 ;
     RECT  38.904 0.016 39.024 0.084 ;
     RECT  39.048 0.016 39.168 0.084 ;
     RECT  39.192 0.016 39.312 0.084 ;
     RECT  39.336 0.016 39.456 0.084 ;
     RECT  39.48 0.016 39.6 0.084 ;
     RECT  39.624 0.016 39.744 0.084 ;
     RECT  39.768 0.016 39.888 0.084 ;
     RECT  39.912 0.016 40.032 0.084 ;
     RECT  40.056 0.016 40.176 0.084 ;
     RECT  40.2 0.016 40.32 0.084 ;
     RECT  40.344 0.016 40.464 0.084 ;
     RECT  40.488 0.016 40.608 0.084 ;
     RECT  40.632 0.016 40.752 0.084 ;
     RECT  40.776 0.016 40.896 0.084 ;
     RECT  40.92 0.016 41.04 0.084 ;
     RECT  41.064 0.016 41.184 0.084 ;
     RECT  41.208 0.016 41.328 0.084 ;
     RECT  41.352 0.016 41.472 0.084 ;
     RECT  41.496 0.016 41.616 0.084 ;
     RECT  41.64 0.016 41.76 0.084 ;
     RECT  41.784 0.016 41.904 0.084 ;
     RECT  41.928 0.016 42.048 0.084 ;
     RECT  42.072 0.016 42.192 0.084 ;
     RECT  42.216 0.016 42.336 0.084 ;
     RECT  42.36 0.016 42.48 0.084 ;
     RECT  42.504 0.016 42.624 0.084 ;
     RECT  42.648 0.016 42.768 0.084 ;
     RECT  42.792 0.016 42.912 0.084 ;
     RECT  42.936 0.016 43.056 0.084 ;
     RECT  43.08 0.016 43.2 0.084 ;
     RECT  43.224 0.016 43.344 0.084 ;
     RECT  43.368 0.016 43.488 0.084 ;
     RECT  43.512 0.016 43.632 0.084 ;
     RECT  43.656 0.016 43.776 0.084 ;
     RECT  43.8 0.016 43.92 0.084 ;
     RECT  43.944 0.016 44.064 0.084 ;
     RECT  44.088 0.016 44.208 0.084 ;
     RECT  44.232 0.016 44.352 0.084 ;
     RECT  44.376 0.016 44.496 0.084 ;
     RECT  44.52 0.016 44.64 0.084 ;
     RECT  44.664 0.016 44.784 0.084 ;
     RECT  44.808 0.016 44.928 0.084 ;
     RECT  44.952 0.016 45.072 0.084 ;
     RECT  45.096 0.016 45.216 0.084 ;
     RECT  45.24 0.016 45.36 0.084 ;
     RECT  45.384 0.016 45.504 0.084 ;
     RECT  45.528 0.016 45.648 0.084 ;
     RECT  45.672 0.016 45.792 0.084 ;
     RECT  45.816 0.016 45.936 0.084 ;
     RECT  45.96 0.016 46.08 0.084 ;
     RECT  46.104 0.016 46.224 0.084 ;
     RECT  46.248 0.016 46.368 0.084 ;
     RECT  46.392 0.016 46.512 0.084 ;
     RECT  46.536 0.016 46.656 0.084 ;
     RECT  46.68 0.016 46.8 0.084 ;
     RECT  46.824 0.016 46.944 0.084 ;
     RECT  46.968 0.016 47.088 0.084 ;
     RECT  47.112 0.016 47.232 0.084 ;
     RECT  47.256 0.016 47.376 0.084 ;
     RECT  47.4 0.016 47.52 0.084 ;
     RECT  47.544 0.016 47.664 0.084 ;
     RECT  47.688 0.016 47.808 0.084 ;
     RECT  47.832 0.016 47.952 0.084 ;
     RECT  47.976 0.016 48.096 0.084 ;
     RECT  48.12 0.016 48.24 0.084 ;
     RECT  48.264 0.016 48.384 0.084 ;
     RECT  48.408 0.016 48.528 0.084 ;
     RECT  48.552 0.016 48.672 0.084 ;
     RECT  48.696 0.016 48.816 0.084 ;
     RECT  48.84 0.016 48.96 0.084 ;
     RECT  48.984 0.016 49.104 0.084 ;
     RECT  49.128 0.016 49.248 0.084 ;
     RECT  49.272 0.016 49.392 0.084 ;
     RECT  49.416 0.016 49.536 0.084 ;
     RECT  49.56 0.016 49.68 0.084 ;
     RECT  49.704 0.016 49.824 0.084 ;
     RECT  49.848 0.016 49.968 0.084 ;
     RECT  49.992 0.016 50.112 0.084 ;
     RECT  50.136 0.016 50.256 0.084 ;
     RECT  50.28 0.016 50.4 0.084 ;
     RECT  50.424 0.016 50.544 0.084 ;
     RECT  50.568 0.016 50.688 0.084 ;
     RECT  50.712 0.016 50.832 0.084 ;
     RECT  50.856 0.016 50.976 0.084 ;
     RECT  51 0.016 51.12 0.084 ;
     RECT  51.144 0.016 51.264 0.084 ;
     RECT  51.288 0.016 51.408 0.084 ;
     RECT  51.432 0.016 51.552 0.084 ;
     RECT  51.576 0.016 51.696 0.084 ;
     RECT  51.72 0.016 51.84 0.084 ;
     RECT  51.864 0.016 51.984 0.084 ;
     RECT  52.008 0.016 52.128 0.084 ;
     RECT  52.152 0.016 52.272 0.084 ;
     RECT  52.296 0.016 52.416 0.084 ;
     RECT  52.44 0.016 52.56 0.084 ;
     RECT  52.584 0.016 52.704 0.084 ;
     RECT  52.728 0.016 52.848 0.084 ;
     RECT  52.872 0.016 52.992 0.084 ;
     RECT  53.016 0.016 53.136 0.084 ;
     RECT  53.16 0.016 53.28 0.084 ;
     RECT  53.304 0.016 53.424 0.084 ;
     RECT  53.448 0.016 53.568 0.084 ;
     RECT  53.592 0.016 53.712 0.084 ;
     RECT  53.736 0.016 53.856 0.084 ;
     RECT  53.88 0.016 54 0.084 ;
     RECT  54.024 0.016 54.144 0.084 ;
     RECT  54.168 0.016 54.288 0.084 ;
     RECT  54.312 0.016 54.432 0.084 ;
     RECT  54.456 0.016 54.576 0.084 ;
     RECT  54.6 0.016 54.72 0.084 ;
     RECT  54.744 0.016 54.864 0.084 ;
     RECT  54.888 0.016 55.008 0.084 ;
     RECT  55.032 0.016 55.152 0.084 ;
     RECT  55.176 0.016 55.296 0.084 ;
     RECT  55.32 0.016 55.44 0.084 ;
     RECT  55.464 0.016 55.584 0.084 ;
     RECT  55.608 0.016 55.728 0.084 ;
     RECT  55.752 0.016 55.872 0.084 ;
     RECT  55.896 0.016 56.016 0.084 ;
     RECT  56.04 0.016 56.16 0.084 ;
     RECT  56.184 0.016 56.304 0.084 ;
     RECT  56.328 0.016 56.448 0.084 ;
     RECT  56.472 0.016 56.592 0.084 ;
     RECT  56.616 0.016 56.736 0.084 ;
     RECT  56.76 0.016 56.88 0.084 ;
     RECT  56.904 0.016 57.024 0.084 ;
     RECT  38.736 0.084 57.048 0.227 ;
     RECT  58.344 0.016 58.464 0.084 ;
     RECT  58.488 0.016 58.608 0.084 ;
     RECT  58.632 0.016 58.752 0.084 ;
     RECT  58.776 0.016 58.896 0.084 ;
     RECT  58.92 0.016 59.04 0.084 ;
     RECT  59.064 0.016 59.184 0.084 ;
     RECT  59.208 0.016 59.328 0.084 ;
     RECT  59.352 0.016 59.472 0.084 ;
     RECT  59.496 0.016 59.616 0.084 ;
     RECT  59.64 0.016 59.76 0.084 ;
     RECT  59.784 0.016 59.904 0.084 ;
     RECT  59.928 0.016 60.048 0.084 ;
     RECT  60.072 0.016 60.192 0.084 ;
     RECT  60.216 0.016 60.336 0.084 ;
     RECT  60.36 0.016 60.48 0.084 ;
     RECT  60.504 0.016 60.624 0.084 ;
     RECT  60.648 0.016 60.768 0.084 ;
     RECT  60.792 0.016 60.912 0.084 ;
     RECT  60.936 0.016 61.056 0.084 ;
     RECT  61.08 0.016 61.2 0.084 ;
     RECT  61.224 0.016 61.344 0.084 ;
     RECT  61.368 0.016 61.488 0.084 ;
     RECT  61.512 0.016 61.632 0.084 ;
     RECT  61.656 0.016 61.776 0.084 ;
     RECT  61.8 0.016 61.92 0.084 ;
     RECT  61.944 0.016 62.064 0.084 ;
     RECT  62.088 0.016 62.208 0.084 ;
     RECT  62.232 0.016 62.352 0.084 ;
     RECT  62.376 0.016 62.496 0.084 ;
     RECT  62.52 0.016 62.64 0.084 ;
     RECT  62.664 0.016 62.784 0.084 ;
     RECT  58.32 0.084 62.808 0.563 ;
     RECT  38.736 0.227 56.904 0.611 ;
     RECT  39.024 0.611 56.904 0.659 ;
     RECT  39.312 0.659 56.904 1.139 ;
     RECT  39.456 1.139 56.904 1.187 ;
     RECT  15.264 0.179 15.864 1.763 ;
     RECT  19.176 0.016 19.296 0.084 ;
     RECT  19.32 0.016 19.44 0.084 ;
     RECT  19.464 0.016 19.584 0.084 ;
     RECT  19.608 0.016 19.728 0.084 ;
     RECT  19.752 0.016 19.872 0.084 ;
     RECT  19.896 0.016 20.016 0.084 ;
     RECT  20.04 0.016 20.16 0.084 ;
     RECT  20.184 0.016 20.304 0.084 ;
     RECT  20.328 0.016 20.448 0.084 ;
     RECT  20.472 0.016 20.592 0.084 ;
     RECT  20.616 0.016 20.736 0.084 ;
     RECT  20.76 0.016 20.88 0.084 ;
     RECT  20.904 0.016 21.024 0.084 ;
     RECT  21.048 0.016 21.168 0.084 ;
     RECT  21.192 0.016 21.312 0.084 ;
     RECT  21.336 0.016 21.456 0.084 ;
     RECT  21.48 0.016 21.6 0.084 ;
     RECT  21.624 0.016 21.744 0.084 ;
     RECT  21.768 0.016 21.888 0.084 ;
     RECT  21.912 0.016 22.032 0.084 ;
     RECT  22.056 0.016 22.176 0.084 ;
     RECT  22.2 0.016 22.32 0.084 ;
     RECT  22.344 0.016 22.464 0.084 ;
     RECT  22.488 0.016 22.608 0.084 ;
     RECT  22.632 0.016 22.752 0.084 ;
     RECT  22.776 0.016 22.896 0.084 ;
     RECT  22.92 0.016 23.04 0.084 ;
     RECT  23.064 0.016 23.184 0.084 ;
     RECT  23.208 0.016 23.328 0.084 ;
     RECT  23.352 0.016 23.472 0.084 ;
     RECT  23.496 0.016 23.616 0.084 ;
     RECT  19.152 0.084 23.64 1.763 ;
     RECT  40.2 1.187 56.856 1.763 ;
     RECT  58.464 0.563 62.808 1.763 ;
     RECT  21.3 1.763 23.64 1.811 ;
     RECT  19.152 1.763 20.328 1.859 ;
     RECT  22.752 1.811 23.64 1.859 ;
     RECT  23.04 1.859 23.64 2.137 ;
     RECT  2.4 2.137 2.52 2.151 ;
     RECT  5.1 2.137 5.22 2.151 ;
     RECT  7.8 2.137 7.92 2.151 ;
     RECT  10.5 2.137 10.62 2.151 ;
     RECT  13.2 2.137 13.32 2.151 ;
     RECT  15.9 2.137 16.02 2.151 ;
     RECT  23.04 2.137 24.12 2.151 ;
     RECT  26.7 2.137 26.82 2.151 ;
     RECT  29.4 2.137 29.52 2.151 ;
     RECT  32.1 2.137 32.22 2.151 ;
     RECT  34.8 2.137 34.92 2.151 ;
     RECT  37.5 2.137 37.62 2.151 ;
     RECT  18.6 2.137 18.912 2.245 ;
     RECT  23.04 2.151 24.312 2.291 ;
     RECT  26.7 2.151 27.012 2.821 ;
     RECT  58.944 1.763 62.808 2.963 ;
     RECT  58.944 2.963 62.664 3.059 ;
     RECT  53.424 1.763 56.856 3.157 ;
     RECT  40.2 1.763 52.44 3.253 ;
     RECT  53.424 3.157 56.952 3.253 ;
     RECT  17.616 2.245 18.912 3.397 ;
     RECT  34.8 2.151 35.112 3.397 ;
     RECT  37.5 2.151 37.812 3.397 ;
     RECT  17.616 3.397 19.512 3.587 ;
     RECT  40.2 3.253 56.952 3.731 ;
     RECT  40.2 3.731 56.712 4.019 ;
     RECT  59.1 3.059 62.664 4.019 ;
     RECT  26.592 2.821 27.012 4.115 ;
     RECT  34.8 3.397 35.208 4.163 ;
     RECT  21.3 1.811 21.612 4.501 ;
     RECT  23.184 2.291 24.312 4.595 ;
     RECT  59.1 4.019 62.376 4.595 ;
     RECT  41.568 4.019 56.712 4.643 ;
     RECT  29.4 2.151 29.712 4.693 ;
     RECT  37.008 3.397 37.812 4.739 ;
     RECT  21.3 4.501 21.816 4.835 ;
     RECT  33.552 4.117 33.576 4.979 ;
     RECT  21.3 4.835 21.612 4.981 ;
     RECT  28.416 4.693 29.712 5.171 ;
     RECT  53.568 4.643 56.712 5.171 ;
     RECT  13.2 2.151 13.512 5.173 ;
     RECT  41.568 4.643 52.488 5.219 ;
     RECT  18.6 3.587 19.512 5.363 ;
     RECT  29.28 5.171 29.712 5.555 ;
     RECT  40.2 4.019 40.512 5.557 ;
     RECT  23.856 4.595 24.312 5.701 ;
     RECT  20.88 4.981 21.612 5.747 ;
     RECT  41.568 5.219 41.592 5.747 ;
     RECT  42.768 5.219 52.488 5.747 ;
     RECT  53.7 5.171 56.712 5.795 ;
     RECT  47.856 5.747 51.864 5.891 ;
     RECT  40.08 5.557 40.512 6.181 ;
     RECT  15.9 2.151 16.212 6.229 ;
     RECT  59.1 4.595 62.112 6.229 ;
     RECT  42.768 5.747 45.912 6.323 ;
     RECT  53.7 5.795 54.408 6.323 ;
     RECT  23.472 5.701 24.312 6.563 ;
     RECT  55.776 5.795 56.712 6.757 ;
     RECT  13.056 5.173 13.512 6.803 ;
     RECT  53.7 6.323 54.012 6.853 ;
     RECT  39.36 6.181 40.512 6.899 ;
     RECT  19.92 5.845 19.944 6.995 ;
     RECT  53.376 6.853 54.012 7.235 ;
     RECT  48.144 5.891 51.864 7.333 ;
     RECT  58.368 6.229 62.112 7.381 ;
     RECT  42.768 6.323 44.232 7.475 ;
     RECT  58.128 7.381 62.112 7.715 ;
     RECT  55.776 6.757 57.144 7.763 ;
     RECT  45.408 6.323 45.912 8.003 ;
     RECT  61.536 7.715 62.112 8.195 ;
     RECT  24 6.563 24.312 8.197 ;
     RECT  37.248 4.739 37.812 8.579 ;
     RECT  42.9 7.475 44.232 8.579 ;
     RECT  58.128 7.715 60.408 8.579 ;
     RECT  44.208 8.579 44.232 8.627 ;
     RECT  40.2 6.899 40.512 8.677 ;
     RECT  37.392 8.579 37.812 8.725 ;
     RECT  47.28 7.333 51.864 8.771 ;
     RECT  50.304 8.771 51.864 8.867 ;
     RECT  18.6 5.363 18.912 9.061 ;
     RECT  26.7 4.115 27.012 9.061 ;
     RECT  47.28 8.771 48.612 9.155 ;
     RECT  40.2 8.677 41.4 9.203 ;
     RECT  23.568 8.197 24.312 9.491 ;
     RECT  50.736 8.867 51.864 9.587 ;
     RECT  40.2 9.203 40.512 9.925 ;
     RECT  37.392 8.725 38.664 9.971 ;
     RECT  10.5 2.151 10.812 10.069 ;
     RECT  10.368 10.069 10.812 10.165 ;
     RECT  15.9 6.229 16.344 10.213 ;
     RECT  47.28 9.155 47.304 10.213 ;
     RECT  58.32 8.579 60.408 10.213 ;
     RECT  47.04 10.213 47.304 10.259 ;
     RECT  37.392 9.971 37.812 10.307 ;
     RECT  51 9.587 51.864 10.307 ;
     RECT  55.776 7.763 56.712 10.307 ;
     RECT  58.32 10.213 60.6 10.307 ;
     RECT  45.6 8.003 45.912 10.309 ;
     RECT  26.7 9.061 27.96 10.883 ;
     RECT  40.08 9.925 40.512 10.883 ;
     RECT  47.04 10.259 47.16 10.931 ;
     RECT  18.288 9.061 18.912 10.979 ;
     RECT  58.32 10.307 59.412 10.979 ;
     RECT  60.576 10.307 60.6 10.979 ;
     RECT  9.984 10.165 10.812 11.027 ;
     RECT  21.3 5.747 21.612 11.173 ;
     RECT  18.48 10.979 18.912 11.221 ;
     RECT  20.4 11.173 21.612 11.221 ;
     RECT  15.9 10.213 16.536 11.267 ;
     RECT  18.48 11.221 21.612 11.411 ;
     RECT  22.8 10.885 22.824 11.555 ;
     RECT  15.9 11.267 16.344 11.699 ;
     RECT  7.8 2.151 8.112 11.941 ;
     RECT  45.6 10.309 46.008 12.083 ;
     RECT  30.816 11.605 30.84 12.131 ;
     RECT  18.6 11.411 21.612 12.517 ;
     RECT  7.8 11.941 8.472 12.563 ;
     RECT  10.368 11.027 10.812 12.613 ;
     RECT  40.2 10.883 40.512 13.045 ;
     RECT  47.136 10.931 47.16 13.045 ;
     RECT  18.48 12.517 21.612 13.091 ;
     RECT  47.136 13.045 47.256 13.091 ;
     RECT  18.48 13.091 19.8 13.139 ;
     RECT  9.744 12.613 10.812 13.619 ;
     RECT  11.856 12.613 11.88 13.619 ;
     RECT  34.8 4.163 35.112 14.101 ;
     RECT  58.848 10.979 59.412 14.291 ;
     RECT  26.7 10.883 27.012 14.389 ;
     RECT  40.2 13.045 41.112 14.531 ;
     RECT  26.7 14.389 27.144 14.819 ;
     RECT  25.44 4.645 25.464 14.867 ;
     RECT  34.608 14.101 35.112 14.915 ;
     RECT  10.368 13.619 10.812 14.963 ;
     RECT  56.4 10.307 56.712 15.061 ;
     RECT  18.6 13.139 19.8 15.205 ;
     RECT  45.6 12.083 45.912 15.205 ;
     RECT  47.232 13.091 47.256 15.205 ;
     RECT  45.6 15.205 47.256 15.251 ;
     RECT  37.5 10.307 37.812 15.301 ;
     RECT  21.3 13.091 21.612 15.349 ;
     RECT  22.8 14.197 22.824 15.349 ;
     RECT  13.2 6.803 13.512 15.397 ;
     RECT  21.3 15.349 22.824 15.491 ;
     RECT  37.5 15.301 38.184 15.827 ;
     RECT  32.1 2.151 32.412 15.925 ;
     RECT  40.2 14.531 40.512 15.925 ;
     RECT  59.1 14.291 59.412 15.925 ;
     RECT  5.1 2.151 5.412 15.973 ;
     RECT  32.1 15.925 32.52 15.973 ;
     RECT  40.08 15.925 40.512 15.973 ;
     RECT  48.3 9.155 48.612 15.973 ;
     RECT  24 9.491 24.312 16.021 ;
     RECT  58.656 15.925 59.412 16.021 ;
     RECT  32.1 15.973 32.712 16.115 ;
     RECT  39.12 15.973 40.512 16.115 ;
     RECT  32.1 16.115 32.616 16.163 ;
     RECT  13.2 15.397 13.896 16.259 ;
     RECT  21.3 15.491 21.912 16.261 ;
     RECT  23.904 16.021 24.312 16.549 ;
     RECT  5.1 15.973 6.168 16.595 ;
     RECT  58.608 16.021 59.412 16.643 ;
     RECT  45.6 15.251 46.776 16.787 ;
     RECT  15.9 11.699 16.212 16.837 ;
     RECT  53.7 7.235 54.012 16.885 ;
     RECT  55.536 15.061 56.712 16.931 ;
     RECT  23.904 16.549 25.128 16.933 ;
     RECT  10.5 14.963 10.812 16.981 ;
     RECT  21.168 16.261 21.912 16.981 ;
     RECT  23.328 16.933 25.128 17.027 ;
     RECT  2.4 2.151 2.712 17.029 ;
     RECT  15.696 16.837 16.212 17.029 ;
     RECT  51 10.307 51.312 17.077 ;
     RECT  9.12 16.981 10.812 17.123 ;
     RECT  21.072 16.981 21.912 17.123 ;
     RECT  14.832 17.029 16.212 17.219 ;
     RECT  2.4 17.029 2.856 17.315 ;
     RECT  13.2 16.259 13.704 17.459 ;
     RECT  18.6 15.205 19.896 17.605 ;
     RECT  32.1 16.163 32.412 17.605 ;
     RECT  48.192 15.973 48.612 17.605 ;
     RECT  55.824 16.931 56.712 17.605 ;
     RECT  61.8 8.195 62.112 17.605 ;
     RECT  15.696 17.219 16.212 17.651 ;
     RECT  23.328 17.027 24.312 17.651 ;
     RECT  50.88 17.077 51.312 17.699 ;
     RECT  55.824 17.605 56.808 17.699 ;
     RECT  41.76 16.837 41.784 17.747 ;
     RECT  28.032 17.029 28.056 17.891 ;
     RECT  40.08 16.115 40.512 17.893 ;
     RECT  21.168 17.123 21.912 17.989 ;
     RECT  39.552 17.893 40.512 18.035 ;
     RECT  52.944 16.885 54.012 18.131 ;
     RECT  47.376 17.605 48.612 18.133 ;
     RECT  24 17.651 24.312 18.181 ;
     RECT  17.712 17.605 19.896 18.275 ;
     RECT  59.1 16.643 59.412 18.565 ;
     RECT  29.4 5.555 29.712 18.661 ;
     RECT  42.9 8.579 43.212 18.661 ;
     RECT  58.848 18.565 59.412 18.709 ;
     RECT  2.4 17.315 2.712 18.805 ;
     RECT  2.304 18.805 2.712 18.995 ;
     RECT  21.168 17.989 22.488 19.091 ;
     RECT  10.08 17.123 10.812 19.333 ;
     RECT  24 18.181 24.936 19.379 ;
     RECT  45.6 16.787 45.912 19.429 ;
     RECT  46.992 18.133 48.612 19.429 ;
     RECT  53.04 18.131 54.012 19.571 ;
     RECT  45.6 19.429 48.612 19.573 ;
     RECT  29.136 18.661 29.712 19.621 ;
     RECT  42.624 18.661 43.212 19.621 ;
     RECT  51 17.699 51.312 19.621 ;
     RECT  29.136 19.621 30.6 19.717 ;
     RECT  31.872 17.605 32.412 19.717 ;
     RECT  15.9 17.651 16.212 19.765 ;
     RECT  22.944 19.333 22.968 19.811 ;
     RECT  29.136 19.717 32.412 19.859 ;
     RECT  40.032 18.035 40.512 19.861 ;
     RECT  40.032 19.861 41.064 20.003 ;
     RECT  45.6 19.573 49.224 20.003 ;
     RECT  56.4 17.699 56.808 20.003 ;
     RECT  37.5 15.827 37.812 20.053 ;
     RECT  10.08 19.333 11.736 20.099 ;
     RECT  29.136 19.859 30.6 20.099 ;
     RECT  53.7 19.571 54.012 20.149 ;
     RECT  55.152 20.053 55.176 20.149 ;
     RECT  47.376 20.003 49.224 20.195 ;
     RECT  29.136 20.099 30.504 20.339 ;
     RECT  47.376 20.195 49.128 20.339 ;
     RECT  37.5 20.053 37.944 20.437 ;
     RECT  42.144 19.621 43.212 20.437 ;
     RECT  15.168 19.765 16.212 20.579 ;
     RECT  18.6 18.275 19.896 20.579 ;
     RECT  40.032 20.003 40.512 20.579 ;
     RECT  15.792 20.579 16.212 20.581 ;
     RECT  31.872 19.859 32.412 20.723 ;
     RECT  26.7 14.819 27.012 21.109 ;
     RECT  15.792 20.581 16.344 21.155 ;
     RECT  47.76 20.339 49.128 21.203 ;
     RECT  50.736 19.621 51.312 21.203 ;
     RECT  21.168 19.091 21.912 21.349 ;
     RECT  36.672 20.437 37.944 21.493 ;
     RECT  58.176 18.709 59.412 21.493 ;
     RECT  36.192 21.493 37.944 21.539 ;
     RECT  57.84 21.493 59.412 21.541 ;
     RECT  37.5 21.539 37.944 21.587 ;
     RECT  40.08 20.579 40.512 21.637 ;
     RECT  53.7 20.149 55.176 21.683 ;
     RECT  60.864 17.605 62.112 21.683 ;
     RECT  42.144 20.437 43.32 21.731 ;
     RECT  45.6 20.003 45.912 21.733 ;
     RECT  34.8 14.915 35.112 21.925 ;
     RECT  36.192 21.539 36.216 21.925 ;
     RECT  34.8 21.925 36.216 22.067 ;
     RECT  57.84 21.541 59.544 22.069 ;
     RECT  57.84 22.069 59.592 22.117 ;
     RECT  42.9 21.731 43.32 22.163 ;
     RECT  47.76 21.203 48.612 22.163 ;
     RECT  10.08 20.099 10.812 22.165 ;
     RECT  36.192 22.067 36.216 22.307 ;
     RECT  57.84 22.117 60.408 22.307 ;
     RECT  32.1 20.723 32.412 22.309 ;
     RECT  6.672 21.637 6.696 22.451 ;
     RECT  30.864 21.925 30.888 22.451 ;
     RECT  26.7 21.109 27.192 22.453 ;
     RECT  24 19.379 24.312 22.501 ;
     RECT  23.904 22.501 24.312 22.597 ;
     RECT  51 21.203 51.312 22.597 ;
     RECT  21.12 21.349 21.912 22.643 ;
     RECT  23.904 22.597 25.224 22.643 ;
     RECT  26.7 22.453 27.528 22.643 ;
     RECT  24 22.643 25.224 22.739 ;
     RECT  0.144 22.549 0.168 22.787 ;
     RECT  45.6 21.733 46.008 22.787 ;
     RECT  21.168 22.643 21.912 22.789 ;
     RECT  12 21.733 12.024 22.883 ;
     RECT  52.608 21.157 52.632 22.883 ;
     RECT  19.968 22.165 19.992 22.979 ;
     RECT  21.168 22.789 22.296 23.075 ;
     RECT  9.792 22.165 10.812 23.077 ;
     RECT  9.12 23.077 10.812 23.219 ;
     RECT  14.64 22.837 14.664 23.363 ;
     RECT  21.168 23.075 21.912 23.411 ;
     RECT  58.992 22.307 60.408 23.411 ;
     RECT  31.872 22.309 32.412 23.461 ;
     RECT  24 22.739 24.648 23.555 ;
     RECT  39.888 21.637 40.512 23.555 ;
     RECT  37.5 21.587 37.812 23.557 ;
     RECT  31.872 23.461 32.52 23.603 ;
     RECT  57.84 22.307 57.864 23.843 ;
     RECT  24 23.555 24.312 23.845 ;
     RECT  29.136 20.339 29.712 23.845 ;
     RECT  61.536 21.683 62.112 23.987 ;
     RECT  44.4 22.741 44.424 24.083 ;
     RECT  26.7 22.643 27.384 24.131 ;
     RECT  50.736 22.597 51.312 24.131 ;
     RECT  59.1 23.411 60.36 24.131 ;
     RECT  15.9 21.155 16.344 24.133 ;
     RECT  61.632 23.987 62.112 24.419 ;
     RECT  48.3 22.163 48.612 24.469 ;
     RECT  55.152 21.683 55.176 24.563 ;
     RECT  40.08 23.555 40.512 24.613 ;
     RECT  40.08 24.613 41.064 24.803 ;
     RECT  59.1 24.131 59.592 24.899 ;
     RECT  37.392 23.557 37.812 24.995 ;
     RECT  42.9 22.163 43.212 25.045 ;
     RECT  23.184 23.845 24.312 25.091 ;
     RECT  31.872 23.603 32.412 25.091 ;
     RECT  40.08 24.803 40.632 25.139 ;
     RECT  9.792 23.219 10.812 25.235 ;
     RECT  48.3 24.469 48.744 25.235 ;
     RECT  13.2 17.459 13.512 25.285 ;
     RECT  24 25.091 24.312 25.285 ;
     RECT  18.6 20.579 18.912 25.525 ;
     RECT  24 25.285 24.408 25.525 ;
     RECT  26.7 24.131 27.012 25.573 ;
     RECT  18.6 25.525 19.032 25.621 ;
     RECT  34.8 22.067 35.112 25.621 ;
     RECT  10.176 25.235 10.812 25.715 ;
     RECT  24 25.525 24.456 25.717 ;
     RECT  37.5 24.995 37.812 25.717 ;
     RECT  18.6 25.621 19.272 25.813 ;
     RECT  37.5 25.717 38.76 25.859 ;
     RECT  24 25.717 24.504 26.101 ;
     RECT  13.2 25.285 14.28 26.243 ;
     RECT  29.088 23.845 29.712 26.243 ;
     RECT  31.968 25.091 32.412 26.243 ;
     RECT  42.72 25.045 43.212 26.243 ;
     RECT  26.7 25.573 27.912 26.531 ;
     RECT  34.8 25.621 35.832 26.627 ;
     RECT  40.2 25.139 40.632 26.675 ;
     RECT  15.9 24.133 17.16 26.773 ;
     RECT  18.384 25.813 19.272 26.773 ;
     RECT  21.3 23.411 21.912 26.773 ;
     RECT  23.904 26.101 24.504 26.773 ;
     RECT  23.04 26.773 25.368 26.821 ;
     RECT  2.4 18.995 2.712 27.009 ;
     RECT  7.8 12.563 8.112 27.009 ;
     RECT  10.5 25.715 10.812 27.009 ;
     RECT  13.2 26.243 13.512 27.009 ;
     RECT  26.7 26.531 27.012 27.009 ;
     RECT  29.4 26.243 29.712 27.009 ;
     RECT  32.1 26.243 32.412 27.009 ;
     RECT  34.8 26.627 35.112 27.009 ;
     RECT  37.5 25.859 37.812 27.009 ;
     RECT  40.2 26.675 40.512 27.009 ;
     RECT  42.9 26.243 43.212 27.009 ;
     RECT  45.6 22.787 45.912 27.009 ;
     RECT  48.3 25.235 48.612 27.009 ;
     RECT  51 24.131 51.312 27.009 ;
     RECT  53.7 21.683 54.012 27.009 ;
     RECT  56.4 20.003 56.712 27.009 ;
     RECT  59.1 24.899 59.412 27.009 ;
     RECT  61.8 24.419 62.112 27.009 ;
     RECT  2.4 27.009 2.52 27.023 ;
     RECT  5.1 16.595 5.412 27.023 ;
     RECT  7.8 27.009 7.92 27.023 ;
     RECT  10.5 27.009 10.62 27.023 ;
     RECT  13.2 27.009 13.32 27.023 ;
     RECT  15.9 26.773 21.912 27.023 ;
     RECT  26.7 27.009 26.82 27.023 ;
     RECT  29.4 27.009 29.52 27.023 ;
     RECT  32.1 27.009 32.22 27.023 ;
     RECT  34.8 27.009 34.92 27.023 ;
     RECT  37.5 27.009 37.62 27.023 ;
     RECT  40.2 27.009 40.32 27.023 ;
     RECT  42.9 27.009 43.02 27.023 ;
     RECT  45.6 27.009 45.72 27.023 ;
     RECT  48.3 27.009 48.42 27.023 ;
     RECT  51 27.009 51.12 27.023 ;
     RECT  53.7 27.009 53.82 27.023 ;
     RECT  56.4 27.009 56.52 27.023 ;
     RECT  59.1 27.009 59.22 27.023 ;
     RECT  61.8 27.009 61.92 27.023 ;
     RECT  23.04 26.821 25.512 27.205 ;
     RECT  16.848 27.023 21.912 27.301 ;
     RECT  23.04 27.205 25.944 27.301 ;
     RECT  5.472 27.349 6.072 27.877 ;
     RECT  5.472 27.877 6.36 29.076 ;
     RECT  5.496 29.076 5.616 29.136 ;
     RECT  5.64 29.076 5.76 29.136 ;
     RECT  5.784 29.076 5.904 29.136 ;
     RECT  5.928 29.076 6.048 29.136 ;
     RECT  6.072 29.076 6.192 29.136 ;
     RECT  6.216 29.076 6.336 29.136 ;
     RECT  16.848 27.301 25.944 29.076 ;
     RECT  16.872 29.076 16.992 29.136 ;
     RECT  17.016 29.076 17.136 29.136 ;
     RECT  17.16 29.076 17.28 29.136 ;
     RECT  17.304 29.076 17.424 29.136 ;
     RECT  17.448 29.076 17.568 29.136 ;
     RECT  17.592 29.076 17.712 29.136 ;
     RECT  17.736 29.076 17.856 29.136 ;
     RECT  17.88 29.076 18 29.136 ;
     RECT  18.024 29.076 18.144 29.136 ;
     RECT  18.168 29.076 18.288 29.136 ;
     RECT  18.312 29.076 18.432 29.136 ;
     RECT  18.456 29.076 18.576 29.136 ;
     RECT  18.6 29.076 18.72 29.136 ;
     RECT  18.744 29.076 18.864 29.136 ;
     RECT  18.888 29.076 19.008 29.136 ;
     RECT  19.032 29.076 19.152 29.136 ;
     RECT  19.176 29.076 19.296 29.136 ;
     RECT  19.32 29.076 19.44 29.136 ;
     RECT  19.464 29.076 19.584 29.136 ;
     RECT  19.608 29.076 19.728 29.136 ;
     RECT  19.752 29.076 19.872 29.136 ;
     RECT  19.896 29.076 20.016 29.136 ;
     RECT  20.04 29.076 20.16 29.136 ;
     RECT  20.184 29.076 20.304 29.136 ;
     RECT  20.328 29.076 20.448 29.136 ;
     RECT  20.472 29.076 20.592 29.136 ;
     RECT  20.616 29.076 20.736 29.136 ;
     RECT  20.76 29.076 20.88 29.136 ;
     RECT  20.904 29.076 21.024 29.136 ;
     RECT  21.048 29.076 21.168 29.136 ;
     RECT  21.192 29.076 21.312 29.136 ;
     RECT  21.336 29.076 21.456 29.136 ;
     RECT  21.48 29.076 21.6 29.136 ;
     RECT  21.624 29.076 21.744 29.136 ;
     RECT  21.768 29.076 21.888 29.136 ;
     RECT  21.912 29.076 22.032 29.136 ;
     RECT  22.056 29.076 22.176 29.136 ;
     RECT  22.2 29.076 22.32 29.136 ;
     RECT  22.344 29.076 22.464 29.136 ;
     RECT  22.488 29.076 22.608 29.136 ;
     RECT  22.632 29.076 22.752 29.136 ;
     RECT  22.776 29.076 22.896 29.136 ;
     RECT  22.92 29.076 23.04 29.136 ;
     RECT  23.064 29.076 23.184 29.136 ;
     RECT  23.208 29.076 23.328 29.136 ;
     RECT  23.352 29.076 23.472 29.136 ;
     RECT  23.496 29.076 23.616 29.136 ;
     RECT  23.64 29.076 23.76 29.136 ;
     RECT  23.784 29.076 23.904 29.136 ;
     RECT  23.928 29.076 24.048 29.136 ;
     RECT  24.072 29.076 24.192 29.136 ;
     RECT  24.216 29.076 24.336 29.136 ;
     RECT  24.36 29.076 24.48 29.136 ;
     RECT  24.504 29.076 24.624 29.136 ;
     RECT  24.648 29.076 24.768 29.136 ;
     RECT  24.792 29.076 24.912 29.136 ;
     RECT  24.936 29.076 25.056 29.136 ;
     RECT  25.08 29.076 25.2 29.136 ;
     RECT  25.224 29.076 25.344 29.136 ;
     RECT  25.368 29.076 25.488 29.136 ;
     RECT  25.512 29.076 25.632 29.136 ;
     RECT  25.656 29.076 25.776 29.136 ;
     RECT  25.8 29.076 25.92 29.136 ;
     RECT  57.096 0.016 58.272 0.132 ;
     RECT  57.048 0.132 58.32 0.227 ;
     RECT  56.904 0.227 58.32 0.563 ;
     RECT  20.328 1.763 21.3 1.859 ;
     RECT  52.44 1.763 53.424 3.253 ;
     RECT  21.612 1.811 22.752 1.859 ;
     RECT  21.612 1.859 23.04 2.291 ;
     RECT  16.212 2.245 17.616 3.587 ;
     RECT  40.512 4.019 41.568 5.747 ;
     RECT  26.592 4.115 26.7 4.645 ;
     RECT  32.412 4.117 33.552 4.979 ;
     RECT  33.576 4.117 34.8 4.979 ;
     RECT  21.816 4.501 23.184 4.595 ;
     RECT  23.472 4.595 23.856 5.701 ;
     RECT  52.488 4.643 53.568 5.171 ;
     RECT  24.312 4.645 25.44 14.867 ;
     RECT  25.464 4.645 26.7 14.867 ;
     RECT  27.012 4.693 28.416 5.171 ;
     RECT  19.512 4.981 20.88 5.363 ;
     RECT  52.488 5.171 53.7 5.747 ;
     RECT  41.592 5.219 42.768 5.747 ;
     RECT  18.912 5.363 20.88 5.747 ;
     RECT  18.912 5.747 21.3 5.845 ;
     RECT  51.864 5.747 53.7 6.853 ;
     RECT  54.408 5.795 55.776 6.323 ;
     RECT  18.912 5.845 19.92 6.995 ;
     RECT  19.944 5.845 21.3 6.995 ;
     RECT  47.856 5.891 48.144 7.333 ;
     RECT  44.232 6.323 45.408 8.003 ;
     RECT  57.144 6.757 58.368 7.381 ;
     RECT  51.864 6.853 53.376 7.235 ;
     RECT  45.912 7.333 47.28 10.213 ;
     RECT  57.144 7.381 58.128 7.763 ;
     RECT  42.768 7.475 42.9 8.677 ;
     RECT  60.408 7.715 61.536 8.195 ;
     RECT  56.712 7.763 58.128 8.579 ;
     RECT  44.232 8.003 45.6 8.627 ;
     RECT  60.408 8.195 61.8 10.213 ;
     RECT  43.212 8.579 44.208 8.627 ;
     RECT  41.4 8.677 42.9 9.203 ;
     RECT  27.96 9.061 29.4 10.883 ;
     RECT  47.304 9.155 48.3 10.259 ;
     RECT  23.568 9.491 24 10.885 ;
     RECT  38.664 9.925 40.08 9.971 ;
     RECT  45.912 10.213 47.04 10.309 ;
     RECT  60.6 10.213 61.8 10.979 ;
     RECT  47.16 10.259 48.3 13.045 ;
     RECT  59.412 10.307 60.576 10.979 ;
     RECT  46.008 10.309 47.04 10.931 ;
     RECT  21.612 10.885 22.8 11.555 ;
     RECT  22.824 10.885 24 11.555 ;
     RECT  46.008 10.931 47.136 12.083 ;
     RECT  18.912 11.173 20.4 11.221 ;
     RECT  18.48 11.411 18.6 12.517 ;
     RECT  29.712 11.605 30.816 12.131 ;
     RECT  30.84 11.605 32.1 12.131 ;
     RECT  45.912 12.083 47.136 13.091 ;
     RECT  10.812 12.613 11.856 13.619 ;
     RECT  11.88 12.613 13.2 13.619 ;
     RECT  47.256 13.045 48.3 15.251 ;
     RECT  19.8 13.091 21.3 15.205 ;
     RECT  45.912 13.091 47.232 15.205 ;
     RECT  21.612 14.197 22.8 15.349 ;
     RECT  22.824 14.197 24 15.491 ;
     RECT  54.012 15.061 55.536 16.931 ;
     RECT  19.896 15.205 21.3 16.261 ;
     RECT  46.776 15.251 48.3 15.973 ;
     RECT  21.912 15.491 24 16.021 ;
     RECT  37.812 15.827 38.184 15.973 ;
     RECT  37.812 15.973 39.12 16.115 ;
     RECT  46.776 15.973 48.192 16.787 ;
     RECT  21.912 16.021 23.904 16.933 ;
     RECT  13.704 16.259 13.896 17.029 ;
     RECT  19.896 16.261 21.168 16.981 ;
     RECT  45.912 16.787 48.192 17.605 ;
     RECT  40.512 16.837 41.76 17.747 ;
     RECT  41.784 16.837 42.9 17.747 ;
     RECT  21.912 16.933 23.328 17.651 ;
     RECT  8.112 16.981 9.12 17.123 ;
     RECT  19.896 16.981 21.072 17.123 ;
     RECT  24.312 17.027 24.936 18.181 ;
     RECT  13.704 17.029 14.832 17.219 ;
     RECT  27.012 17.029 28.032 17.891 ;
     RECT  28.056 17.029 29.4 17.891 ;
     RECT  19.896 17.123 21.168 20.579 ;
     RECT  16.212 17.605 17.712 18.275 ;
     RECT  45.912 17.605 47.376 18.133 ;
     RECT  59.412 17.605 60.864 21.541 ;
     RECT  21.912 17.651 24 17.989 ;
     RECT  42.624 17.747 42.9 18.661 ;
     RECT  29.136 17.891 29.4 18.661 ;
     RECT  22.488 17.989 24 19.091 ;
     RECT  45.912 18.133 46.992 19.429 ;
     RECT  56.808 18.709 58.176 20.003 ;
     RECT  21.912 19.091 24 19.333 ;
     RECT  11.736 19.333 13.2 20.099 ;
     RECT  21.912 19.333 22.944 19.811 ;
     RECT  22.968 19.333 24 19.811 ;
     RECT  30.6 19.621 31.872 19.717 ;
     RECT  49.224 19.621 50.736 20.195 ;
     RECT  30.6 19.859 31.872 20.099 ;
     RECT  41.064 19.861 42.144 20.003 ;
     RECT  45.912 20.003 47.376 20.339 ;
     RECT  56.712 20.003 58.176 21.493 ;
     RECT  54.012 20.053 55.152 20.149 ;
     RECT  55.176 20.053 56.4 24.563 ;
     RECT  30.504 20.099 31.872 20.339 ;
     RECT  45.912 20.339 46.008 21.733 ;
     RECT  21.12 20.579 21.168 21.349 ;
     RECT  40.032 20.579 40.08 21.637 ;
     RECT  31.872 20.723 32.1 21.925 ;
     RECT  51.312 21.157 52.608 22.883 ;
     RECT  52.632 21.157 53.7 22.883 ;
     RECT  50.736 21.203 51 22.597 ;
     RECT  35.112 21.493 36.192 21.925 ;
     RECT  56.712 21.493 57.84 23.843 ;
     RECT  36.216 21.539 37.5 22.307 ;
     RECT  59.544 21.541 60.864 21.683 ;
     RECT  5.412 21.637 6.672 22.451 ;
     RECT  6.696 21.637 7.8 22.451 ;
     RECT  54.012 21.683 55.152 24.563 ;
     RECT  59.544 21.683 61.536 22.069 ;
     RECT  10.812 21.733 12 22.883 ;
     RECT  12.024 21.733 13.2 22.883 ;
     RECT  29.712 21.925 30.864 22.451 ;
     RECT  30.888 21.925 32.1 22.309 ;
     RECT  35.112 22.067 36.192 22.307 ;
     RECT  59.592 22.069 61.536 22.117 ;
     RECT  60.408 22.117 61.536 23.411 ;
     RECT  43.212 22.163 43.32 22.741 ;
     RECT  18.912 22.165 19.968 22.979 ;
     RECT  19.992 22.165 21.12 22.643 ;
     RECT  37.392 22.307 37.5 23.557 ;
     RECT  57.864 22.307 58.992 23.411 ;
     RECT  30.888 22.309 31.872 22.451 ;
     RECT  25.224 22.597 26.7 22.739 ;
     RECT  19.992 22.643 21.168 22.979 ;
     RECT  23.904 22.643 24 23.845 ;
     RECT  43.212 22.741 44.4 24.083 ;
     RECT  44.424 22.741 45.6 24.083 ;
     RECT  13.512 22.837 14.64 23.363 ;
     RECT  14.664 22.837 15.9 23.363 ;
     RECT  21.912 23.075 22.296 23.845 ;
     RECT  8.112 23.077 9.12 23.219 ;
     RECT  57.864 23.411 59.1 23.843 ;
     RECT  60.36 23.411 61.536 23.987 ;
     RECT  21.912 23.845 23.184 25.091 ;
     RECT  60.36 23.987 61.632 24.131 ;
     RECT  27.012 24.131 27.384 25.573 ;
     RECT  17.16 24.133 18.6 25.813 ;
     RECT  23.904 25.091 24 26.101 ;
     RECT  40.08 25.139 40.2 25.717 ;
     RECT  27.912 25.573 29.088 26.243 ;
     RECT  38.76 25.717 40.2 25.859 ;
     RECT  17.16 25.813 18.384 26.773 ;
     RECT  27.912 26.243 29.4 26.531 ;
     RECT  21.912 26.773 23.04 27.301 ;
     RECT  25.368 26.773 26.7 26.821 ;
     RECT  25.512 26.821 26.7 27.023 ;
     RECT  25.512 27.023 25.944 27.205 ;
  END
END qkd_seq_core_static_p
END LIBRARY
